VERSION 5.7 ;
  NOWIREEXTENSIONATPIN ON ;
  DIVIDERCHAR "/" ;
  BUSBITCHARS "[]" ;
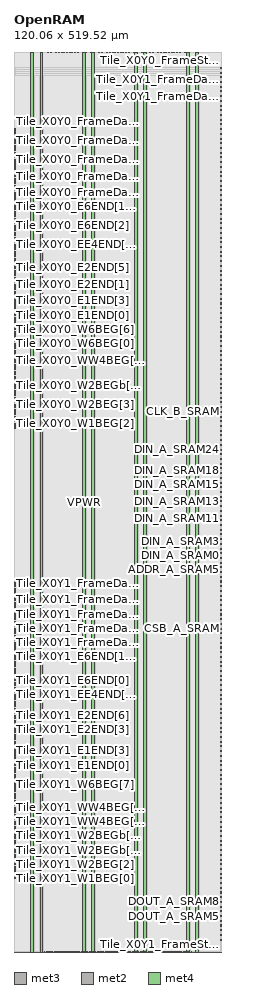
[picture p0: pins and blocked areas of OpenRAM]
MACRO OpenRAM
  CLASS BLOCK ;
  FOREIGN OpenRAM ;
  ORIGIN 0.000 0.000 ;
  SIZE 120.060 BY 519.520 ;
  PIN ADDR_A_SRAM0
    DIRECTION OUTPUT ;
    USE SIGNAL ;
    ANTENNADIFFAREA 0.445500 ;
    PORT
      LAYER met3 ;
        RECT 119.460 202.680 120.060 203.280 ;
    END
  END ADDR_A_SRAM0
  PIN ADDR_A_SRAM1
    DIRECTION OUTPUT ;
    USE SIGNAL ;
    ANTENNADIFFAREA 0.445500 ;
    PORT
      LAYER met3 ;
        RECT 119.460 205.400 120.060 206.000 ;
    END
  END ADDR_A_SRAM1
  PIN ADDR_A_SRAM2
    DIRECTION OUTPUT ;
    USE SIGNAL ;
    ANTENNADIFFAREA 0.445500 ;
    PORT
      LAYER met3 ;
        RECT 119.460 208.120 120.060 208.720 ;
    END
  END ADDR_A_SRAM2
  PIN ADDR_A_SRAM3
    DIRECTION OUTPUT ;
    USE SIGNAL ;
    ANTENNADIFFAREA 0.445500 ;
    PORT
      LAYER met3 ;
        RECT 119.460 210.840 120.060 211.440 ;
    END
  END ADDR_A_SRAM3
  PIN ADDR_A_SRAM4
    DIRECTION OUTPUT ;
    USE SIGNAL ;
    ANTENNADIFFAREA 0.445500 ;
    PORT
      LAYER met3 ;
        RECT 119.460 213.560 120.060 214.160 ;
    END
  END ADDR_A_SRAM4
  PIN ADDR_A_SRAM5
    DIRECTION OUTPUT ;
    USE SIGNAL ;
    ANTENNADIFFAREA 0.445500 ;
    PORT
      LAYER met3 ;
        RECT 119.460 216.280 120.060 216.880 ;
    END
  END ADDR_A_SRAM5
  PIN ADDR_A_SRAM6
    DIRECTION OUTPUT ;
    USE SIGNAL ;
    ANTENNADIFFAREA 0.445500 ;
    PORT
      LAYER met3 ;
        RECT 119.460 219.000 120.060 219.600 ;
    END
  END ADDR_A_SRAM6
  PIN ADDR_A_SRAM7
    DIRECTION OUTPUT ;
    USE SIGNAL ;
    ANTENNADIFFAREA 0.445500 ;
    PORT
      LAYER met3 ;
        RECT 119.460 221.720 120.060 222.320 ;
    END
  END ADDR_A_SRAM7
  PIN ADDR_B_SRAM0
    DIRECTION OUTPUT ;
    USE SIGNAL ;
    ANTENNADIFFAREA 0.445500 ;
    PORT
      LAYER met3 ;
        RECT 119.460 316.920 120.060 317.520 ;
    END
  END ADDR_B_SRAM0
  PIN ADDR_B_SRAM1
    DIRECTION OUTPUT ;
    USE SIGNAL ;
    ANTENNADIFFAREA 0.445500 ;
    PORT
      LAYER met3 ;
        RECT 119.460 319.640 120.060 320.240 ;
    END
  END ADDR_B_SRAM1
  PIN ADDR_B_SRAM2
    DIRECTION OUTPUT ;
    USE SIGNAL ;
    ANTENNADIFFAREA 0.445500 ;
    PORT
      LAYER met3 ;
        RECT 119.460 322.360 120.060 322.960 ;
    END
  END ADDR_B_SRAM2
  PIN ADDR_B_SRAM3
    DIRECTION OUTPUT ;
    USE SIGNAL ;
    ANTENNADIFFAREA 0.445500 ;
    PORT
      LAYER met3 ;
        RECT 119.460 325.080 120.060 325.680 ;
    END
  END ADDR_B_SRAM3
  PIN ADDR_B_SRAM4
    DIRECTION OUTPUT ;
    USE SIGNAL ;
    ANTENNADIFFAREA 0.445500 ;
    PORT
      LAYER met3 ;
        RECT 119.460 327.800 120.060 328.400 ;
    END
  END ADDR_B_SRAM4
  PIN ADDR_B_SRAM5
    DIRECTION OUTPUT ;
    USE SIGNAL ;
    ANTENNADIFFAREA 0.445500 ;
    PORT
      LAYER met3 ;
        RECT 119.460 330.520 120.060 331.120 ;
    END
  END ADDR_B_SRAM5
  PIN ADDR_B_SRAM6
    DIRECTION OUTPUT ;
    USE SIGNAL ;
    ANTENNADIFFAREA 0.445500 ;
    PORT
      LAYER met3 ;
        RECT 119.460 333.240 120.060 333.840 ;
    END
  END ADDR_B_SRAM6
  PIN ADDR_B_SRAM7
    DIRECTION OUTPUT ;
    USE SIGNAL ;
    ANTENNADIFFAREA 0.445500 ;
    PORT
      LAYER met3 ;
        RECT 119.460 335.960 120.060 336.560 ;
    END
  END ADDR_B_SRAM7
  PIN CLK_A_SRAM
    DIRECTION OUTPUT ;
    USE SIGNAL ;
    ANTENNADIFFAREA 0.340600 ;
    PORT
      LAYER met3 ;
        RECT 119.460 183.640 120.060 184.240 ;
    END
  END CLK_A_SRAM
  PIN CLK_B_SRAM
    DIRECTION OUTPUT ;
    USE SIGNAL ;
    ANTENNADIFFAREA 0.340600 ;
    PORT
      LAYER met3 ;
        RECT 119.460 311.480 120.060 312.080 ;
    END
  END CLK_B_SRAM
  PIN CONFIGURED_top
    DIRECTION INPUT ;
    USE SIGNAL ;
    ANTENNAGATEAREA 0.126000 ;
    PORT
      LAYER met3 ;
        RECT 119.460 180.920 120.060 181.520 ;
    END
  END CONFIGURED_top
  PIN CSB_A_SRAM
    DIRECTION OUTPUT ;
    USE SIGNAL ;
    ANTENNADIFFAREA 0.445500 ;
    PORT
      LAYER met3 ;
        RECT 119.460 186.360 120.060 186.960 ;
    END
  END CSB_A_SRAM
  PIN CSB_B_SRAM
    DIRECTION OUTPUT ;
    USE SIGNAL ;
    ANTENNADIFFAREA 0.445500 ;
    PORT
      LAYER met3 ;
        RECT 119.460 314.200 120.060 314.800 ;
    END
  END CSB_B_SRAM
  PIN DIN_A_SRAM0
    DIRECTION OUTPUT ;
    USE SIGNAL ;
    ANTENNADIFFAREA 0.445500 ;
    PORT
      LAYER met3 ;
        RECT 119.460 224.440 120.060 225.040 ;
    END
  END DIN_A_SRAM0
  PIN DIN_A_SRAM1
    DIRECTION OUTPUT ;
    USE SIGNAL ;
    ANTENNADIFFAREA 0.445500 ;
    PORT
      LAYER met3 ;
        RECT 119.460 227.160 120.060 227.760 ;
    END
  END DIN_A_SRAM1
  PIN DIN_A_SRAM10
    DIRECTION OUTPUT ;
    USE SIGNAL ;
    ANTENNADIFFAREA 0.445500 ;
    PORT
      LAYER met3 ;
        RECT 119.460 251.640 120.060 252.240 ;
    END
  END DIN_A_SRAM10
  PIN DIN_A_SRAM11
    DIRECTION OUTPUT ;
    USE SIGNAL ;
    ANTENNADIFFAREA 0.445500 ;
    PORT
      LAYER met3 ;
        RECT 119.460 254.360 120.060 254.960 ;
    END
  END DIN_A_SRAM11
  PIN DIN_A_SRAM12
    DIRECTION OUTPUT ;
    USE SIGNAL ;
    ANTENNADIFFAREA 0.445500 ;
    PORT
      LAYER met3 ;
        RECT 119.460 257.080 120.060 257.680 ;
    END
  END DIN_A_SRAM12
  PIN DIN_A_SRAM13
    DIRECTION OUTPUT ;
    USE SIGNAL ;
    ANTENNADIFFAREA 0.445500 ;
    PORT
      LAYER met3 ;
        RECT 119.460 259.800 120.060 260.400 ;
    END
  END DIN_A_SRAM13
  PIN DIN_A_SRAM14
    DIRECTION OUTPUT ;
    USE SIGNAL ;
    ANTENNADIFFAREA 0.445500 ;
    PORT
      LAYER met3 ;
        RECT 119.460 262.520 120.060 263.120 ;
    END
  END DIN_A_SRAM14
  PIN DIN_A_SRAM15
    DIRECTION OUTPUT ;
    USE SIGNAL ;
    ANTENNADIFFAREA 0.445500 ;
    PORT
      LAYER met3 ;
        RECT 119.460 265.240 120.060 265.840 ;
    END
  END DIN_A_SRAM15
  PIN DIN_A_SRAM16
    DIRECTION OUTPUT ;
    USE SIGNAL ;
    ANTENNADIFFAREA 0.445500 ;
    PORT
      LAYER met3 ;
        RECT 119.460 267.960 120.060 268.560 ;
    END
  END DIN_A_SRAM16
  PIN DIN_A_SRAM17
    DIRECTION OUTPUT ;
    USE SIGNAL ;
    ANTENNADIFFAREA 0.445500 ;
    PORT
      LAYER met3 ;
        RECT 119.460 270.680 120.060 271.280 ;
    END
  END DIN_A_SRAM17
  PIN DIN_A_SRAM18
    DIRECTION OUTPUT ;
    USE SIGNAL ;
    ANTENNADIFFAREA 0.445500 ;
    PORT
      LAYER met3 ;
        RECT 119.460 273.400 120.060 274.000 ;
    END
  END DIN_A_SRAM18
  PIN DIN_A_SRAM19
    DIRECTION OUTPUT ;
    USE SIGNAL ;
    ANTENNADIFFAREA 0.445500 ;
    PORT
      LAYER met3 ;
        RECT 119.460 276.120 120.060 276.720 ;
    END
  END DIN_A_SRAM19
  PIN DIN_A_SRAM2
    DIRECTION OUTPUT ;
    USE SIGNAL ;
    ANTENNADIFFAREA 0.445500 ;
    PORT
      LAYER met3 ;
        RECT 119.460 229.880 120.060 230.480 ;
    END
  END DIN_A_SRAM2
  PIN DIN_A_SRAM20
    DIRECTION OUTPUT ;
    USE SIGNAL ;
    ANTENNADIFFAREA 0.445500 ;
    PORT
      LAYER met3 ;
        RECT 119.460 278.840 120.060 279.440 ;
    END
  END DIN_A_SRAM20
  PIN DIN_A_SRAM21
    DIRECTION OUTPUT ;
    USE SIGNAL ;
    ANTENNADIFFAREA 0.445500 ;
    PORT
      LAYER met3 ;
        RECT 119.460 281.560 120.060 282.160 ;
    END
  END DIN_A_SRAM21
  PIN DIN_A_SRAM22
    DIRECTION OUTPUT ;
    USE SIGNAL ;
    ANTENNADIFFAREA 0.445500 ;
    PORT
      LAYER met3 ;
        RECT 119.460 284.280 120.060 284.880 ;
    END
  END DIN_A_SRAM22
  PIN DIN_A_SRAM23
    DIRECTION OUTPUT ;
    USE SIGNAL ;
    ANTENNADIFFAREA 0.445500 ;
    PORT
      LAYER met3 ;
        RECT 119.460 287.000 120.060 287.600 ;
    END
  END DIN_A_SRAM23
  PIN DIN_A_SRAM24
    DIRECTION OUTPUT ;
    USE SIGNAL ;
    ANTENNADIFFAREA 0.445500 ;
    PORT
      LAYER met3 ;
        RECT 119.460 289.720 120.060 290.320 ;
    END
  END DIN_A_SRAM24
  PIN DIN_A_SRAM25
    DIRECTION OUTPUT ;
    USE SIGNAL ;
    ANTENNADIFFAREA 0.445500 ;
    PORT
      LAYER met3 ;
        RECT 119.460 292.440 120.060 293.040 ;
    END
  END DIN_A_SRAM25
  PIN DIN_A_SRAM26
    DIRECTION OUTPUT ;
    USE SIGNAL ;
    ANTENNADIFFAREA 0.445500 ;
    PORT
      LAYER met3 ;
        RECT 119.460 295.160 120.060 295.760 ;
    END
  END DIN_A_SRAM26
  PIN DIN_A_SRAM27
    DIRECTION OUTPUT ;
    USE SIGNAL ;
    ANTENNADIFFAREA 0.445500 ;
    PORT
      LAYER met3 ;
        RECT 119.460 297.880 120.060 298.480 ;
    END
  END DIN_A_SRAM27
  PIN DIN_A_SRAM28
    DIRECTION OUTPUT ;
    USE SIGNAL ;
    ANTENNADIFFAREA 0.445500 ;
    PORT
      LAYER met3 ;
        RECT 119.460 300.600 120.060 301.200 ;
    END
  END DIN_A_SRAM28
  PIN DIN_A_SRAM29
    DIRECTION OUTPUT ;
    USE SIGNAL ;
    ANTENNADIFFAREA 0.445500 ;
    PORT
      LAYER met3 ;
        RECT 119.460 303.320 120.060 303.920 ;
    END
  END DIN_A_SRAM29
  PIN DIN_A_SRAM3
    DIRECTION OUTPUT ;
    USE SIGNAL ;
    ANTENNADIFFAREA 0.445500 ;
    PORT
      LAYER met3 ;
        RECT 119.460 232.600 120.060 233.200 ;
    END
  END DIN_A_SRAM3
  PIN DIN_A_SRAM30
    DIRECTION OUTPUT ;
    USE SIGNAL ;
    ANTENNADIFFAREA 0.445500 ;
    PORT
      LAYER met3 ;
        RECT 119.460 306.040 120.060 306.640 ;
    END
  END DIN_A_SRAM30
  PIN DIN_A_SRAM31
    DIRECTION OUTPUT ;
    USE SIGNAL ;
    ANTENNADIFFAREA 0.445500 ;
    PORT
      LAYER met3 ;
        RECT 119.460 308.760 120.060 309.360 ;
    END
  END DIN_A_SRAM31
  PIN DIN_A_SRAM4
    DIRECTION OUTPUT ;
    USE SIGNAL ;
    ANTENNADIFFAREA 0.445500 ;
    PORT
      LAYER met3 ;
        RECT 119.460 235.320 120.060 235.920 ;
    END
  END DIN_A_SRAM4
  PIN DIN_A_SRAM5
    DIRECTION OUTPUT ;
    USE SIGNAL ;
    ANTENNADIFFAREA 0.445500 ;
    PORT
      LAYER met3 ;
        RECT 119.460 238.040 120.060 238.640 ;
    END
  END DIN_A_SRAM5
  PIN DIN_A_SRAM6
    DIRECTION OUTPUT ;
    USE SIGNAL ;
    ANTENNADIFFAREA 0.445500 ;
    PORT
      LAYER met3 ;
        RECT 119.460 240.760 120.060 241.360 ;
    END
  END DIN_A_SRAM6
  PIN DIN_A_SRAM7
    DIRECTION OUTPUT ;
    USE SIGNAL ;
    ANTENNADIFFAREA 0.445500 ;
    PORT
      LAYER met3 ;
        RECT 119.460 243.480 120.060 244.080 ;
    END
  END DIN_A_SRAM7
  PIN DIN_A_SRAM8
    DIRECTION OUTPUT ;
    USE SIGNAL ;
    ANTENNADIFFAREA 0.445500 ;
    PORT
      LAYER met3 ;
        RECT 119.460 246.200 120.060 246.800 ;
    END
  END DIN_A_SRAM8
  PIN DIN_A_SRAM9
    DIRECTION OUTPUT ;
    USE SIGNAL ;
    ANTENNADIFFAREA 0.445500 ;
    PORT
      LAYER met3 ;
        RECT 119.460 248.920 120.060 249.520 ;
    END
  END DIN_A_SRAM9
  PIN DOUT_A_SRAM0
    DIRECTION INPUT ;
    USE SIGNAL ;
    ANTENNAGATEAREA 0.213000 ;
    PORT
      LAYER met3 ;
        RECT 119.460 6.840 120.060 7.440 ;
    END
  END DOUT_A_SRAM0
  PIN DOUT_A_SRAM1
    DIRECTION INPUT ;
    USE SIGNAL ;
    ANTENNAGATEAREA 0.196500 ;
    PORT
      LAYER met3 ;
        RECT 119.460 9.560 120.060 10.160 ;
    END
  END DOUT_A_SRAM1
  PIN DOUT_A_SRAM10
    DIRECTION INPUT ;
    USE SIGNAL ;
    ANTENNAGATEAREA 0.196500 ;
    PORT
      LAYER met3 ;
        RECT 119.460 34.040 120.060 34.640 ;
    END
  END DOUT_A_SRAM10
  PIN DOUT_A_SRAM11
    DIRECTION INPUT ;
    USE SIGNAL ;
    ANTENNAGATEAREA 0.196500 ;
    PORT
      LAYER met3 ;
        RECT 119.460 36.760 120.060 37.360 ;
    END
  END DOUT_A_SRAM11
  PIN DOUT_A_SRAM12
    DIRECTION INPUT ;
    USE SIGNAL ;
    ANTENNAGATEAREA 0.196500 ;
    PORT
      LAYER met3 ;
        RECT 119.460 39.480 120.060 40.080 ;
    END
  END DOUT_A_SRAM12
  PIN DOUT_A_SRAM13
    DIRECTION INPUT ;
    USE SIGNAL ;
    ANTENNAGATEAREA 0.196500 ;
    PORT
      LAYER met3 ;
        RECT 119.460 42.200 120.060 42.800 ;
    END
  END DOUT_A_SRAM13
  PIN DOUT_A_SRAM14
    DIRECTION INPUT ;
    USE SIGNAL ;
    ANTENNAGATEAREA 0.196500 ;
    PORT
      LAYER met3 ;
        RECT 119.460 44.920 120.060 45.520 ;
    END
  END DOUT_A_SRAM14
  PIN DOUT_A_SRAM15
    DIRECTION INPUT ;
    USE SIGNAL ;
    ANTENNAGATEAREA 0.196500 ;
    PORT
      LAYER met3 ;
        RECT 119.460 47.640 120.060 48.240 ;
    END
  END DOUT_A_SRAM15
  PIN DOUT_A_SRAM16
    DIRECTION INPUT ;
    USE SIGNAL ;
    ANTENNAGATEAREA 0.159000 ;
    PORT
      LAYER met3 ;
        RECT 119.460 50.360 120.060 50.960 ;
    END
  END DOUT_A_SRAM16
  PIN DOUT_A_SRAM17
    DIRECTION INPUT ;
    USE SIGNAL ;
    ANTENNAGATEAREA 0.159000 ;
    PORT
      LAYER met3 ;
        RECT 119.460 53.080 120.060 53.680 ;
    END
  END DOUT_A_SRAM17
  PIN DOUT_A_SRAM18
    DIRECTION INPUT ;
    USE SIGNAL ;
    ANTENNAGATEAREA 0.213000 ;
    PORT
      LAYER met3 ;
        RECT 119.460 55.800 120.060 56.400 ;
    END
  END DOUT_A_SRAM18
  PIN DOUT_A_SRAM19
    DIRECTION INPUT ;
    USE SIGNAL ;
    ANTENNAGATEAREA 0.159000 ;
    PORT
      LAYER met3 ;
        RECT 119.460 58.520 120.060 59.120 ;
    END
  END DOUT_A_SRAM19
  PIN DOUT_A_SRAM2
    DIRECTION INPUT ;
    USE SIGNAL ;
    ANTENNAGATEAREA 0.196500 ;
    PORT
      LAYER met3 ;
        RECT 119.460 12.280 120.060 12.880 ;
    END
  END DOUT_A_SRAM2
  PIN DOUT_A_SRAM20
    DIRECTION INPUT ;
    USE SIGNAL ;
    ANTENNAGATEAREA 0.159000 ;
    PORT
      LAYER met3 ;
        RECT 119.460 61.240 120.060 61.840 ;
    END
  END DOUT_A_SRAM20
  PIN DOUT_A_SRAM21
    DIRECTION INPUT ;
    USE SIGNAL ;
    ANTENNAGATEAREA 0.213000 ;
    PORT
      LAYER met3 ;
        RECT 119.460 63.960 120.060 64.560 ;
    END
  END DOUT_A_SRAM21
  PIN DOUT_A_SRAM22
    DIRECTION INPUT ;
    USE SIGNAL ;
    ANTENNAGATEAREA 0.159000 ;
    PORT
      LAYER met3 ;
        RECT 119.460 66.680 120.060 67.280 ;
    END
  END DOUT_A_SRAM22
  PIN DOUT_A_SRAM23
    DIRECTION INPUT ;
    USE SIGNAL ;
    ANTENNAGATEAREA 0.159000 ;
    PORT
      LAYER met3 ;
        RECT 119.460 69.400 120.060 70.000 ;
    END
  END DOUT_A_SRAM23
  PIN DOUT_A_SRAM24
    DIRECTION INPUT ;
    USE SIGNAL ;
    ANTENNAGATEAREA 0.213000 ;
    PORT
      LAYER met3 ;
        RECT 119.460 72.120 120.060 72.720 ;
    END
  END DOUT_A_SRAM24
  PIN DOUT_A_SRAM25
    DIRECTION INPUT ;
    USE SIGNAL ;
    ANTENNAGATEAREA 0.159000 ;
    PORT
      LAYER met3 ;
        RECT 119.460 74.840 120.060 75.440 ;
    END
  END DOUT_A_SRAM25
  PIN DOUT_A_SRAM26
    DIRECTION INPUT ;
    USE SIGNAL ;
    ANTENNAGATEAREA 0.213000 ;
    PORT
      LAYER met3 ;
        RECT 119.460 77.560 120.060 78.160 ;
    END
  END DOUT_A_SRAM26
  PIN DOUT_A_SRAM27
    DIRECTION INPUT ;
    USE SIGNAL ;
    ANTENNAGATEAREA 0.213000 ;
    PORT
      LAYER met3 ;
        RECT 119.460 80.280 120.060 80.880 ;
    END
  END DOUT_A_SRAM27
  PIN DOUT_A_SRAM28
    DIRECTION INPUT ;
    USE SIGNAL ;
    ANTENNAGATEAREA 0.213000 ;
    PORT
      LAYER met3 ;
        RECT 119.460 83.000 120.060 83.600 ;
    END
  END DOUT_A_SRAM28
  PIN DOUT_A_SRAM29
    DIRECTION INPUT ;
    USE SIGNAL ;
    ANTENNAGATEAREA 0.213000 ;
    PORT
      LAYER met3 ;
        RECT 119.460 85.720 120.060 86.320 ;
    END
  END DOUT_A_SRAM29
  PIN DOUT_A_SRAM3
    DIRECTION INPUT ;
    USE SIGNAL ;
    ANTENNAGATEAREA 0.213000 ;
    PORT
      LAYER met3 ;
        RECT 119.460 15.000 120.060 15.600 ;
    END
  END DOUT_A_SRAM3
  PIN DOUT_A_SRAM30
    DIRECTION INPUT ;
    USE SIGNAL ;
    ANTENNAGATEAREA 0.213000 ;
    PORT
      LAYER met3 ;
        RECT 119.460 88.440 120.060 89.040 ;
    END
  END DOUT_A_SRAM30
  PIN DOUT_A_SRAM31
    DIRECTION INPUT ;
    USE SIGNAL ;
    ANTENNAGATEAREA 0.213000 ;
    PORT
      LAYER met3 ;
        RECT 119.460 91.160 120.060 91.760 ;
    END
  END DOUT_A_SRAM31
  PIN DOUT_A_SRAM4
    DIRECTION INPUT ;
    USE SIGNAL ;
    ANTENNAGATEAREA 0.126000 ;
    PORT
      LAYER met3 ;
        RECT 119.460 17.720 120.060 18.320 ;
    END
  END DOUT_A_SRAM4
  PIN DOUT_A_SRAM5
    DIRECTION INPUT ;
    USE SIGNAL ;
    ANTENNAGATEAREA 0.196500 ;
    PORT
      LAYER met3 ;
        RECT 119.460 20.440 120.060 21.040 ;
    END
  END DOUT_A_SRAM5
  PIN DOUT_A_SRAM6
    DIRECTION INPUT ;
    USE SIGNAL ;
    ANTENNAGATEAREA 0.196500 ;
    PORT
      LAYER met3 ;
        RECT 119.460 23.160 120.060 23.760 ;
    END
  END DOUT_A_SRAM6
  PIN DOUT_A_SRAM7
    DIRECTION INPUT ;
    USE SIGNAL ;
    ANTENNAGATEAREA 0.126000 ;
    PORT
      LAYER met3 ;
        RECT 119.460 25.880 120.060 26.480 ;
    END
  END DOUT_A_SRAM7
  PIN DOUT_A_SRAM8
    DIRECTION INPUT ;
    USE SIGNAL ;
    ANTENNAGATEAREA 0.126000 ;
    PORT
      LAYER met3 ;
        RECT 119.460 28.600 120.060 29.200 ;
    END
  END DOUT_A_SRAM8
  PIN DOUT_A_SRAM9
    DIRECTION INPUT ;
    USE SIGNAL ;
    ANTENNAGATEAREA 0.196500 ;
    PORT
      LAYER met3 ;
        RECT 119.460 31.320 120.060 31.920 ;
    END
  END DOUT_A_SRAM9
  PIN DOUT_B_SRAM0
    DIRECTION INPUT ;
    USE SIGNAL ;
    ANTENNAGATEAREA 0.126000 ;
    PORT
      LAYER met3 ;
        RECT 119.460 93.880 120.060 94.480 ;
    END
  END DOUT_B_SRAM0
  PIN DOUT_B_SRAM1
    DIRECTION INPUT ;
    USE SIGNAL ;
    ANTENNAGATEAREA 0.196500 ;
    PORT
      LAYER met3 ;
        RECT 119.460 96.600 120.060 97.200 ;
    END
  END DOUT_B_SRAM1
  PIN DOUT_B_SRAM10
    DIRECTION INPUT ;
    USE SIGNAL ;
    ANTENNAGATEAREA 0.196500 ;
    PORT
      LAYER met3 ;
        RECT 119.460 121.080 120.060 121.680 ;
    END
  END DOUT_B_SRAM10
  PIN DOUT_B_SRAM11
    DIRECTION INPUT ;
    USE SIGNAL ;
    ANTENNAGATEAREA 0.196500 ;
    PORT
      LAYER met3 ;
        RECT 119.460 123.800 120.060 124.400 ;
    END
  END DOUT_B_SRAM11
  PIN DOUT_B_SRAM12
    DIRECTION INPUT ;
    USE SIGNAL ;
    ANTENNAGATEAREA 0.126000 ;
    PORT
      LAYER met3 ;
        RECT 119.460 126.520 120.060 127.120 ;
    END
  END DOUT_B_SRAM12
  PIN DOUT_B_SRAM13
    DIRECTION INPUT ;
    USE SIGNAL ;
    ANTENNAGATEAREA 0.196500 ;
    PORT
      LAYER met3 ;
        RECT 119.460 129.240 120.060 129.840 ;
    END
  END DOUT_B_SRAM13
  PIN DOUT_B_SRAM14
    DIRECTION INPUT ;
    USE SIGNAL ;
    ANTENNAGATEAREA 0.196500 ;
    PORT
      LAYER met3 ;
        RECT 119.460 131.960 120.060 132.560 ;
    END
  END DOUT_B_SRAM14
  PIN DOUT_B_SRAM15
    DIRECTION INPUT ;
    USE SIGNAL ;
    ANTENNAGATEAREA 0.196500 ;
    PORT
      LAYER met3 ;
        RECT 119.460 134.680 120.060 135.280 ;
    END
  END DOUT_B_SRAM15
  PIN DOUT_B_SRAM16
    DIRECTION INPUT ;
    USE SIGNAL ;
    ANTENNAGATEAREA 0.213000 ;
    PORT
      LAYER met3 ;
        RECT 119.460 137.400 120.060 138.000 ;
    END
  END DOUT_B_SRAM16
  PIN DOUT_B_SRAM17
    DIRECTION INPUT ;
    USE SIGNAL ;
    ANTENNAGATEAREA 0.213000 ;
    PORT
      LAYER met3 ;
        RECT 119.460 140.120 120.060 140.720 ;
    END
  END DOUT_B_SRAM17
  PIN DOUT_B_SRAM18
    DIRECTION INPUT ;
    USE SIGNAL ;
    ANTENNAGATEAREA 0.159000 ;
    PORT
      LAYER met3 ;
        RECT 119.460 142.840 120.060 143.440 ;
    END
  END DOUT_B_SRAM18
  PIN DOUT_B_SRAM19
    DIRECTION INPUT ;
    USE SIGNAL ;
    ANTENNAGATEAREA 0.213000 ;
    PORT
      LAYER met3 ;
        RECT 119.460 145.560 120.060 146.160 ;
    END
  END DOUT_B_SRAM19
  PIN DOUT_B_SRAM2
    DIRECTION INPUT ;
    USE SIGNAL ;
    ANTENNAGATEAREA 0.196500 ;
    PORT
      LAYER met3 ;
        RECT 119.460 99.320 120.060 99.920 ;
    END
  END DOUT_B_SRAM2
  PIN DOUT_B_SRAM20
    DIRECTION INPUT ;
    USE SIGNAL ;
    ANTENNAGATEAREA 0.213000 ;
    PORT
      LAYER met3 ;
        RECT 119.460 148.280 120.060 148.880 ;
    END
  END DOUT_B_SRAM20
  PIN DOUT_B_SRAM21
    DIRECTION INPUT ;
    USE SIGNAL ;
    ANTENNAGATEAREA 0.159000 ;
    PORT
      LAYER met3 ;
        RECT 119.460 151.000 120.060 151.600 ;
    END
  END DOUT_B_SRAM21
  PIN DOUT_B_SRAM22
    DIRECTION INPUT ;
    USE SIGNAL ;
    ANTENNAGATEAREA 0.213000 ;
    PORT
      LAYER met3 ;
        RECT 119.460 153.720 120.060 154.320 ;
    END
  END DOUT_B_SRAM22
  PIN DOUT_B_SRAM23
    DIRECTION INPUT ;
    USE SIGNAL ;
    ANTENNAGATEAREA 0.213000 ;
    PORT
      LAYER met3 ;
        RECT 119.460 156.440 120.060 157.040 ;
    END
  END DOUT_B_SRAM23
  PIN DOUT_B_SRAM24
    DIRECTION INPUT ;
    USE SIGNAL ;
    ANTENNAGATEAREA 0.126000 ;
    PORT
      LAYER met3 ;
        RECT 119.460 159.160 120.060 159.760 ;
    END
  END DOUT_B_SRAM24
  PIN DOUT_B_SRAM25
    DIRECTION INPUT ;
    USE SIGNAL ;
    ANTENNAGATEAREA 0.213000 ;
    PORT
      LAYER met3 ;
        RECT 119.460 161.880 120.060 162.480 ;
    END
  END DOUT_B_SRAM25
  PIN DOUT_B_SRAM26
    DIRECTION INPUT ;
    USE SIGNAL ;
    ANTENNAGATEAREA 0.196500 ;
    PORT
      LAYER met3 ;
        RECT 119.460 164.600 120.060 165.200 ;
    END
  END DOUT_B_SRAM26
  PIN DOUT_B_SRAM27
    DIRECTION INPUT ;
    USE SIGNAL ;
    ANTENNAGATEAREA 0.196500 ;
    PORT
      LAYER met3 ;
        RECT 119.460 167.320 120.060 167.920 ;
    END
  END DOUT_B_SRAM27
  PIN DOUT_B_SRAM28
    DIRECTION INPUT ;
    USE SIGNAL ;
    ANTENNAGATEAREA 0.196500 ;
    PORT
      LAYER met3 ;
        RECT 119.460 170.040 120.060 170.640 ;
    END
  END DOUT_B_SRAM28
  PIN DOUT_B_SRAM29
    DIRECTION INPUT ;
    USE SIGNAL ;
    ANTENNAGATEAREA 0.213000 ;
    PORT
      LAYER met3 ;
        RECT 119.460 172.760 120.060 173.360 ;
    END
  END DOUT_B_SRAM29
  PIN DOUT_B_SRAM3
    DIRECTION INPUT ;
    USE SIGNAL ;
    ANTENNAGATEAREA 0.196500 ;
    PORT
      LAYER met3 ;
        RECT 119.460 102.040 120.060 102.640 ;
    END
  END DOUT_B_SRAM3
  PIN DOUT_B_SRAM30
    DIRECTION INPUT ;
    USE SIGNAL ;
    ANTENNAGATEAREA 0.126000 ;
    PORT
      LAYER met3 ;
        RECT 119.460 175.480 120.060 176.080 ;
    END
  END DOUT_B_SRAM30
  PIN DOUT_B_SRAM31
    DIRECTION INPUT ;
    USE SIGNAL ;
    ANTENNAGATEAREA 0.196500 ;
    PORT
      LAYER met3 ;
        RECT 119.460 178.200 120.060 178.800 ;
    END
  END DOUT_B_SRAM31
  PIN DOUT_B_SRAM4
    DIRECTION INPUT ;
    USE SIGNAL ;
    ANTENNAGATEAREA 0.126000 ;
    PORT
      LAYER met3 ;
        RECT 119.460 104.760 120.060 105.360 ;
    END
  END DOUT_B_SRAM4
  PIN DOUT_B_SRAM5
    DIRECTION INPUT ;
    USE SIGNAL ;
    ANTENNAGATEAREA 0.196500 ;
    PORT
      LAYER met3 ;
        RECT 119.460 107.480 120.060 108.080 ;
    END
  END DOUT_B_SRAM5
  PIN DOUT_B_SRAM6
    DIRECTION INPUT ;
    USE SIGNAL ;
    ANTENNAGATEAREA 0.196500 ;
    PORT
      LAYER met3 ;
        RECT 119.460 110.200 120.060 110.800 ;
    END
  END DOUT_B_SRAM6
  PIN DOUT_B_SRAM7
    DIRECTION INPUT ;
    USE SIGNAL ;
    ANTENNAGATEAREA 0.196500 ;
    PORT
      LAYER met3 ;
        RECT 119.460 112.920 120.060 113.520 ;
    END
  END DOUT_B_SRAM7
  PIN DOUT_B_SRAM8
    DIRECTION INPUT ;
    USE SIGNAL ;
    ANTENNAGATEAREA 0.196500 ;
    PORT
      LAYER met3 ;
        RECT 119.460 115.640 120.060 116.240 ;
    END
  END DOUT_B_SRAM8
  PIN DOUT_B_SRAM9
    DIRECTION INPUT ;
    USE SIGNAL ;
    ANTENNAGATEAREA 0.196500 ;
    PORT
      LAYER met3 ;
        RECT 119.460 118.360 120.060 118.960 ;
    END
  END DOUT_B_SRAM9
  PIN Tile_X0Y0_E1END[0]
    DIRECTION INPUT ;
    USE SIGNAL ;
    ANTENNAGATEAREA 0.159000 ;
    PORT
      LAYER met3 ;
        RECT 0.000 367.240 0.600 367.840 ;
    END
  END Tile_X0Y0_E1END[0]
  PIN Tile_X0Y0_E1END[1]
    DIRECTION INPUT ;
    USE SIGNAL ;
    ANTENNAGATEAREA 0.159000 ;
    PORT
      LAYER met3 ;
        RECT 0.000 368.600 0.600 369.200 ;
    END
  END Tile_X0Y0_E1END[1]
  PIN Tile_X0Y0_E1END[2]
    DIRECTION INPUT ;
    USE SIGNAL ;
    ANTENNAGATEAREA 0.213000 ;
    PORT
      LAYER met3 ;
        RECT 0.000 369.960 0.600 370.560 ;
    END
  END Tile_X0Y0_E1END[2]
  PIN Tile_X0Y0_E1END[3]
    DIRECTION INPUT ;
    USE SIGNAL ;
    ANTENNAGATEAREA 0.213000 ;
    PORT
      LAYER met3 ;
        RECT 0.000 371.320 0.600 371.920 ;
    END
  END Tile_X0Y0_E1END[3]
  PIN Tile_X0Y0_E2END[0]
    DIRECTION INPUT ;
    USE SIGNAL ;
    ANTENNAGATEAREA 0.126000 ;
    PORT
      LAYER met3 ;
        RECT 0.000 383.560 0.600 384.160 ;
    END
  END Tile_X0Y0_E2END[0]
  PIN Tile_X0Y0_E2END[1]
    DIRECTION INPUT ;
    USE SIGNAL ;
    ANTENNAGATEAREA 0.213000 ;
    PORT
      LAYER met3 ;
        RECT 0.000 384.920 0.600 385.520 ;
    END
  END Tile_X0Y0_E2END[1]
  PIN Tile_X0Y0_E2END[2]
    DIRECTION INPUT ;
    USE SIGNAL ;
    ANTENNAGATEAREA 0.213000 ;
    PORT
      LAYER met3 ;
        RECT 0.000 386.280 0.600 386.880 ;
    END
  END Tile_X0Y0_E2END[2]
  PIN Tile_X0Y0_E2END[3]
    DIRECTION INPUT ;
    USE SIGNAL ;
    ANTENNAGATEAREA 0.126000 ;
    PORT
      LAYER met3 ;
        RECT 0.000 387.640 0.600 388.240 ;
    END
  END Tile_X0Y0_E2END[3]
  PIN Tile_X0Y0_E2END[4]
    DIRECTION INPUT ;
    USE SIGNAL ;
    ANTENNAGATEAREA 0.196500 ;
    PORT
      LAYER met3 ;
        RECT 0.000 389.000 0.600 389.600 ;
    END
  END Tile_X0Y0_E2END[4]
  PIN Tile_X0Y0_E2END[5]
    DIRECTION INPUT ;
    USE SIGNAL ;
    ANTENNAGATEAREA 0.196500 ;
    PORT
      LAYER met3 ;
        RECT 0.000 390.360 0.600 390.960 ;
    END
  END Tile_X0Y0_E2END[5]
  PIN Tile_X0Y0_E2END[6]
    DIRECTION INPUT ;
    USE SIGNAL ;
    ANTENNAGATEAREA 0.196500 ;
    PORT
      LAYER met3 ;
        RECT 0.000 391.720 0.600 392.320 ;
    END
  END Tile_X0Y0_E2END[6]
  PIN Tile_X0Y0_E2END[7]
    DIRECTION INPUT ;
    USE SIGNAL ;
    ANTENNAGATEAREA 0.196500 ;
    PORT
      LAYER met3 ;
        RECT 0.000 393.080 0.600 393.680 ;
    END
  END Tile_X0Y0_E2END[7]
  PIN Tile_X0Y0_E2MID[0]
    DIRECTION INPUT ;
    USE SIGNAL ;
    ANTENNAGATEAREA 0.196500 ;
    PORT
      LAYER met3 ;
        RECT 0.000 372.680 0.600 373.280 ;
    END
  END Tile_X0Y0_E2MID[0]
  PIN Tile_X0Y0_E2MID[1]
    DIRECTION INPUT ;
    USE SIGNAL ;
    ANTENNAGATEAREA 0.213000 ;
    PORT
      LAYER met3 ;
        RECT 0.000 374.040 0.600 374.640 ;
    END
  END Tile_X0Y0_E2MID[1]
  PIN Tile_X0Y0_E2MID[2]
    DIRECTION INPUT ;
    USE SIGNAL ;
    ANTENNAGATEAREA 0.126000 ;
    PORT
      LAYER met3 ;
        RECT 0.000 375.400 0.600 376.000 ;
    END
  END Tile_X0Y0_E2MID[2]
  PIN Tile_X0Y0_E2MID[3]
    DIRECTION INPUT ;
    USE SIGNAL ;
    ANTENNAGATEAREA 0.126000 ;
    PORT
      LAYER met3 ;
        RECT 0.000 376.760 0.600 377.360 ;
    END
  END Tile_X0Y0_E2MID[3]
  PIN Tile_X0Y0_E2MID[4]
    DIRECTION INPUT ;
    USE SIGNAL ;
    ANTENNAGATEAREA 0.196500 ;
    PORT
      LAYER met3 ;
        RECT 0.000 378.120 0.600 378.720 ;
    END
  END Tile_X0Y0_E2MID[4]
  PIN Tile_X0Y0_E2MID[5]
    DIRECTION INPUT ;
    USE SIGNAL ;
    ANTENNAGATEAREA 0.196500 ;
    PORT
      LAYER met3 ;
        RECT 0.000 379.480 0.600 380.080 ;
    END
  END Tile_X0Y0_E2MID[5]
  PIN Tile_X0Y0_E2MID[6]
    DIRECTION INPUT ;
    USE SIGNAL ;
    ANTENNAGATEAREA 0.196500 ;
    PORT
      LAYER met3 ;
        RECT 0.000 380.840 0.600 381.440 ;
    END
  END Tile_X0Y0_E2MID[6]
  PIN Tile_X0Y0_E2MID[7]
    DIRECTION INPUT ;
    USE SIGNAL ;
    ANTENNAGATEAREA 0.196500 ;
    PORT
      LAYER met3 ;
        RECT 0.000 382.200 0.600 382.800 ;
    END
  END Tile_X0Y0_E2MID[7]
  PIN Tile_X0Y0_E6END[0]
    DIRECTION INPUT ;
    USE SIGNAL ;
    ANTENNAGATEAREA 0.213000 ;
    PORT
      LAYER met3 ;
        RECT 0.000 416.200 0.600 416.800 ;
    END
  END Tile_X0Y0_E6END[0]
  PIN Tile_X0Y0_E6END[10]
    DIRECTION INPUT ;
    USE SIGNAL ;
    ANTENNAGATEAREA 0.126000 ;
    PORT
      LAYER met3 ;
        RECT 0.000 429.800 0.600 430.400 ;
    END
  END Tile_X0Y0_E6END[10]
  PIN Tile_X0Y0_E6END[11]
    DIRECTION INPUT ;
    USE SIGNAL ;
    ANTENNAGATEAREA 0.213000 ;
    PORT
      LAYER met3 ;
        RECT 0.000 431.160 0.600 431.760 ;
    END
  END Tile_X0Y0_E6END[11]
  PIN Tile_X0Y0_E6END[1]
    DIRECTION INPUT ;
    USE SIGNAL ;
    ANTENNAGATEAREA 0.213000 ;
    PORT
      LAYER met3 ;
        RECT 0.000 417.560 0.600 418.160 ;
    END
  END Tile_X0Y0_E6END[1]
  PIN Tile_X0Y0_E6END[2]
    DIRECTION INPUT ;
    USE SIGNAL ;
    ANTENNAGATEAREA 0.126000 ;
    PORT
      LAYER met3 ;
        RECT 0.000 418.920 0.600 419.520 ;
    END
  END Tile_X0Y0_E6END[2]
  PIN Tile_X0Y0_E6END[3]
    DIRECTION INPUT ;
    USE SIGNAL ;
    ANTENNAGATEAREA 0.126000 ;
    PORT
      LAYER met3 ;
        RECT 0.000 420.280 0.600 420.880 ;
    END
  END Tile_X0Y0_E6END[3]
  PIN Tile_X0Y0_E6END[4]
    DIRECTION INPUT ;
    USE SIGNAL ;
    ANTENNAGATEAREA 0.126000 ;
    PORT
      LAYER met3 ;
        RECT 0.000 421.640 0.600 422.240 ;
    END
  END Tile_X0Y0_E6END[4]
  PIN Tile_X0Y0_E6END[5]
    DIRECTION INPUT ;
    USE SIGNAL ;
    ANTENNAGATEAREA 0.126000 ;
    PORT
      LAYER met3 ;
        RECT 0.000 423.000 0.600 423.600 ;
    END
  END Tile_X0Y0_E6END[5]
  PIN Tile_X0Y0_E6END[6]
    DIRECTION INPUT ;
    USE SIGNAL ;
    ANTENNAGATEAREA 0.213000 ;
    PORT
      LAYER met3 ;
        RECT 0.000 424.360 0.600 424.960 ;
    END
  END Tile_X0Y0_E6END[6]
  PIN Tile_X0Y0_E6END[7]
    DIRECTION INPUT ;
    USE SIGNAL ;
    ANTENNAGATEAREA 0.213000 ;
    PORT
      LAYER met3 ;
        RECT 0.000 425.720 0.600 426.320 ;
    END
  END Tile_X0Y0_E6END[7]
  PIN Tile_X0Y0_E6END[8]
    DIRECTION INPUT ;
    USE SIGNAL ;
    ANTENNAGATEAREA 0.126000 ;
    PORT
      LAYER met3 ;
        RECT 0.000 427.080 0.600 427.680 ;
    END
  END Tile_X0Y0_E6END[8]
  PIN Tile_X0Y0_E6END[9]
    DIRECTION INPUT ;
    USE SIGNAL ;
    ANTENNAGATEAREA 0.196500 ;
    PORT
      LAYER met3 ;
        RECT 0.000 428.440 0.600 429.040 ;
    END
  END Tile_X0Y0_E6END[9]
  PIN Tile_X0Y0_EE4END[0]
    DIRECTION INPUT ;
    USE SIGNAL ;
    ANTENNAGATEAREA 0.213000 ;
    PORT
      LAYER met3 ;
        RECT 0.000 394.440 0.600 395.040 ;
    END
  END Tile_X0Y0_EE4END[0]
  PIN Tile_X0Y0_EE4END[10]
    DIRECTION INPUT ;
    USE SIGNAL ;
    ANTENNAGATEAREA 0.196500 ;
    PORT
      LAYER met3 ;
        RECT 0.000 408.040 0.600 408.640 ;
    END
  END Tile_X0Y0_EE4END[10]
  PIN Tile_X0Y0_EE4END[11]
    DIRECTION INPUT ;
    USE SIGNAL ;
    ANTENNAGATEAREA 0.196500 ;
    PORT
      LAYER met3 ;
        RECT 0.000 409.400 0.600 410.000 ;
    END
  END Tile_X0Y0_EE4END[11]
  PIN Tile_X0Y0_EE4END[12]
    DIRECTION INPUT ;
    USE SIGNAL ;
    ANTENNAGATEAREA 0.126000 ;
    PORT
      LAYER met3 ;
        RECT 0.000 410.760 0.600 411.360 ;
    END
  END Tile_X0Y0_EE4END[12]
  PIN Tile_X0Y0_EE4END[13]
    DIRECTION INPUT ;
    USE SIGNAL ;
    ANTENNAGATEAREA 0.196500 ;
    PORT
      LAYER met3 ;
        RECT 0.000 412.120 0.600 412.720 ;
    END
  END Tile_X0Y0_EE4END[13]
  PIN Tile_X0Y0_EE4END[14]
    DIRECTION INPUT ;
    USE SIGNAL ;
    ANTENNAGATEAREA 0.196500 ;
    PORT
      LAYER met3 ;
        RECT 0.000 413.480 0.600 414.080 ;
    END
  END Tile_X0Y0_EE4END[14]
  PIN Tile_X0Y0_EE4END[15]
    DIRECTION INPUT ;
    USE SIGNAL ;
    ANTENNAGATEAREA 0.126000 ;
    PORT
      LAYER met3 ;
        RECT 0.000 414.840 0.600 415.440 ;
    END
  END Tile_X0Y0_EE4END[15]
  PIN Tile_X0Y0_EE4END[1]
    DIRECTION INPUT ;
    USE SIGNAL ;
    ANTENNAGATEAREA 0.196500 ;
    PORT
      LAYER met3 ;
        RECT 0.000 395.800 0.600 396.400 ;
    END
  END Tile_X0Y0_EE4END[1]
  PIN Tile_X0Y0_EE4END[2]
    DIRECTION INPUT ;
    USE SIGNAL ;
    ANTENNAGATEAREA 0.196500 ;
    PORT
      LAYER met3 ;
        RECT 0.000 397.160 0.600 397.760 ;
    END
  END Tile_X0Y0_EE4END[2]
  PIN Tile_X0Y0_EE4END[3]
    DIRECTION INPUT ;
    USE SIGNAL ;
    ANTENNAGATEAREA 0.196500 ;
    PORT
      LAYER met3 ;
        RECT 0.000 398.520 0.600 399.120 ;
    END
  END Tile_X0Y0_EE4END[3]
  PIN Tile_X0Y0_EE4END[4]
    DIRECTION INPUT ;
    USE SIGNAL ;
    ANTENNAGATEAREA 0.126000 ;
    PORT
      LAYER met3 ;
        RECT 0.000 399.880 0.600 400.480 ;
    END
  END Tile_X0Y0_EE4END[4]
  PIN Tile_X0Y0_EE4END[5]
    DIRECTION INPUT ;
    USE SIGNAL ;
    ANTENNAGATEAREA 0.196500 ;
    PORT
      LAYER met3 ;
        RECT 0.000 401.240 0.600 401.840 ;
    END
  END Tile_X0Y0_EE4END[5]
  PIN Tile_X0Y0_EE4END[6]
    DIRECTION INPUT ;
    USE SIGNAL ;
    ANTENNAGATEAREA 0.196500 ;
    PORT
      LAYER met3 ;
        RECT 0.000 402.600 0.600 403.200 ;
    END
  END Tile_X0Y0_EE4END[6]
  PIN Tile_X0Y0_EE4END[7]
    DIRECTION INPUT ;
    USE SIGNAL ;
    ANTENNAGATEAREA 0.196500 ;
    PORT
      LAYER met3 ;
        RECT 0.000 403.960 0.600 404.560 ;
    END
  END Tile_X0Y0_EE4END[7]
  PIN Tile_X0Y0_EE4END[8]
    DIRECTION INPUT ;
    USE SIGNAL ;
    ANTENNAGATEAREA 0.126000 ;
    PORT
      LAYER met3 ;
        RECT 0.000 405.320 0.600 405.920 ;
    END
  END Tile_X0Y0_EE4END[8]
  PIN Tile_X0Y0_EE4END[9]
    DIRECTION INPUT ;
    USE SIGNAL ;
    ANTENNAGATEAREA 0.196500 ;
    PORT
      LAYER met3 ;
        RECT 0.000 406.680 0.600 407.280 ;
    END
  END Tile_X0Y0_EE4END[9]
  PIN Tile_X0Y0_FrameData[0]
    DIRECTION INPUT ;
    USE SIGNAL ;
    ANTENNAGATEAREA 0.213000 ;
    PORT
      LAYER met3 ;
        RECT 0.000 432.520 0.600 433.120 ;
    END
  END Tile_X0Y0_FrameData[0]
  PIN Tile_X0Y0_FrameData[10]
    DIRECTION INPUT ;
    USE SIGNAL ;
    ANTENNAGATEAREA 0.213000 ;
    PORT
      LAYER met3 ;
        RECT 0.000 446.120 0.600 446.720 ;
    END
  END Tile_X0Y0_FrameData[10]
  PIN Tile_X0Y0_FrameData[11]
    DIRECTION INPUT ;
    USE SIGNAL ;
    ANTENNAGATEAREA 0.213000 ;
    PORT
      LAYER met3 ;
        RECT 0.000 447.480 0.600 448.080 ;
    END
  END Tile_X0Y0_FrameData[11]
  PIN Tile_X0Y0_FrameData[12]
    DIRECTION INPUT ;
    USE SIGNAL ;
    ANTENNAGATEAREA 0.247500 ;
    PORT
      LAYER met3 ;
        RECT 0.000 448.840 0.600 449.440 ;
    END
  END Tile_X0Y0_FrameData[12]
  PIN Tile_X0Y0_FrameData[13]
    DIRECTION INPUT ;
    USE SIGNAL ;
    ANTENNAGATEAREA 0.247500 ;
    PORT
      LAYER met3 ;
        RECT 0.000 450.200 0.600 450.800 ;
    END
  END Tile_X0Y0_FrameData[13]
  PIN Tile_X0Y0_FrameData[14]
    DIRECTION INPUT ;
    USE SIGNAL ;
    ANTENNAGATEAREA 0.247500 ;
    PORT
      LAYER met3 ;
        RECT 0.000 451.560 0.600 452.160 ;
    END
  END Tile_X0Y0_FrameData[14]
  PIN Tile_X0Y0_FrameData[15]
    DIRECTION INPUT ;
    USE SIGNAL ;
    ANTENNAGATEAREA 0.247500 ;
    PORT
      LAYER met3 ;
        RECT 0.000 452.920 0.600 453.520 ;
    END
  END Tile_X0Y0_FrameData[15]
  PIN Tile_X0Y0_FrameData[16]
    DIRECTION INPUT ;
    USE SIGNAL ;
    ANTENNAGATEAREA 0.247500 ;
    PORT
      LAYER met3 ;
        RECT 0.000 454.280 0.600 454.880 ;
    END
  END Tile_X0Y0_FrameData[16]
  PIN Tile_X0Y0_FrameData[17]
    DIRECTION INPUT ;
    USE SIGNAL ;
    ANTENNAGATEAREA 0.247500 ;
    PORT
      LAYER met3 ;
        RECT 0.000 455.640 0.600 456.240 ;
    END
  END Tile_X0Y0_FrameData[17]
  PIN Tile_X0Y0_FrameData[18]
    DIRECTION INPUT ;
    USE SIGNAL ;
    ANTENNAGATEAREA 0.213000 ;
    PORT
      LAYER met3 ;
        RECT 0.000 457.000 0.600 457.600 ;
    END
  END Tile_X0Y0_FrameData[18]
  PIN Tile_X0Y0_FrameData[19]
    DIRECTION INPUT ;
    USE SIGNAL ;
    ANTENNAGATEAREA 0.213000 ;
    PORT
      LAYER met3 ;
        RECT 0.000 458.360 0.600 458.960 ;
    END
  END Tile_X0Y0_FrameData[19]
  PIN Tile_X0Y0_FrameData[1]
    DIRECTION INPUT ;
    USE SIGNAL ;
    ANTENNAGATEAREA 0.213000 ;
    PORT
      LAYER met3 ;
        RECT 0.000 433.880 0.600 434.480 ;
    END
  END Tile_X0Y0_FrameData[1]
  PIN Tile_X0Y0_FrameData[20]
    DIRECTION INPUT ;
    USE SIGNAL ;
    ANTENNAGATEAREA 0.247500 ;
    PORT
      LAYER met3 ;
        RECT 0.000 459.720 0.600 460.320 ;
    END
  END Tile_X0Y0_FrameData[20]
  PIN Tile_X0Y0_FrameData[21]
    DIRECTION INPUT ;
    USE SIGNAL ;
    ANTENNAGATEAREA 0.213000 ;
    PORT
      LAYER met3 ;
        RECT 0.000 461.080 0.600 461.680 ;
    END
  END Tile_X0Y0_FrameData[21]
  PIN Tile_X0Y0_FrameData[22]
    DIRECTION INPUT ;
    USE SIGNAL ;
    ANTENNAGATEAREA 0.213000 ;
    PORT
      LAYER met3 ;
        RECT 0.000 462.440 0.600 463.040 ;
    END
  END Tile_X0Y0_FrameData[22]
  PIN Tile_X0Y0_FrameData[23]
    DIRECTION INPUT ;
    USE SIGNAL ;
    ANTENNAGATEAREA 0.213000 ;
    PORT
      LAYER met3 ;
        RECT 0.000 463.800 0.600 464.400 ;
    END
  END Tile_X0Y0_FrameData[23]
  PIN Tile_X0Y0_FrameData[24]
    DIRECTION INPUT ;
    USE SIGNAL ;
    ANTENNAGATEAREA 0.213000 ;
    PORT
      LAYER met3 ;
        RECT 0.000 465.160 0.600 465.760 ;
    END
  END Tile_X0Y0_FrameData[24]
  PIN Tile_X0Y0_FrameData[25]
    DIRECTION INPUT ;
    USE SIGNAL ;
    ANTENNAGATEAREA 0.213000 ;
    PORT
      LAYER met3 ;
        RECT 0.000 466.520 0.600 467.120 ;
    END
  END Tile_X0Y0_FrameData[25]
  PIN Tile_X0Y0_FrameData[26]
    DIRECTION INPUT ;
    USE SIGNAL ;
    ANTENNAGATEAREA 0.213000 ;
    PORT
      LAYER met3 ;
        RECT 0.000 467.880 0.600 468.480 ;
    END
  END Tile_X0Y0_FrameData[26]
  PIN Tile_X0Y0_FrameData[27]
    DIRECTION INPUT ;
    USE SIGNAL ;
    ANTENNAGATEAREA 0.213000 ;
    PORT
      LAYER met3 ;
        RECT 0.000 469.240 0.600 469.840 ;
    END
  END Tile_X0Y0_FrameData[27]
  PIN Tile_X0Y0_FrameData[28]
    DIRECTION INPUT ;
    USE SIGNAL ;
    ANTENNAGATEAREA 0.247500 ;
    PORT
      LAYER met3 ;
        RECT 0.000 470.600 0.600 471.200 ;
    END
  END Tile_X0Y0_FrameData[28]
  PIN Tile_X0Y0_FrameData[29]
    DIRECTION INPUT ;
    USE SIGNAL ;
    ANTENNAGATEAREA 0.247500 ;
    PORT
      LAYER met3 ;
        RECT 0.000 471.960 0.600 472.560 ;
    END
  END Tile_X0Y0_FrameData[29]
  PIN Tile_X0Y0_FrameData[2]
    DIRECTION INPUT ;
    USE SIGNAL ;
    ANTENNAGATEAREA 0.213000 ;
    PORT
      LAYER met3 ;
        RECT 0.000 435.240 0.600 435.840 ;
    END
  END Tile_X0Y0_FrameData[2]
  PIN Tile_X0Y0_FrameData[30]
    DIRECTION INPUT ;
    USE SIGNAL ;
    ANTENNAGATEAREA 0.213000 ;
    PORT
      LAYER met3 ;
        RECT 0.000 473.320 0.600 473.920 ;
    END
  END Tile_X0Y0_FrameData[30]
  PIN Tile_X0Y0_FrameData[31]
    DIRECTION INPUT ;
    USE SIGNAL ;
    ANTENNAGATEAREA 0.213000 ;
    PORT
      LAYER met3 ;
        RECT 0.000 474.680 0.600 475.280 ;
    END
  END Tile_X0Y0_FrameData[31]
  PIN Tile_X0Y0_FrameData[3]
    DIRECTION INPUT ;
    USE SIGNAL ;
    ANTENNAGATEAREA 0.213000 ;
    PORT
      LAYER met3 ;
        RECT 0.000 436.600 0.600 437.200 ;
    END
  END Tile_X0Y0_FrameData[3]
  PIN Tile_X0Y0_FrameData[4]
    DIRECTION INPUT ;
    USE SIGNAL ;
    ANTENNAGATEAREA 0.213000 ;
    PORT
      LAYER met3 ;
        RECT 0.000 437.960 0.600 438.560 ;
    END
  END Tile_X0Y0_FrameData[4]
  PIN Tile_X0Y0_FrameData[5]
    DIRECTION INPUT ;
    USE SIGNAL ;
    ANTENNAGATEAREA 0.213000 ;
    PORT
      LAYER met3 ;
        RECT 0.000 439.320 0.600 439.920 ;
    END
  END Tile_X0Y0_FrameData[5]
  PIN Tile_X0Y0_FrameData[6]
    DIRECTION INPUT ;
    USE SIGNAL ;
    ANTENNAGATEAREA 0.159000 ;
    PORT
      LAYER met3 ;
        RECT 0.000 440.680 0.600 441.280 ;
    END
  END Tile_X0Y0_FrameData[6]
  PIN Tile_X0Y0_FrameData[7]
    DIRECTION INPUT ;
    USE SIGNAL ;
    ANTENNAGATEAREA 0.159000 ;
    PORT
      LAYER met3 ;
        RECT 0.000 442.040 0.600 442.640 ;
    END
  END Tile_X0Y0_FrameData[7]
  PIN Tile_X0Y0_FrameData[8]
    DIRECTION INPUT ;
    USE SIGNAL ;
    ANTENNAGATEAREA 0.213000 ;
    PORT
      LAYER met3 ;
        RECT 0.000 443.400 0.600 444.000 ;
    END
  END Tile_X0Y0_FrameData[8]
  PIN Tile_X0Y0_FrameData[9]
    DIRECTION INPUT ;
    USE SIGNAL ;
    ANTENNAGATEAREA 0.213000 ;
    PORT
      LAYER met3 ;
        RECT 0.000 444.760 0.600 445.360 ;
    END
  END Tile_X0Y0_FrameData[9]
  PIN Tile_X0Y0_FrameData_O[0]
    DIRECTION OUTPUT ;
    USE SIGNAL ;
    ANTENNADIFFAREA 0.445500 ;
    PORT
      LAYER met3 ;
        RECT 119.460 338.680 120.060 339.280 ;
    END
  END Tile_X0Y0_FrameData_O[0]
  PIN Tile_X0Y0_FrameData_O[10]
    DIRECTION OUTPUT ;
    USE SIGNAL ;
    ANTENNADIFFAREA 0.445500 ;
    PORT
      LAYER met3 ;
        RECT 119.460 365.880 120.060 366.480 ;
    END
  END Tile_X0Y0_FrameData_O[10]
  PIN Tile_X0Y0_FrameData_O[11]
    DIRECTION OUTPUT ;
    USE SIGNAL ;
    ANTENNADIFFAREA 0.445500 ;
    PORT
      LAYER met3 ;
        RECT 119.460 368.600 120.060 369.200 ;
    END
  END Tile_X0Y0_FrameData_O[11]
  PIN Tile_X0Y0_FrameData_O[12]
    DIRECTION OUTPUT ;
    USE SIGNAL ;
    ANTENNADIFFAREA 0.445500 ;
    PORT
      LAYER met3 ;
        RECT 119.460 371.320 120.060 371.920 ;
    END
  END Tile_X0Y0_FrameData_O[12]
  PIN Tile_X0Y0_FrameData_O[13]
    DIRECTION OUTPUT ;
    USE SIGNAL ;
    ANTENNADIFFAREA 0.445500 ;
    PORT
      LAYER met3 ;
        RECT 119.460 374.040 120.060 374.640 ;
    END
  END Tile_X0Y0_FrameData_O[13]
  PIN Tile_X0Y0_FrameData_O[14]
    DIRECTION OUTPUT ;
    USE SIGNAL ;
    ANTENNADIFFAREA 0.445500 ;
    PORT
      LAYER met3 ;
        RECT 119.460 376.760 120.060 377.360 ;
    END
  END Tile_X0Y0_FrameData_O[14]
  PIN Tile_X0Y0_FrameData_O[15]
    DIRECTION OUTPUT ;
    USE SIGNAL ;
    ANTENNADIFFAREA 0.445500 ;
    PORT
      LAYER met3 ;
        RECT 119.460 379.480 120.060 380.080 ;
    END
  END Tile_X0Y0_FrameData_O[15]
  PIN Tile_X0Y0_FrameData_O[16]
    DIRECTION OUTPUT ;
    USE SIGNAL ;
    ANTENNADIFFAREA 0.445500 ;
    PORT
      LAYER met3 ;
        RECT 119.460 382.200 120.060 382.800 ;
    END
  END Tile_X0Y0_FrameData_O[16]
  PIN Tile_X0Y0_FrameData_O[17]
    DIRECTION OUTPUT ;
    USE SIGNAL ;
    ANTENNADIFFAREA 0.445500 ;
    PORT
      LAYER met3 ;
        RECT 119.460 384.920 120.060 385.520 ;
    END
  END Tile_X0Y0_FrameData_O[17]
  PIN Tile_X0Y0_FrameData_O[18]
    DIRECTION OUTPUT ;
    USE SIGNAL ;
    ANTENNADIFFAREA 0.445500 ;
    PORT
      LAYER met3 ;
        RECT 119.460 387.640 120.060 388.240 ;
    END
  END Tile_X0Y0_FrameData_O[18]
  PIN Tile_X0Y0_FrameData_O[19]
    DIRECTION OUTPUT ;
    USE SIGNAL ;
    ANTENNADIFFAREA 0.445500 ;
    PORT
      LAYER met3 ;
        RECT 119.460 390.360 120.060 390.960 ;
    END
  END Tile_X0Y0_FrameData_O[19]
  PIN Tile_X0Y0_FrameData_O[1]
    DIRECTION OUTPUT ;
    USE SIGNAL ;
    ANTENNADIFFAREA 0.445500 ;
    PORT
      LAYER met3 ;
        RECT 119.460 341.400 120.060 342.000 ;
    END
  END Tile_X0Y0_FrameData_O[1]
  PIN Tile_X0Y0_FrameData_O[20]
    DIRECTION OUTPUT ;
    USE SIGNAL ;
    ANTENNADIFFAREA 0.445500 ;
    PORT
      LAYER met3 ;
        RECT 119.460 393.080 120.060 393.680 ;
    END
  END Tile_X0Y0_FrameData_O[20]
  PIN Tile_X0Y0_FrameData_O[21]
    DIRECTION OUTPUT ;
    USE SIGNAL ;
    ANTENNADIFFAREA 0.445500 ;
    PORT
      LAYER met3 ;
        RECT 119.460 395.800 120.060 396.400 ;
    END
  END Tile_X0Y0_FrameData_O[21]
  PIN Tile_X0Y0_FrameData_O[22]
    DIRECTION OUTPUT ;
    USE SIGNAL ;
    ANTENNADIFFAREA 0.445500 ;
    PORT
      LAYER met3 ;
        RECT 119.460 398.520 120.060 399.120 ;
    END
  END Tile_X0Y0_FrameData_O[22]
  PIN Tile_X0Y0_FrameData_O[23]
    DIRECTION OUTPUT ;
    USE SIGNAL ;
    ANTENNADIFFAREA 0.445500 ;
    PORT
      LAYER met3 ;
        RECT 119.460 401.240 120.060 401.840 ;
    END
  END Tile_X0Y0_FrameData_O[23]
  PIN Tile_X0Y0_FrameData_O[24]
    DIRECTION OUTPUT ;
    USE SIGNAL ;
    ANTENNADIFFAREA 0.445500 ;
    PORT
      LAYER met3 ;
        RECT 119.460 403.960 120.060 404.560 ;
    END
  END Tile_X0Y0_FrameData_O[24]
  PIN Tile_X0Y0_FrameData_O[25]
    DIRECTION OUTPUT ;
    USE SIGNAL ;
    ANTENNADIFFAREA 0.445500 ;
    PORT
      LAYER met3 ;
        RECT 119.460 406.680 120.060 407.280 ;
    END
  END Tile_X0Y0_FrameData_O[25]
  PIN Tile_X0Y0_FrameData_O[26]
    DIRECTION OUTPUT ;
    USE SIGNAL ;
    ANTENNADIFFAREA 0.445500 ;
    PORT
      LAYER met3 ;
        RECT 119.460 409.400 120.060 410.000 ;
    END
  END Tile_X0Y0_FrameData_O[26]
  PIN Tile_X0Y0_FrameData_O[27]
    DIRECTION OUTPUT ;
    USE SIGNAL ;
    ANTENNADIFFAREA 0.445500 ;
    PORT
      LAYER met3 ;
        RECT 119.460 412.120 120.060 412.720 ;
    END
  END Tile_X0Y0_FrameData_O[27]
  PIN Tile_X0Y0_FrameData_O[28]
    DIRECTION OUTPUT ;
    USE SIGNAL ;
    ANTENNADIFFAREA 0.445500 ;
    PORT
      LAYER met3 ;
        RECT 119.460 414.840 120.060 415.440 ;
    END
  END Tile_X0Y0_FrameData_O[28]
  PIN Tile_X0Y0_FrameData_O[29]
    DIRECTION OUTPUT ;
    USE SIGNAL ;
    ANTENNADIFFAREA 0.445500 ;
    PORT
      LAYER met3 ;
        RECT 119.460 417.560 120.060 418.160 ;
    END
  END Tile_X0Y0_FrameData_O[29]
  PIN Tile_X0Y0_FrameData_O[2]
    DIRECTION OUTPUT ;
    USE SIGNAL ;
    ANTENNADIFFAREA 0.445500 ;
    PORT
      LAYER met3 ;
        RECT 119.460 344.120 120.060 344.720 ;
    END
  END Tile_X0Y0_FrameData_O[2]
  PIN Tile_X0Y0_FrameData_O[30]
    DIRECTION OUTPUT ;
    USE SIGNAL ;
    ANTENNADIFFAREA 0.445500 ;
    PORT
      LAYER met3 ;
        RECT 119.460 420.280 120.060 420.880 ;
    END
  END Tile_X0Y0_FrameData_O[30]
  PIN Tile_X0Y0_FrameData_O[31]
    DIRECTION OUTPUT ;
    USE SIGNAL ;
    ANTENNADIFFAREA 0.445500 ;
    PORT
      LAYER met3 ;
        RECT 119.460 423.000 120.060 423.600 ;
    END
  END Tile_X0Y0_FrameData_O[31]
  PIN Tile_X0Y0_FrameData_O[3]
    DIRECTION OUTPUT ;
    USE SIGNAL ;
    ANTENNADIFFAREA 0.445500 ;
    PORT
      LAYER met3 ;
        RECT 119.460 346.840 120.060 347.440 ;
    END
  END Tile_X0Y0_FrameData_O[3]
  PIN Tile_X0Y0_FrameData_O[4]
    DIRECTION OUTPUT ;
    USE SIGNAL ;
    ANTENNADIFFAREA 0.445500 ;
    PORT
      LAYER met3 ;
        RECT 119.460 349.560 120.060 350.160 ;
    END
  END Tile_X0Y0_FrameData_O[4]
  PIN Tile_X0Y0_FrameData_O[5]
    DIRECTION OUTPUT ;
    USE SIGNAL ;
    ANTENNADIFFAREA 0.445500 ;
    PORT
      LAYER met3 ;
        RECT 119.460 352.280 120.060 352.880 ;
    END
  END Tile_X0Y0_FrameData_O[5]
  PIN Tile_X0Y0_FrameData_O[6]
    DIRECTION OUTPUT ;
    USE SIGNAL ;
    ANTENNADIFFAREA 0.445500 ;
    PORT
      LAYER met3 ;
        RECT 119.460 355.000 120.060 355.600 ;
    END
  END Tile_X0Y0_FrameData_O[6]
  PIN Tile_X0Y0_FrameData_O[7]
    DIRECTION OUTPUT ;
    USE SIGNAL ;
    ANTENNADIFFAREA 0.445500 ;
    PORT
      LAYER met3 ;
        RECT 119.460 357.720 120.060 358.320 ;
    END
  END Tile_X0Y0_FrameData_O[7]
  PIN Tile_X0Y0_FrameData_O[8]
    DIRECTION OUTPUT ;
    USE SIGNAL ;
    ANTENNADIFFAREA 0.445500 ;
    PORT
      LAYER met3 ;
        RECT 119.460 360.440 120.060 361.040 ;
    END
  END Tile_X0Y0_FrameData_O[8]
  PIN Tile_X0Y0_FrameData_O[9]
    DIRECTION OUTPUT ;
    USE SIGNAL ;
    ANTENNADIFFAREA 0.445500 ;
    PORT
      LAYER met3 ;
        RECT 119.460 363.160 120.060 363.760 ;
    END
  END Tile_X0Y0_FrameData_O[9]
  PIN Tile_X0Y0_FrameStrobe_O[0]
    DIRECTION OUTPUT ;
    USE SIGNAL ;
    ANTENNADIFFAREA 0.445500 ;
    PORT
      LAYER met2 ;
        RECT 84.730 519.240 85.010 519.520 ;
    END
  END Tile_X0Y0_FrameStrobe_O[0]
  PIN Tile_X0Y0_FrameStrobe_O[10]
    DIRECTION OUTPUT ;
    USE SIGNAL ;
    ANTENNADIFFAREA 0.445500 ;
    PORT
      LAYER met2 ;
        RECT 93.930 519.240 94.210 519.520 ;
    END
  END Tile_X0Y0_FrameStrobe_O[10]
  PIN Tile_X0Y0_FrameStrobe_O[11]
    DIRECTION OUTPUT ;
    USE SIGNAL ;
    ANTENNADIFFAREA 0.445500 ;
    PORT
      LAYER met2 ;
        RECT 94.850 519.240 95.130 519.520 ;
    END
  END Tile_X0Y0_FrameStrobe_O[11]
  PIN Tile_X0Y0_FrameStrobe_O[12]
    DIRECTION OUTPUT ;
    USE SIGNAL ;
    ANTENNADIFFAREA 0.445500 ;
    PORT
      LAYER met2 ;
        RECT 95.770 519.240 96.050 519.520 ;
    END
  END Tile_X0Y0_FrameStrobe_O[12]
  PIN Tile_X0Y0_FrameStrobe_O[13]
    DIRECTION OUTPUT ;
    USE SIGNAL ;
    ANTENNADIFFAREA 0.445500 ;
    PORT
      LAYER met2 ;
        RECT 96.690 519.240 96.970 519.520 ;
    END
  END Tile_X0Y0_FrameStrobe_O[13]
  PIN Tile_X0Y0_FrameStrobe_O[14]
    DIRECTION OUTPUT ;
    USE SIGNAL ;
    ANTENNADIFFAREA 0.445500 ;
    PORT
      LAYER met2 ;
        RECT 97.610 519.240 97.890 519.520 ;
    END
  END Tile_X0Y0_FrameStrobe_O[14]
  PIN Tile_X0Y0_FrameStrobe_O[15]
    DIRECTION OUTPUT ;
    USE SIGNAL ;
    ANTENNADIFFAREA 0.445500 ;
    PORT
      LAYER met2 ;
        RECT 98.530 519.240 98.810 519.520 ;
    END
  END Tile_X0Y0_FrameStrobe_O[15]
  PIN Tile_X0Y0_FrameStrobe_O[16]
    DIRECTION OUTPUT ;
    USE SIGNAL ;
    ANTENNADIFFAREA 0.445500 ;
    PORT
      LAYER met2 ;
        RECT 99.450 519.240 99.730 519.520 ;
    END
  END Tile_X0Y0_FrameStrobe_O[16]
  PIN Tile_X0Y0_FrameStrobe_O[17]
    DIRECTION OUTPUT ;
    USE SIGNAL ;
    ANTENNADIFFAREA 0.445500 ;
    PORT
      LAYER met2 ;
        RECT 100.370 519.240 100.650 519.520 ;
    END
  END Tile_X0Y0_FrameStrobe_O[17]
  PIN Tile_X0Y0_FrameStrobe_O[18]
    DIRECTION OUTPUT ;
    USE SIGNAL ;
    ANTENNADIFFAREA 0.445500 ;
    PORT
      LAYER met2 ;
        RECT 101.290 519.240 101.570 519.520 ;
    END
  END Tile_X0Y0_FrameStrobe_O[18]
  PIN Tile_X0Y0_FrameStrobe_O[19]
    DIRECTION OUTPUT ;
    USE SIGNAL ;
    ANTENNADIFFAREA 0.445500 ;
    PORT
      LAYER met2 ;
        RECT 102.210 519.240 102.490 519.520 ;
    END
  END Tile_X0Y0_FrameStrobe_O[19]
  PIN Tile_X0Y0_FrameStrobe_O[1]
    DIRECTION OUTPUT ;
    USE SIGNAL ;
    ANTENNADIFFAREA 0.445500 ;
    PORT
      LAYER met2 ;
        RECT 85.650 519.240 85.930 519.520 ;
    END
  END Tile_X0Y0_FrameStrobe_O[1]
  PIN Tile_X0Y0_FrameStrobe_O[2]
    DIRECTION OUTPUT ;
    USE SIGNAL ;
    ANTENNADIFFAREA 0.445500 ;
    PORT
      LAYER met2 ;
        RECT 86.570 519.240 86.850 519.520 ;
    END
  END Tile_X0Y0_FrameStrobe_O[2]
  PIN Tile_X0Y0_FrameStrobe_O[3]
    DIRECTION OUTPUT ;
    USE SIGNAL ;
    ANTENNADIFFAREA 0.445500 ;
    PORT
      LAYER met2 ;
        RECT 87.490 519.240 87.770 519.520 ;
    END
  END Tile_X0Y0_FrameStrobe_O[3]
  PIN Tile_X0Y0_FrameStrobe_O[4]
    DIRECTION OUTPUT ;
    USE SIGNAL ;
    ANTENNADIFFAREA 0.445500 ;
    PORT
      LAYER met2 ;
        RECT 88.410 519.240 88.690 519.520 ;
    END
  END Tile_X0Y0_FrameStrobe_O[4]
  PIN Tile_X0Y0_FrameStrobe_O[5]
    DIRECTION OUTPUT ;
    USE SIGNAL ;
    ANTENNADIFFAREA 0.445500 ;
    PORT
      LAYER met2 ;
        RECT 89.330 519.240 89.610 519.520 ;
    END
  END Tile_X0Y0_FrameStrobe_O[5]
  PIN Tile_X0Y0_FrameStrobe_O[6]
    DIRECTION OUTPUT ;
    USE SIGNAL ;
    ANTENNADIFFAREA 0.445500 ;
    PORT
      LAYER met2 ;
        RECT 90.250 519.240 90.530 519.520 ;
    END
  END Tile_X0Y0_FrameStrobe_O[6]
  PIN Tile_X0Y0_FrameStrobe_O[7]
    DIRECTION OUTPUT ;
    USE SIGNAL ;
    ANTENNADIFFAREA 0.445500 ;
    PORT
      LAYER met2 ;
        RECT 91.170 519.240 91.450 519.520 ;
    END
  END Tile_X0Y0_FrameStrobe_O[7]
  PIN Tile_X0Y0_FrameStrobe_O[8]
    DIRECTION OUTPUT ;
    USE SIGNAL ;
    ANTENNADIFFAREA 0.445500 ;
    PORT
      LAYER met2 ;
        RECT 92.090 519.240 92.370 519.520 ;
    END
  END Tile_X0Y0_FrameStrobe_O[8]
  PIN Tile_X0Y0_FrameStrobe_O[9]
    DIRECTION OUTPUT ;
    USE SIGNAL ;
    ANTENNADIFFAREA 0.445500 ;
    PORT
      LAYER met2 ;
        RECT 93.010 519.240 93.290 519.520 ;
    END
  END Tile_X0Y0_FrameStrobe_O[9]
  PIN Tile_X0Y0_N1BEG[0]
    DIRECTION OUTPUT ;
    USE SIGNAL ;
    ANTENNADIFFAREA 0.445500 ;
    PORT
      LAYER met2 ;
        RECT 17.570 519.240 17.850 519.520 ;
    END
  END Tile_X0Y0_N1BEG[0]
  PIN Tile_X0Y0_N1BEG[1]
    DIRECTION OUTPUT ;
    USE SIGNAL ;
    ANTENNADIFFAREA 0.445500 ;
    PORT
      LAYER met2 ;
        RECT 18.490 519.240 18.770 519.520 ;
    END
  END Tile_X0Y0_N1BEG[1]
  PIN Tile_X0Y0_N1BEG[2]
    DIRECTION OUTPUT ;
    USE SIGNAL ;
    ANTENNADIFFAREA 0.445500 ;
    PORT
      LAYER met2 ;
        RECT 19.410 519.240 19.690 519.520 ;
    END
  END Tile_X0Y0_N1BEG[2]
  PIN Tile_X0Y0_N1BEG[3]
    DIRECTION OUTPUT ;
    USE SIGNAL ;
    ANTENNADIFFAREA 0.445500 ;
    PORT
      LAYER met2 ;
        RECT 20.330 519.240 20.610 519.520 ;
    END
  END Tile_X0Y0_N1BEG[3]
  PIN Tile_X0Y0_N2BEG[0]
    DIRECTION OUTPUT ;
    USE SIGNAL ;
    ANTENNADIFFAREA 0.445500 ;
    PORT
      LAYER met2 ;
        RECT 21.250 519.240 21.530 519.520 ;
    END
  END Tile_X0Y0_N2BEG[0]
  PIN Tile_X0Y0_N2BEG[1]
    DIRECTION OUTPUT ;
    USE SIGNAL ;
    ANTENNADIFFAREA 0.445500 ;
    PORT
      LAYER met2 ;
        RECT 22.170 519.240 22.450 519.520 ;
    END
  END Tile_X0Y0_N2BEG[1]
  PIN Tile_X0Y0_N2BEG[2]
    DIRECTION OUTPUT ;
    USE SIGNAL ;
    ANTENNADIFFAREA 0.445500 ;
    PORT
      LAYER met2 ;
        RECT 23.090 519.240 23.370 519.520 ;
    END
  END Tile_X0Y0_N2BEG[2]
  PIN Tile_X0Y0_N2BEG[3]
    DIRECTION OUTPUT ;
    USE SIGNAL ;
    ANTENNADIFFAREA 0.445500 ;
    PORT
      LAYER met2 ;
        RECT 24.010 519.240 24.290 519.520 ;
    END
  END Tile_X0Y0_N2BEG[3]
  PIN Tile_X0Y0_N2BEG[4]
    DIRECTION OUTPUT ;
    USE SIGNAL ;
    ANTENNADIFFAREA 0.445500 ;
    PORT
      LAYER met2 ;
        RECT 24.930 519.240 25.210 519.520 ;
    END
  END Tile_X0Y0_N2BEG[4]
  PIN Tile_X0Y0_N2BEG[5]
    DIRECTION OUTPUT ;
    USE SIGNAL ;
    ANTENNADIFFAREA 0.445500 ;
    PORT
      LAYER met2 ;
        RECT 25.850 519.240 26.130 519.520 ;
    END
  END Tile_X0Y0_N2BEG[5]
  PIN Tile_X0Y0_N2BEG[6]
    DIRECTION OUTPUT ;
    USE SIGNAL ;
    ANTENNADIFFAREA 0.445500 ;
    PORT
      LAYER met2 ;
        RECT 26.770 519.240 27.050 519.520 ;
    END
  END Tile_X0Y0_N2BEG[6]
  PIN Tile_X0Y0_N2BEG[7]
    DIRECTION OUTPUT ;
    USE SIGNAL ;
    ANTENNADIFFAREA 0.445500 ;
    PORT
      LAYER met2 ;
        RECT 27.690 519.240 27.970 519.520 ;
    END
  END Tile_X0Y0_N2BEG[7]
  PIN Tile_X0Y0_N2BEGb[0]
    DIRECTION OUTPUT ;
    USE SIGNAL ;
    ANTENNADIFFAREA 0.445500 ;
    PORT
      LAYER met2 ;
        RECT 28.610 519.240 28.890 519.520 ;
    END
  END Tile_X0Y0_N2BEGb[0]
  PIN Tile_X0Y0_N2BEGb[1]
    DIRECTION OUTPUT ;
    USE SIGNAL ;
    ANTENNADIFFAREA 0.445500 ;
    PORT
      LAYER met2 ;
        RECT 29.530 519.240 29.810 519.520 ;
    END
  END Tile_X0Y0_N2BEGb[1]
  PIN Tile_X0Y0_N2BEGb[2]
    DIRECTION OUTPUT ;
    USE SIGNAL ;
    ANTENNADIFFAREA 0.445500 ;
    PORT
      LAYER met2 ;
        RECT 30.450 519.240 30.730 519.520 ;
    END
  END Tile_X0Y0_N2BEGb[2]
  PIN Tile_X0Y0_N2BEGb[3]
    DIRECTION OUTPUT ;
    USE SIGNAL ;
    ANTENNADIFFAREA 0.445500 ;
    PORT
      LAYER met2 ;
        RECT 31.370 519.240 31.650 519.520 ;
    END
  END Tile_X0Y0_N2BEGb[3]
  PIN Tile_X0Y0_N2BEGb[4]
    DIRECTION OUTPUT ;
    USE SIGNAL ;
    ANTENNADIFFAREA 0.445500 ;
    PORT
      LAYER met2 ;
        RECT 32.290 519.240 32.570 519.520 ;
    END
  END Tile_X0Y0_N2BEGb[4]
  PIN Tile_X0Y0_N2BEGb[5]
    DIRECTION OUTPUT ;
    USE SIGNAL ;
    ANTENNADIFFAREA 0.445500 ;
    PORT
      LAYER met2 ;
        RECT 33.210 519.240 33.490 519.520 ;
    END
  END Tile_X0Y0_N2BEGb[5]
  PIN Tile_X0Y0_N2BEGb[6]
    DIRECTION OUTPUT ;
    USE SIGNAL ;
    ANTENNADIFFAREA 0.445500 ;
    PORT
      LAYER met2 ;
        RECT 34.130 519.240 34.410 519.520 ;
    END
  END Tile_X0Y0_N2BEGb[6]
  PIN Tile_X0Y0_N2BEGb[7]
    DIRECTION OUTPUT ;
    USE SIGNAL ;
    ANTENNADIFFAREA 0.445500 ;
    PORT
      LAYER met2 ;
        RECT 35.050 519.240 35.330 519.520 ;
    END
  END Tile_X0Y0_N2BEGb[7]
  PIN Tile_X0Y0_N4BEG[0]
    DIRECTION OUTPUT ;
    USE SIGNAL ;
    ANTENNADIFFAREA 0.445500 ;
    PORT
      LAYER met2 ;
        RECT 35.970 519.240 36.250 519.520 ;
    END
  END Tile_X0Y0_N4BEG[0]
  PIN Tile_X0Y0_N4BEG[10]
    DIRECTION OUTPUT ;
    USE SIGNAL ;
    ANTENNADIFFAREA 0.445500 ;
    PORT
      LAYER met2 ;
        RECT 45.170 519.240 45.450 519.520 ;
    END
  END Tile_X0Y0_N4BEG[10]
  PIN Tile_X0Y0_N4BEG[11]
    DIRECTION OUTPUT ;
    USE SIGNAL ;
    ANTENNADIFFAREA 0.445500 ;
    PORT
      LAYER met2 ;
        RECT 46.090 519.240 46.370 519.520 ;
    END
  END Tile_X0Y0_N4BEG[11]
  PIN Tile_X0Y0_N4BEG[12]
    DIRECTION OUTPUT ;
    USE SIGNAL ;
    ANTENNADIFFAREA 0.445500 ;
    PORT
      LAYER met2 ;
        RECT 47.010 519.240 47.290 519.520 ;
    END
  END Tile_X0Y0_N4BEG[12]
  PIN Tile_X0Y0_N4BEG[13]
    DIRECTION OUTPUT ;
    USE SIGNAL ;
    ANTENNADIFFAREA 0.445500 ;
    PORT
      LAYER met2 ;
        RECT 47.930 519.240 48.210 519.520 ;
    END
  END Tile_X0Y0_N4BEG[13]
  PIN Tile_X0Y0_N4BEG[14]
    DIRECTION OUTPUT ;
    USE SIGNAL ;
    ANTENNADIFFAREA 0.445500 ;
    PORT
      LAYER met2 ;
        RECT 48.850 519.240 49.130 519.520 ;
    END
  END Tile_X0Y0_N4BEG[14]
  PIN Tile_X0Y0_N4BEG[15]
    DIRECTION OUTPUT ;
    USE SIGNAL ;
    ANTENNADIFFAREA 0.445500 ;
    PORT
      LAYER met2 ;
        RECT 49.770 519.240 50.050 519.520 ;
    END
  END Tile_X0Y0_N4BEG[15]
  PIN Tile_X0Y0_N4BEG[1]
    DIRECTION OUTPUT ;
    USE SIGNAL ;
    ANTENNADIFFAREA 0.445500 ;
    PORT
      LAYER met2 ;
        RECT 36.890 519.240 37.170 519.520 ;
    END
  END Tile_X0Y0_N4BEG[1]
  PIN Tile_X0Y0_N4BEG[2]
    DIRECTION OUTPUT ;
    USE SIGNAL ;
    ANTENNADIFFAREA 0.445500 ;
    PORT
      LAYER met2 ;
        RECT 37.810 519.240 38.090 519.520 ;
    END
  END Tile_X0Y0_N4BEG[2]
  PIN Tile_X0Y0_N4BEG[3]
    DIRECTION OUTPUT ;
    USE SIGNAL ;
    ANTENNADIFFAREA 0.445500 ;
    PORT
      LAYER met2 ;
        RECT 38.730 519.240 39.010 519.520 ;
    END
  END Tile_X0Y0_N4BEG[3]
  PIN Tile_X0Y0_N4BEG[4]
    DIRECTION OUTPUT ;
    USE SIGNAL ;
    ANTENNADIFFAREA 0.445500 ;
    PORT
      LAYER met2 ;
        RECT 39.650 519.240 39.930 519.520 ;
    END
  END Tile_X0Y0_N4BEG[4]
  PIN Tile_X0Y0_N4BEG[5]
    DIRECTION OUTPUT ;
    USE SIGNAL ;
    ANTENNADIFFAREA 0.445500 ;
    PORT
      LAYER met2 ;
        RECT 40.570 519.240 40.850 519.520 ;
    END
  END Tile_X0Y0_N4BEG[5]
  PIN Tile_X0Y0_N4BEG[6]
    DIRECTION OUTPUT ;
    USE SIGNAL ;
    ANTENNADIFFAREA 0.445500 ;
    PORT
      LAYER met2 ;
        RECT 41.490 519.240 41.770 519.520 ;
    END
  END Tile_X0Y0_N4BEG[6]
  PIN Tile_X0Y0_N4BEG[7]
    DIRECTION OUTPUT ;
    USE SIGNAL ;
    ANTENNADIFFAREA 0.445500 ;
    PORT
      LAYER met2 ;
        RECT 42.410 519.240 42.690 519.520 ;
    END
  END Tile_X0Y0_N4BEG[7]
  PIN Tile_X0Y0_N4BEG[8]
    DIRECTION OUTPUT ;
    USE SIGNAL ;
    ANTENNADIFFAREA 0.445500 ;
    PORT
      LAYER met2 ;
        RECT 43.330 519.240 43.610 519.520 ;
    END
  END Tile_X0Y0_N4BEG[8]
  PIN Tile_X0Y0_N4BEG[9]
    DIRECTION OUTPUT ;
    USE SIGNAL ;
    ANTENNADIFFAREA 0.445500 ;
    PORT
      LAYER met2 ;
        RECT 44.250 519.240 44.530 519.520 ;
    END
  END Tile_X0Y0_N4BEG[9]
  PIN Tile_X0Y0_S1END[0]
    DIRECTION INPUT ;
    USE SIGNAL ;
    ANTENNAGATEAREA 0.159000 ;
    PORT
      LAYER met2 ;
        RECT 50.690 519.240 50.970 519.520 ;
    END
  END Tile_X0Y0_S1END[0]
  PIN Tile_X0Y0_S1END[1]
    DIRECTION INPUT ;
    USE SIGNAL ;
    ANTENNAGATEAREA 0.159000 ;
    PORT
      LAYER met2 ;
        RECT 51.610 519.240 51.890 519.520 ;
    END
  END Tile_X0Y0_S1END[1]
  PIN Tile_X0Y0_S1END[2]
    DIRECTION INPUT ;
    USE SIGNAL ;
    ANTENNAGATEAREA 0.159000 ;
    PORT
      LAYER met2 ;
        RECT 52.530 519.240 52.810 519.520 ;
    END
  END Tile_X0Y0_S1END[2]
  PIN Tile_X0Y0_S1END[3]
    DIRECTION INPUT ;
    USE SIGNAL ;
    ANTENNAGATEAREA 0.159000 ;
    PORT
      LAYER met2 ;
        RECT 53.450 519.240 53.730 519.520 ;
    END
  END Tile_X0Y0_S1END[3]
  PIN Tile_X0Y0_S2END[0]
    DIRECTION INPUT ;
    USE SIGNAL ;
    ANTENNAGATEAREA 0.213000 ;
    PORT
      LAYER met2 ;
        RECT 61.730 519.240 62.010 519.520 ;
    END
  END Tile_X0Y0_S2END[0]
  PIN Tile_X0Y0_S2END[1]
    DIRECTION INPUT ;
    USE SIGNAL ;
    ANTENNAGATEAREA 0.213000 ;
    PORT
      LAYER met2 ;
        RECT 62.650 519.240 62.930 519.520 ;
    END
  END Tile_X0Y0_S2END[1]
  PIN Tile_X0Y0_S2END[2]
    DIRECTION INPUT ;
    USE SIGNAL ;
    ANTENNAGATEAREA 0.213000 ;
    PORT
      LAYER met2 ;
        RECT 63.570 519.240 63.850 519.520 ;
    END
  END Tile_X0Y0_S2END[2]
  PIN Tile_X0Y0_S2END[3]
    DIRECTION INPUT ;
    USE SIGNAL ;
    ANTENNAGATEAREA 0.213000 ;
    PORT
      LAYER met2 ;
        RECT 64.490 519.240 64.770 519.520 ;
    END
  END Tile_X0Y0_S2END[3]
  PIN Tile_X0Y0_S2END[4]
    DIRECTION INPUT ;
    USE SIGNAL ;
    ANTENNAGATEAREA 0.213000 ;
    PORT
      LAYER met2 ;
        RECT 65.410 519.240 65.690 519.520 ;
    END
  END Tile_X0Y0_S2END[4]
  PIN Tile_X0Y0_S2END[5]
    DIRECTION INPUT ;
    USE SIGNAL ;
    ANTENNAGATEAREA 0.213000 ;
    PORT
      LAYER met2 ;
        RECT 66.330 519.240 66.610 519.520 ;
    END
  END Tile_X0Y0_S2END[5]
  PIN Tile_X0Y0_S2END[6]
    DIRECTION INPUT ;
    USE SIGNAL ;
    ANTENNAGATEAREA 0.213000 ;
    PORT
      LAYER met2 ;
        RECT 67.250 519.240 67.530 519.520 ;
    END
  END Tile_X0Y0_S2END[6]
  PIN Tile_X0Y0_S2END[7]
    DIRECTION INPUT ;
    USE SIGNAL ;
    ANTENNAGATEAREA 0.213000 ;
    PORT
      LAYER met2 ;
        RECT 68.170 519.240 68.450 519.520 ;
    END
  END Tile_X0Y0_S2END[7]
  PIN Tile_X0Y0_S2MID[0]
    DIRECTION INPUT ;
    USE SIGNAL ;
    ANTENNAGATEAREA 0.213000 ;
    PORT
      LAYER met2 ;
        RECT 54.370 519.240 54.650 519.520 ;
    END
  END Tile_X0Y0_S2MID[0]
  PIN Tile_X0Y0_S2MID[1]
    DIRECTION INPUT ;
    USE SIGNAL ;
    ANTENNAGATEAREA 0.213000 ;
    PORT
      LAYER met2 ;
        RECT 55.290 519.240 55.570 519.520 ;
    END
  END Tile_X0Y0_S2MID[1]
  PIN Tile_X0Y0_S2MID[2]
    DIRECTION INPUT ;
    USE SIGNAL ;
    ANTENNAGATEAREA 0.159000 ;
    PORT
      LAYER met2 ;
        RECT 56.210 519.240 56.490 519.520 ;
    END
  END Tile_X0Y0_S2MID[2]
  PIN Tile_X0Y0_S2MID[3]
    DIRECTION INPUT ;
    USE SIGNAL ;
    ANTENNAGATEAREA 0.159000 ;
    PORT
      LAYER met2 ;
        RECT 57.130 519.240 57.410 519.520 ;
    END
  END Tile_X0Y0_S2MID[3]
  PIN Tile_X0Y0_S2MID[4]
    DIRECTION INPUT ;
    USE SIGNAL ;
    ANTENNAGATEAREA 0.213000 ;
    PORT
      LAYER met2 ;
        RECT 58.050 519.240 58.330 519.520 ;
    END
  END Tile_X0Y0_S2MID[4]
  PIN Tile_X0Y0_S2MID[5]
    DIRECTION INPUT ;
    USE SIGNAL ;
    ANTENNAGATEAREA 0.159000 ;
    PORT
      LAYER met2 ;
        RECT 58.970 519.240 59.250 519.520 ;
    END
  END Tile_X0Y0_S2MID[5]
  PIN Tile_X0Y0_S2MID[6]
    DIRECTION INPUT ;
    USE SIGNAL ;
    ANTENNAGATEAREA 0.159000 ;
    PORT
      LAYER met2 ;
        RECT 59.890 519.240 60.170 519.520 ;
    END
  END Tile_X0Y0_S2MID[6]
  PIN Tile_X0Y0_S2MID[7]
    DIRECTION INPUT ;
    USE SIGNAL ;
    ANTENNAGATEAREA 0.159000 ;
    PORT
      LAYER met2 ;
        RECT 60.810 519.240 61.090 519.520 ;
    END
  END Tile_X0Y0_S2MID[7]
  PIN Tile_X0Y0_S4END[0]
    DIRECTION INPUT ;
    USE SIGNAL ;
    ANTENNAGATEAREA 0.213000 ;
    PORT
      LAYER met2 ;
        RECT 69.090 519.240 69.370 519.520 ;
    END
  END Tile_X0Y0_S4END[0]
  PIN Tile_X0Y0_S4END[10]
    DIRECTION INPUT ;
    USE SIGNAL ;
    ANTENNAGATEAREA 0.495000 ;
    PORT
      LAYER met2 ;
        RECT 78.290 519.240 78.570 519.520 ;
    END
  END Tile_X0Y0_S4END[10]
  PIN Tile_X0Y0_S4END[11]
    DIRECTION INPUT ;
    USE SIGNAL ;
    ANTENNAGATEAREA 0.495000 ;
    PORT
      LAYER met2 ;
        RECT 79.210 519.240 79.490 519.520 ;
    END
  END Tile_X0Y0_S4END[11]
  PIN Tile_X0Y0_S4END[12]
    DIRECTION INPUT ;
    USE SIGNAL ;
    ANTENNAGATEAREA 0.495000 ;
    PORT
      LAYER met2 ;
        RECT 80.130 519.240 80.410 519.520 ;
    END
  END Tile_X0Y0_S4END[12]
  PIN Tile_X0Y0_S4END[13]
    DIRECTION INPUT ;
    USE SIGNAL ;
    ANTENNAGATEAREA 0.495000 ;
    PORT
      LAYER met2 ;
        RECT 81.050 519.240 81.330 519.520 ;
    END
  END Tile_X0Y0_S4END[13]
  PIN Tile_X0Y0_S4END[14]
    DIRECTION INPUT ;
    USE SIGNAL ;
    ANTENNAGATEAREA 0.196500 ;
    PORT
      LAYER met2 ;
        RECT 81.970 519.240 82.250 519.520 ;
    END
  END Tile_X0Y0_S4END[14]
  PIN Tile_X0Y0_S4END[15]
    DIRECTION INPUT ;
    USE SIGNAL ;
    ANTENNAGATEAREA 0.495000 ;
    PORT
      LAYER met2 ;
        RECT 82.890 519.240 83.170 519.520 ;
    END
  END Tile_X0Y0_S4END[15]
  PIN Tile_X0Y0_S4END[1]
    DIRECTION INPUT ;
    USE SIGNAL ;
    ANTENNAGATEAREA 0.213000 ;
    PORT
      LAYER met2 ;
        RECT 70.010 519.240 70.290 519.520 ;
    END
  END Tile_X0Y0_S4END[1]
  PIN Tile_X0Y0_S4END[2]
    DIRECTION INPUT ;
    USE SIGNAL ;
    ANTENNAGATEAREA 0.159000 ;
    PORT
      LAYER met2 ;
        RECT 70.930 519.240 71.210 519.520 ;
    END
  END Tile_X0Y0_S4END[2]
  PIN Tile_X0Y0_S4END[3]
    DIRECTION INPUT ;
    USE SIGNAL ;
    ANTENNAGATEAREA 0.213000 ;
    PORT
      LAYER met2 ;
        RECT 71.850 519.240 72.130 519.520 ;
    END
  END Tile_X0Y0_S4END[3]
  PIN Tile_X0Y0_S4END[4]
    DIRECTION INPUT ;
    USE SIGNAL ;
    ANTENNAGATEAREA 0.213000 ;
    PORT
      LAYER met2 ;
        RECT 72.770 519.240 73.050 519.520 ;
    END
  END Tile_X0Y0_S4END[4]
  PIN Tile_X0Y0_S4END[5]
    DIRECTION INPUT ;
    USE SIGNAL ;
    ANTENNAGATEAREA 0.213000 ;
    PORT
      LAYER met2 ;
        RECT 73.690 519.240 73.970 519.520 ;
    END
  END Tile_X0Y0_S4END[5]
  PIN Tile_X0Y0_S4END[6]
    DIRECTION INPUT ;
    USE SIGNAL ;
    ANTENNAGATEAREA 0.213000 ;
    PORT
      LAYER met2 ;
        RECT 74.610 519.240 74.890 519.520 ;
    END
  END Tile_X0Y0_S4END[6]
  PIN Tile_X0Y0_S4END[7]
    DIRECTION INPUT ;
    USE SIGNAL ;
    ANTENNAGATEAREA 0.213000 ;
    PORT
      LAYER met2 ;
        RECT 75.530 519.240 75.810 519.520 ;
    END
  END Tile_X0Y0_S4END[7]
  PIN Tile_X0Y0_S4END[8]
    DIRECTION INPUT ;
    USE SIGNAL ;
    ANTENNAGATEAREA 0.196500 ;
    PORT
      LAYER met2 ;
        RECT 76.450 519.240 76.730 519.520 ;
    END
  END Tile_X0Y0_S4END[8]
  PIN Tile_X0Y0_S4END[9]
    DIRECTION INPUT ;
    USE SIGNAL ;
    ANTENNAGATEAREA 0.495000 ;
    PORT
      LAYER met2 ;
        RECT 77.370 519.240 77.650 519.520 ;
    END
  END Tile_X0Y0_S4END[9]
  PIN Tile_X0Y0_UserCLKo
    DIRECTION OUTPUT ;
    USE SIGNAL ;
    ANTENNADIFFAREA 0.340600 ;
    PORT
      LAYER met2 ;
        RECT 83.810 519.240 84.090 519.520 ;
    END
  END Tile_X0Y0_UserCLKo
  PIN Tile_X0Y0_W1BEG[0]
    DIRECTION OUTPUT ;
    USE SIGNAL ;
    ANTENNADIFFAREA 0.445500 ;
    PORT
      LAYER met3 ;
        RECT 0.000 301.960 0.600 302.560 ;
    END
  END Tile_X0Y0_W1BEG[0]
  PIN Tile_X0Y0_W1BEG[1]
    DIRECTION OUTPUT ;
    USE SIGNAL ;
    ANTENNADIFFAREA 0.445500 ;
    PORT
      LAYER met3 ;
        RECT 0.000 303.320 0.600 303.920 ;
    END
  END Tile_X0Y0_W1BEG[1]
  PIN Tile_X0Y0_W1BEG[2]
    DIRECTION OUTPUT ;
    USE SIGNAL ;
    ANTENNADIFFAREA 0.445500 ;
    PORT
      LAYER met3 ;
        RECT 0.000 304.680 0.600 305.280 ;
    END
  END Tile_X0Y0_W1BEG[2]
  PIN Tile_X0Y0_W1BEG[3]
    DIRECTION OUTPUT ;
    USE SIGNAL ;
    ANTENNADIFFAREA 0.445500 ;
    PORT
      LAYER met3 ;
        RECT 0.000 306.040 0.600 306.640 ;
    END
  END Tile_X0Y0_W1BEG[3]
  PIN Tile_X0Y0_W2BEG[0]
    DIRECTION OUTPUT ;
    USE SIGNAL ;
    ANTENNADIFFAREA 0.445500 ;
    PORT
      LAYER met3 ;
        RECT 0.000 307.400 0.600 308.000 ;
    END
  END Tile_X0Y0_W2BEG[0]
  PIN Tile_X0Y0_W2BEG[1]
    DIRECTION OUTPUT ;
    USE SIGNAL ;
    ANTENNADIFFAREA 0.445500 ;
    PORT
      LAYER met3 ;
        RECT 0.000 308.760 0.600 309.360 ;
    END
  END Tile_X0Y0_W2BEG[1]
  PIN Tile_X0Y0_W2BEG[2]
    DIRECTION OUTPUT ;
    USE SIGNAL ;
    ANTENNADIFFAREA 0.445500 ;
    PORT
      LAYER met3 ;
        RECT 0.000 310.120 0.600 310.720 ;
    END
  END Tile_X0Y0_W2BEG[2]
  PIN Tile_X0Y0_W2BEG[3]
    DIRECTION OUTPUT ;
    USE SIGNAL ;
    ANTENNADIFFAREA 0.445500 ;
    PORT
      LAYER met3 ;
        RECT 0.000 311.480 0.600 312.080 ;
    END
  END Tile_X0Y0_W2BEG[3]
  PIN Tile_X0Y0_W2BEG[4]
    DIRECTION OUTPUT ;
    USE SIGNAL ;
    ANTENNADIFFAREA 0.445500 ;
    PORT
      LAYER met3 ;
        RECT 0.000 312.840 0.600 313.440 ;
    END
  END Tile_X0Y0_W2BEG[4]
  PIN Tile_X0Y0_W2BEG[5]
    DIRECTION OUTPUT ;
    USE SIGNAL ;
    ANTENNADIFFAREA 0.445500 ;
    PORT
      LAYER met3 ;
        RECT 0.000 314.200 0.600 314.800 ;
    END
  END Tile_X0Y0_W2BEG[5]
  PIN Tile_X0Y0_W2BEG[6]
    DIRECTION OUTPUT ;
    USE SIGNAL ;
    ANTENNADIFFAREA 0.445500 ;
    PORT
      LAYER met3 ;
        RECT 0.000 315.560 0.600 316.160 ;
    END
  END Tile_X0Y0_W2BEG[6]
  PIN Tile_X0Y0_W2BEG[7]
    DIRECTION OUTPUT ;
    USE SIGNAL ;
    ANTENNADIFFAREA 0.445500 ;
    PORT
      LAYER met3 ;
        RECT 0.000 316.920 0.600 317.520 ;
    END
  END Tile_X0Y0_W2BEG[7]
  PIN Tile_X0Y0_W2BEGb[0]
    DIRECTION OUTPUT ;
    USE SIGNAL ;
    ANTENNADIFFAREA 0.445500 ;
    PORT
      LAYER met3 ;
        RECT 0.000 318.280 0.600 318.880 ;
    END
  END Tile_X0Y0_W2BEGb[0]
  PIN Tile_X0Y0_W2BEGb[1]
    DIRECTION OUTPUT ;
    USE SIGNAL ;
    ANTENNADIFFAREA 0.445500 ;
    PORT
      LAYER met3 ;
        RECT 0.000 319.640 0.600 320.240 ;
    END
  END Tile_X0Y0_W2BEGb[1]
  PIN Tile_X0Y0_W2BEGb[2]
    DIRECTION OUTPUT ;
    USE SIGNAL ;
    ANTENNADIFFAREA 0.445500 ;
    PORT
      LAYER met3 ;
        RECT 0.000 321.000 0.600 321.600 ;
    END
  END Tile_X0Y0_W2BEGb[2]
  PIN Tile_X0Y0_W2BEGb[3]
    DIRECTION OUTPUT ;
    USE SIGNAL ;
    ANTENNADIFFAREA 0.445500 ;
    PORT
      LAYER met3 ;
        RECT 0.000 322.360 0.600 322.960 ;
    END
  END Tile_X0Y0_W2BEGb[3]
  PIN Tile_X0Y0_W2BEGb[4]
    DIRECTION OUTPUT ;
    USE SIGNAL ;
    ANTENNADIFFAREA 0.445500 ;
    PORT
      LAYER met3 ;
        RECT 0.000 323.720 0.600 324.320 ;
    END
  END Tile_X0Y0_W2BEGb[4]
  PIN Tile_X0Y0_W2BEGb[5]
    DIRECTION OUTPUT ;
    USE SIGNAL ;
    ANTENNADIFFAREA 0.445500 ;
    PORT
      LAYER met3 ;
        RECT 0.000 325.080 0.600 325.680 ;
    END
  END Tile_X0Y0_W2BEGb[5]
  PIN Tile_X0Y0_W2BEGb[6]
    DIRECTION OUTPUT ;
    USE SIGNAL ;
    ANTENNADIFFAREA 0.445500 ;
    PORT
      LAYER met3 ;
        RECT 0.000 326.440 0.600 327.040 ;
    END
  END Tile_X0Y0_W2BEGb[6]
  PIN Tile_X0Y0_W2BEGb[7]
    DIRECTION OUTPUT ;
    USE SIGNAL ;
    ANTENNADIFFAREA 0.445500 ;
    PORT
      LAYER met3 ;
        RECT 0.000 327.800 0.600 328.400 ;
    END
  END Tile_X0Y0_W2BEGb[7]
  PIN Tile_X0Y0_W6BEG[0]
    DIRECTION OUTPUT ;
    USE SIGNAL ;
    ANTENNADIFFAREA 0.445500 ;
    PORT
      LAYER met3 ;
        RECT 0.000 350.920 0.600 351.520 ;
    END
  END Tile_X0Y0_W6BEG[0]
  PIN Tile_X0Y0_W6BEG[10]
    DIRECTION OUTPUT ;
    USE SIGNAL ;
    ANTENNADIFFAREA 0.445500 ;
    PORT
      LAYER met3 ;
        RECT 0.000 364.520 0.600 365.120 ;
    END
  END Tile_X0Y0_W6BEG[10]
  PIN Tile_X0Y0_W6BEG[11]
    DIRECTION OUTPUT ;
    USE SIGNAL ;
    ANTENNADIFFAREA 0.445500 ;
    PORT
      LAYER met3 ;
        RECT 0.000 365.880 0.600 366.480 ;
    END
  END Tile_X0Y0_W6BEG[11]
  PIN Tile_X0Y0_W6BEG[1]
    DIRECTION OUTPUT ;
    USE SIGNAL ;
    ANTENNADIFFAREA 0.445500 ;
    PORT
      LAYER met3 ;
        RECT 0.000 352.280 0.600 352.880 ;
    END
  END Tile_X0Y0_W6BEG[1]
  PIN Tile_X0Y0_W6BEG[2]
    DIRECTION OUTPUT ;
    USE SIGNAL ;
    ANTENNADIFFAREA 0.445500 ;
    PORT
      LAYER met3 ;
        RECT 0.000 353.640 0.600 354.240 ;
    END
  END Tile_X0Y0_W6BEG[2]
  PIN Tile_X0Y0_W6BEG[3]
    DIRECTION OUTPUT ;
    USE SIGNAL ;
    ANTENNADIFFAREA 0.445500 ;
    PORT
      LAYER met3 ;
        RECT 0.000 355.000 0.600 355.600 ;
    END
  END Tile_X0Y0_W6BEG[3]
  PIN Tile_X0Y0_W6BEG[4]
    DIRECTION OUTPUT ;
    USE SIGNAL ;
    ANTENNADIFFAREA 0.445500 ;
    PORT
      LAYER met3 ;
        RECT 0.000 356.360 0.600 356.960 ;
    END
  END Tile_X0Y0_W6BEG[4]
  PIN Tile_X0Y0_W6BEG[5]
    DIRECTION OUTPUT ;
    USE SIGNAL ;
    ANTENNADIFFAREA 0.445500 ;
    PORT
      LAYER met3 ;
        RECT 0.000 357.720 0.600 358.320 ;
    END
  END Tile_X0Y0_W6BEG[5]
  PIN Tile_X0Y0_W6BEG[6]
    DIRECTION OUTPUT ;
    USE SIGNAL ;
    ANTENNADIFFAREA 0.445500 ;
    PORT
      LAYER met3 ;
        RECT 0.000 359.080 0.600 359.680 ;
    END
  END Tile_X0Y0_W6BEG[6]
  PIN Tile_X0Y0_W6BEG[7]
    DIRECTION OUTPUT ;
    USE SIGNAL ;
    ANTENNADIFFAREA 0.445500 ;
    PORT
      LAYER met3 ;
        RECT 0.000 360.440 0.600 361.040 ;
    END
  END Tile_X0Y0_W6BEG[7]
  PIN Tile_X0Y0_W6BEG[8]
    DIRECTION OUTPUT ;
    USE SIGNAL ;
    ANTENNADIFFAREA 0.445500 ;
    PORT
      LAYER met3 ;
        RECT 0.000 361.800 0.600 362.400 ;
    END
  END Tile_X0Y0_W6BEG[8]
  PIN Tile_X0Y0_W6BEG[9]
    DIRECTION OUTPUT ;
    USE SIGNAL ;
    ANTENNADIFFAREA 0.445500 ;
    PORT
      LAYER met3 ;
        RECT 0.000 363.160 0.600 363.760 ;
    END
  END Tile_X0Y0_W6BEG[9]
  PIN Tile_X0Y0_WW4BEG[0]
    DIRECTION OUTPUT ;
    USE SIGNAL ;
    ANTENNADIFFAREA 0.445500 ;
    PORT
      LAYER met3 ;
        RECT 0.000 329.160 0.600 329.760 ;
    END
  END Tile_X0Y0_WW4BEG[0]
  PIN Tile_X0Y0_WW4BEG[10]
    DIRECTION OUTPUT ;
    USE SIGNAL ;
    ANTENNADIFFAREA 0.445500 ;
    PORT
      LAYER met3 ;
        RECT 0.000 342.760 0.600 343.360 ;
    END
  END Tile_X0Y0_WW4BEG[10]
  PIN Tile_X0Y0_WW4BEG[11]
    DIRECTION OUTPUT ;
    USE SIGNAL ;
    ANTENNADIFFAREA 0.445500 ;
    PORT
      LAYER met3 ;
        RECT 0.000 344.120 0.600 344.720 ;
    END
  END Tile_X0Y0_WW4BEG[11]
  PIN Tile_X0Y0_WW4BEG[12]
    DIRECTION OUTPUT ;
    USE SIGNAL ;
    ANTENNADIFFAREA 0.445500 ;
    PORT
      LAYER met3 ;
        RECT 0.000 345.480 0.600 346.080 ;
    END
  END Tile_X0Y0_WW4BEG[12]
  PIN Tile_X0Y0_WW4BEG[13]
    DIRECTION OUTPUT ;
    USE SIGNAL ;
    ANTENNADIFFAREA 0.445500 ;
    PORT
      LAYER met3 ;
        RECT 0.000 346.840 0.600 347.440 ;
    END
  END Tile_X0Y0_WW4BEG[13]
  PIN Tile_X0Y0_WW4BEG[14]
    DIRECTION OUTPUT ;
    USE SIGNAL ;
    ANTENNADIFFAREA 0.445500 ;
    PORT
      LAYER met3 ;
        RECT 0.000 348.200 0.600 348.800 ;
    END
  END Tile_X0Y0_WW4BEG[14]
  PIN Tile_X0Y0_WW4BEG[15]
    DIRECTION OUTPUT ;
    USE SIGNAL ;
    ANTENNADIFFAREA 0.445500 ;
    PORT
      LAYER met3 ;
        RECT 0.000 349.560 0.600 350.160 ;
    END
  END Tile_X0Y0_WW4BEG[15]
  PIN Tile_X0Y0_WW4BEG[1]
    DIRECTION OUTPUT ;
    USE SIGNAL ;
    ANTENNADIFFAREA 0.445500 ;
    PORT
      LAYER met3 ;
        RECT 0.000 330.520 0.600 331.120 ;
    END
  END Tile_X0Y0_WW4BEG[1]
  PIN Tile_X0Y0_WW4BEG[2]
    DIRECTION OUTPUT ;
    USE SIGNAL ;
    ANTENNADIFFAREA 0.445500 ;
    PORT
      LAYER met3 ;
        RECT 0.000 331.880 0.600 332.480 ;
    END
  END Tile_X0Y0_WW4BEG[2]
  PIN Tile_X0Y0_WW4BEG[3]
    DIRECTION OUTPUT ;
    USE SIGNAL ;
    ANTENNADIFFAREA 0.445500 ;
    PORT
      LAYER met3 ;
        RECT 0.000 333.240 0.600 333.840 ;
    END
  END Tile_X0Y0_WW4BEG[3]
  PIN Tile_X0Y0_WW4BEG[4]
    DIRECTION OUTPUT ;
    USE SIGNAL ;
    ANTENNADIFFAREA 0.445500 ;
    PORT
      LAYER met3 ;
        RECT 0.000 334.600 0.600 335.200 ;
    END
  END Tile_X0Y0_WW4BEG[4]
  PIN Tile_X0Y0_WW4BEG[5]
    DIRECTION OUTPUT ;
    USE SIGNAL ;
    ANTENNADIFFAREA 0.445500 ;
    PORT
      LAYER met3 ;
        RECT 0.000 335.960 0.600 336.560 ;
    END
  END Tile_X0Y0_WW4BEG[5]
  PIN Tile_X0Y0_WW4BEG[6]
    DIRECTION OUTPUT ;
    USE SIGNAL ;
    ANTENNADIFFAREA 0.445500 ;
    PORT
      LAYER met3 ;
        RECT 0.000 337.320 0.600 337.920 ;
    END
  END Tile_X0Y0_WW4BEG[6]
  PIN Tile_X0Y0_WW4BEG[7]
    DIRECTION OUTPUT ;
    USE SIGNAL ;
    ANTENNADIFFAREA 0.445500 ;
    PORT
      LAYER met3 ;
        RECT 0.000 338.680 0.600 339.280 ;
    END
  END Tile_X0Y0_WW4BEG[7]
  PIN Tile_X0Y0_WW4BEG[8]
    DIRECTION OUTPUT ;
    USE SIGNAL ;
    ANTENNADIFFAREA 0.445500 ;
    PORT
      LAYER met3 ;
        RECT 0.000 340.040 0.600 340.640 ;
    END
  END Tile_X0Y0_WW4BEG[8]
  PIN Tile_X0Y0_WW4BEG[9]
    DIRECTION OUTPUT ;
    USE SIGNAL ;
    ANTENNADIFFAREA 0.445500 ;
    PORT
      LAYER met3 ;
        RECT 0.000 341.400 0.600 342.000 ;
    END
  END Tile_X0Y0_WW4BEG[9]
  PIN Tile_X0Y1_E1END[0]
    DIRECTION INPUT ;
    USE SIGNAL ;
    ANTENNAGATEAREA 0.213000 ;
    PORT
      LAYER met3 ;
        RECT 0.000 107.480 0.600 108.080 ;
    END
  END Tile_X0Y1_E1END[0]
  PIN Tile_X0Y1_E1END[1]
    DIRECTION INPUT ;
    USE SIGNAL ;
    ANTENNAGATEAREA 0.159000 ;
    PORT
      LAYER met3 ;
        RECT 0.000 108.840 0.600 109.440 ;
    END
  END Tile_X0Y1_E1END[1]
  PIN Tile_X0Y1_E1END[2]
    DIRECTION INPUT ;
    USE SIGNAL ;
    ANTENNAGATEAREA 0.213000 ;
    PORT
      LAYER met3 ;
        RECT 0.000 110.200 0.600 110.800 ;
    END
  END Tile_X0Y1_E1END[2]
  PIN Tile_X0Y1_E1END[3]
    DIRECTION INPUT ;
    USE SIGNAL ;
    ANTENNAGATEAREA 0.213000 ;
    PORT
      LAYER met3 ;
        RECT 0.000 111.560 0.600 112.160 ;
    END
  END Tile_X0Y1_E1END[3]
  PIN Tile_X0Y1_E2END[0]
    DIRECTION INPUT ;
    USE SIGNAL ;
    ANTENNAGATEAREA 0.213000 ;
    PORT
      LAYER met3 ;
        RECT 0.000 123.800 0.600 124.400 ;
    END
  END Tile_X0Y1_E2END[0]
  PIN Tile_X0Y1_E2END[1]
    DIRECTION INPUT ;
    USE SIGNAL ;
    ANTENNAGATEAREA 0.159000 ;
    PORT
      LAYER met3 ;
        RECT 0.000 125.160 0.600 125.760 ;
    END
  END Tile_X0Y1_E2END[1]
  PIN Tile_X0Y1_E2END[2]
    DIRECTION INPUT ;
    USE SIGNAL ;
    ANTENNAGATEAREA 0.159000 ;
    PORT
      LAYER met3 ;
        RECT 0.000 126.520 0.600 127.120 ;
    END
  END Tile_X0Y1_E2END[2]
  PIN Tile_X0Y1_E2END[3]
    DIRECTION INPUT ;
    USE SIGNAL ;
    ANTENNAGATEAREA 0.159000 ;
    PORT
      LAYER met3 ;
        RECT 0.000 127.880 0.600 128.480 ;
    END
  END Tile_X0Y1_E2END[3]
  PIN Tile_X0Y1_E2END[4]
    DIRECTION INPUT ;
    USE SIGNAL ;
    ANTENNAGATEAREA 0.213000 ;
    PORT
      LAYER met3 ;
        RECT 0.000 129.240 0.600 129.840 ;
    END
  END Tile_X0Y1_E2END[4]
  PIN Tile_X0Y1_E2END[5]
    DIRECTION INPUT ;
    USE SIGNAL ;
    ANTENNAGATEAREA 0.213000 ;
    PORT
      LAYER met3 ;
        RECT 0.000 130.600 0.600 131.200 ;
    END
  END Tile_X0Y1_E2END[5]
  PIN Tile_X0Y1_E2END[6]
    DIRECTION INPUT ;
    USE SIGNAL ;
    ANTENNAGATEAREA 0.213000 ;
    PORT
      LAYER met3 ;
        RECT 0.000 131.960 0.600 132.560 ;
    END
  END Tile_X0Y1_E2END[6]
  PIN Tile_X0Y1_E2END[7]
    DIRECTION INPUT ;
    USE SIGNAL ;
    ANTENNAGATEAREA 0.196500 ;
    PORT
      LAYER met3 ;
        RECT 0.000 133.320 0.600 133.920 ;
    END
  END Tile_X0Y1_E2END[7]
  PIN Tile_X0Y1_E2MID[0]
    DIRECTION INPUT ;
    USE SIGNAL ;
    ANTENNAGATEAREA 0.159000 ;
    PORT
      LAYER met3 ;
        RECT 0.000 112.920 0.600 113.520 ;
    END
  END Tile_X0Y1_E2MID[0]
  PIN Tile_X0Y1_E2MID[1]
    DIRECTION INPUT ;
    USE SIGNAL ;
    ANTENNAGATEAREA 0.159000 ;
    PORT
      LAYER met3 ;
        RECT 0.000 114.280 0.600 114.880 ;
    END
  END Tile_X0Y1_E2MID[1]
  PIN Tile_X0Y1_E2MID[2]
    DIRECTION INPUT ;
    USE SIGNAL ;
    ANTENNAGATEAREA 0.213000 ;
    PORT
      LAYER met3 ;
        RECT 0.000 115.640 0.600 116.240 ;
    END
  END Tile_X0Y1_E2MID[2]
  PIN Tile_X0Y1_E2MID[3]
    DIRECTION INPUT ;
    USE SIGNAL ;
    ANTENNAGATEAREA 0.159000 ;
    PORT
      LAYER met3 ;
        RECT 0.000 117.000 0.600 117.600 ;
    END
  END Tile_X0Y1_E2MID[3]
  PIN Tile_X0Y1_E2MID[4]
    DIRECTION INPUT ;
    USE SIGNAL ;
    ANTENNAGATEAREA 0.196500 ;
    PORT
      LAYER met3 ;
        RECT 0.000 118.360 0.600 118.960 ;
    END
  END Tile_X0Y1_E2MID[4]
  PIN Tile_X0Y1_E2MID[5]
    DIRECTION INPUT ;
    USE SIGNAL ;
    ANTENNAGATEAREA 0.126000 ;
    PORT
      LAYER met3 ;
        RECT 0.000 119.720 0.600 120.320 ;
    END
  END Tile_X0Y1_E2MID[5]
  PIN Tile_X0Y1_E2MID[6]
    DIRECTION INPUT ;
    USE SIGNAL ;
    ANTENNAGATEAREA 0.213000 ;
    PORT
      LAYER met3 ;
        RECT 0.000 121.080 0.600 121.680 ;
    END
  END Tile_X0Y1_E2MID[6]
  PIN Tile_X0Y1_E2MID[7]
    DIRECTION INPUT ;
    USE SIGNAL ;
    ANTENNAGATEAREA 0.196500 ;
    PORT
      LAYER met3 ;
        RECT 0.000 122.440 0.600 123.040 ;
    END
  END Tile_X0Y1_E2MID[7]
  PIN Tile_X0Y1_E6END[0]
    DIRECTION INPUT ;
    USE SIGNAL ;
    ANTENNAGATEAREA 0.196500 ;
    PORT
      LAYER met3 ;
        RECT 0.000 156.440 0.600 157.040 ;
    END
  END Tile_X0Y1_E6END[0]
  PIN Tile_X0Y1_E6END[10]
    DIRECTION INPUT ;
    USE SIGNAL ;
    ANTENNAGATEAREA 0.213000 ;
    PORT
      LAYER met3 ;
        RECT 0.000 170.040 0.600 170.640 ;
    END
  END Tile_X0Y1_E6END[10]
  PIN Tile_X0Y1_E6END[11]
    DIRECTION INPUT ;
    USE SIGNAL ;
    ANTENNAGATEAREA 0.126000 ;
    PORT
      LAYER met3 ;
        RECT 0.000 171.400 0.600 172.000 ;
    END
  END Tile_X0Y1_E6END[11]
  PIN Tile_X0Y1_E6END[1]
    DIRECTION INPUT ;
    USE SIGNAL ;
    ANTENNAGATEAREA 0.213000 ;
    PORT
      LAYER met3 ;
        RECT 0.000 157.800 0.600 158.400 ;
    END
  END Tile_X0Y1_E6END[1]
  PIN Tile_X0Y1_E6END[2]
    DIRECTION INPUT ;
    USE SIGNAL ;
    ANTENNAGATEAREA 0.213000 ;
    PORT
      LAYER met3 ;
        RECT 0.000 159.160 0.600 159.760 ;
    END
  END Tile_X0Y1_E6END[2]
  PIN Tile_X0Y1_E6END[3]
    DIRECTION INPUT ;
    USE SIGNAL ;
    ANTENNAGATEAREA 0.126000 ;
    PORT
      LAYER met3 ;
        RECT 0.000 160.520 0.600 161.120 ;
    END
  END Tile_X0Y1_E6END[3]
  PIN Tile_X0Y1_E6END[4]
    DIRECTION INPUT ;
    USE SIGNAL ;
    ANTENNAGATEAREA 0.196500 ;
    PORT
      LAYER met3 ;
        RECT 0.000 161.880 0.600 162.480 ;
    END
  END Tile_X0Y1_E6END[4]
  PIN Tile_X0Y1_E6END[5]
    DIRECTION INPUT ;
    USE SIGNAL ;
    ANTENNAGATEAREA 0.213000 ;
    PORT
      LAYER met3 ;
        RECT 0.000 163.240 0.600 163.840 ;
    END
  END Tile_X0Y1_E6END[5]
  PIN Tile_X0Y1_E6END[6]
    DIRECTION INPUT ;
    USE SIGNAL ;
    ANTENNAGATEAREA 0.213000 ;
    PORT
      LAYER met3 ;
        RECT 0.000 164.600 0.600 165.200 ;
    END
  END Tile_X0Y1_E6END[6]
  PIN Tile_X0Y1_E6END[7]
    DIRECTION INPUT ;
    USE SIGNAL ;
    ANTENNAGATEAREA 0.126000 ;
    PORT
      LAYER met3 ;
        RECT 0.000 165.960 0.600 166.560 ;
    END
  END Tile_X0Y1_E6END[7]
  PIN Tile_X0Y1_E6END[8]
    DIRECTION INPUT ;
    USE SIGNAL ;
    ANTENNAGATEAREA 0.196500 ;
    PORT
      LAYER met3 ;
        RECT 0.000 167.320 0.600 167.920 ;
    END
  END Tile_X0Y1_E6END[8]
  PIN Tile_X0Y1_E6END[9]
    DIRECTION INPUT ;
    USE SIGNAL ;
    ANTENNAGATEAREA 0.213000 ;
    PORT
      LAYER met3 ;
        RECT 0.000 168.680 0.600 169.280 ;
    END
  END Tile_X0Y1_E6END[9]
  PIN Tile_X0Y1_EE4END[0]
    DIRECTION INPUT ;
    USE SIGNAL ;
    ANTENNAGATEAREA 0.196500 ;
    PORT
      LAYER met3 ;
        RECT 0.000 134.680 0.600 135.280 ;
    END
  END Tile_X0Y1_EE4END[0]
  PIN Tile_X0Y1_EE4END[10]
    DIRECTION INPUT ;
    USE SIGNAL ;
    ANTENNAGATEAREA 0.196500 ;
    PORT
      LAYER met3 ;
        RECT 0.000 148.280 0.600 148.880 ;
    END
  END Tile_X0Y1_EE4END[10]
  PIN Tile_X0Y1_EE4END[11]
    DIRECTION INPUT ;
    USE SIGNAL ;
    ANTENNAGATEAREA 0.196500 ;
    PORT
      LAYER met3 ;
        RECT 0.000 149.640 0.600 150.240 ;
    END
  END Tile_X0Y1_EE4END[11]
  PIN Tile_X0Y1_EE4END[12]
    DIRECTION INPUT ;
    USE SIGNAL ;
    ANTENNAGATEAREA 0.196500 ;
    PORT
      LAYER met3 ;
        RECT 0.000 151.000 0.600 151.600 ;
    END
  END Tile_X0Y1_EE4END[12]
  PIN Tile_X0Y1_EE4END[13]
    DIRECTION INPUT ;
    USE SIGNAL ;
    ANTENNAGATEAREA 0.126000 ;
    PORT
      LAYER met3 ;
        RECT 0.000 152.360 0.600 152.960 ;
    END
  END Tile_X0Y1_EE4END[13]
  PIN Tile_X0Y1_EE4END[14]
    DIRECTION INPUT ;
    USE SIGNAL ;
    ANTENNAGATEAREA 0.196500 ;
    PORT
      LAYER met3 ;
        RECT 0.000 153.720 0.600 154.320 ;
    END
  END Tile_X0Y1_EE4END[14]
  PIN Tile_X0Y1_EE4END[15]
    DIRECTION INPUT ;
    USE SIGNAL ;
    ANTENNAGATEAREA 0.196500 ;
    PORT
      LAYER met3 ;
        RECT 0.000 155.080 0.600 155.680 ;
    END
  END Tile_X0Y1_EE4END[15]
  PIN Tile_X0Y1_EE4END[1]
    DIRECTION INPUT ;
    USE SIGNAL ;
    ANTENNAGATEAREA 0.213000 ;
    PORT
      LAYER met3 ;
        RECT 0.000 136.040 0.600 136.640 ;
    END
  END Tile_X0Y1_EE4END[1]
  PIN Tile_X0Y1_EE4END[2]
    DIRECTION INPUT ;
    USE SIGNAL ;
    ANTENNAGATEAREA 0.196500 ;
    PORT
      LAYER met3 ;
        RECT 0.000 137.400 0.600 138.000 ;
    END
  END Tile_X0Y1_EE4END[2]
  PIN Tile_X0Y1_EE4END[3]
    DIRECTION INPUT ;
    USE SIGNAL ;
    ANTENNAGATEAREA 0.196500 ;
    PORT
      LAYER met3 ;
        RECT 0.000 138.760 0.600 139.360 ;
    END
  END Tile_X0Y1_EE4END[3]
  PIN Tile_X0Y1_EE4END[4]
    DIRECTION INPUT ;
    USE SIGNAL ;
    ANTENNAGATEAREA 0.196500 ;
    PORT
      LAYER met3 ;
        RECT 0.000 140.120 0.600 140.720 ;
    END
  END Tile_X0Y1_EE4END[4]
  PIN Tile_X0Y1_EE4END[5]
    DIRECTION INPUT ;
    USE SIGNAL ;
    ANTENNAGATEAREA 0.196500 ;
    PORT
      LAYER met3 ;
        RECT 0.000 141.480 0.600 142.080 ;
    END
  END Tile_X0Y1_EE4END[5]
  PIN Tile_X0Y1_EE4END[6]
    DIRECTION INPUT ;
    USE SIGNAL ;
    ANTENNAGATEAREA 0.196500 ;
    PORT
      LAYER met3 ;
        RECT 0.000 142.840 0.600 143.440 ;
    END
  END Tile_X0Y1_EE4END[6]
  PIN Tile_X0Y1_EE4END[7]
    DIRECTION INPUT ;
    USE SIGNAL ;
    ANTENNAGATEAREA 0.196500 ;
    PORT
      LAYER met3 ;
        RECT 0.000 144.200 0.600 144.800 ;
    END
  END Tile_X0Y1_EE4END[7]
  PIN Tile_X0Y1_EE4END[8]
    DIRECTION INPUT ;
    USE SIGNAL ;
    ANTENNAGATEAREA 0.196500 ;
    PORT
      LAYER met3 ;
        RECT 0.000 145.560 0.600 146.160 ;
    END
  END Tile_X0Y1_EE4END[8]
  PIN Tile_X0Y1_EE4END[9]
    DIRECTION INPUT ;
    USE SIGNAL ;
    ANTENNAGATEAREA 0.126000 ;
    PORT
      LAYER met3 ;
        RECT 0.000 146.920 0.600 147.520 ;
    END
  END Tile_X0Y1_EE4END[9]
  PIN Tile_X0Y1_FrameData[0]
    DIRECTION INPUT ;
    USE SIGNAL ;
    ANTENNAGATEAREA 0.213000 ;
    PORT
      LAYER met3 ;
        RECT 0.000 172.760 0.600 173.360 ;
    END
  END Tile_X0Y1_FrameData[0]
  PIN Tile_X0Y1_FrameData[10]
    DIRECTION INPUT ;
    USE SIGNAL ;
    ANTENNAGATEAREA 0.247500 ;
    PORT
      LAYER met3 ;
        RECT 0.000 186.360 0.600 186.960 ;
    END
  END Tile_X0Y1_FrameData[10]
  PIN Tile_X0Y1_FrameData[11]
    DIRECTION INPUT ;
    USE SIGNAL ;
    ANTENNAGATEAREA 0.247500 ;
    PORT
      LAYER met3 ;
        RECT 0.000 187.720 0.600 188.320 ;
    END
  END Tile_X0Y1_FrameData[11]
  PIN Tile_X0Y1_FrameData[12]
    DIRECTION INPUT ;
    USE SIGNAL ;
    ANTENNAGATEAREA 0.213000 ;
    PORT
      LAYER met3 ;
        RECT 0.000 189.080 0.600 189.680 ;
    END
  END Tile_X0Y1_FrameData[12]
  PIN Tile_X0Y1_FrameData[13]
    DIRECTION INPUT ;
    USE SIGNAL ;
    ANTENNAGATEAREA 0.213000 ;
    PORT
      LAYER met3 ;
        RECT 0.000 190.440 0.600 191.040 ;
    END
  END Tile_X0Y1_FrameData[13]
  PIN Tile_X0Y1_FrameData[14]
    DIRECTION INPUT ;
    USE SIGNAL ;
    ANTENNAGATEAREA 0.247500 ;
    PORT
      LAYER met3 ;
        RECT 0.000 191.800 0.600 192.400 ;
    END
  END Tile_X0Y1_FrameData[14]
  PIN Tile_X0Y1_FrameData[15]
    DIRECTION INPUT ;
    USE SIGNAL ;
    ANTENNAGATEAREA 0.213000 ;
    PORT
      LAYER met3 ;
        RECT 0.000 193.160 0.600 193.760 ;
    END
  END Tile_X0Y1_FrameData[15]
  PIN Tile_X0Y1_FrameData[16]
    DIRECTION INPUT ;
    USE SIGNAL ;
    ANTENNAGATEAREA 0.213000 ;
    PORT
      LAYER met3 ;
        RECT 0.000 194.520 0.600 195.120 ;
    END
  END Tile_X0Y1_FrameData[16]
  PIN Tile_X0Y1_FrameData[17]
    DIRECTION INPUT ;
    USE SIGNAL ;
    ANTENNAGATEAREA 0.213000 ;
    PORT
      LAYER met3 ;
        RECT 0.000 195.880 0.600 196.480 ;
    END
  END Tile_X0Y1_FrameData[17]
  PIN Tile_X0Y1_FrameData[18]
    DIRECTION INPUT ;
    USE SIGNAL ;
    ANTENNAGATEAREA 0.213000 ;
    PORT
      LAYER met3 ;
        RECT 0.000 197.240 0.600 197.840 ;
    END
  END Tile_X0Y1_FrameData[18]
  PIN Tile_X0Y1_FrameData[19]
    DIRECTION INPUT ;
    USE SIGNAL ;
    ANTENNAGATEAREA 0.213000 ;
    PORT
      LAYER met3 ;
        RECT 0.000 198.600 0.600 199.200 ;
    END
  END Tile_X0Y1_FrameData[19]
  PIN Tile_X0Y1_FrameData[1]
    DIRECTION INPUT ;
    USE SIGNAL ;
    ANTENNAGATEAREA 0.213000 ;
    PORT
      LAYER met3 ;
        RECT 0.000 174.120 0.600 174.720 ;
    END
  END Tile_X0Y1_FrameData[1]
  PIN Tile_X0Y1_FrameData[20]
    DIRECTION INPUT ;
    USE SIGNAL ;
    ANTENNAGATEAREA 0.213000 ;
    PORT
      LAYER met3 ;
        RECT 0.000 199.960 0.600 200.560 ;
    END
  END Tile_X0Y1_FrameData[20]
  PIN Tile_X0Y1_FrameData[21]
    DIRECTION INPUT ;
    USE SIGNAL ;
    ANTENNAGATEAREA 0.213000 ;
    PORT
      LAYER met3 ;
        RECT 0.000 201.320 0.600 201.920 ;
    END
  END Tile_X0Y1_FrameData[21]
  PIN Tile_X0Y1_FrameData[22]
    DIRECTION INPUT ;
    USE SIGNAL ;
    ANTENNAGATEAREA 0.213000 ;
    PORT
      LAYER met3 ;
        RECT 0.000 202.680 0.600 203.280 ;
    END
  END Tile_X0Y1_FrameData[22]
  PIN Tile_X0Y1_FrameData[23]
    DIRECTION INPUT ;
    USE SIGNAL ;
    ANTENNAGATEAREA 0.213000 ;
    PORT
      LAYER met3 ;
        RECT 0.000 204.040 0.600 204.640 ;
    END
  END Tile_X0Y1_FrameData[23]
  PIN Tile_X0Y1_FrameData[24]
    DIRECTION INPUT ;
    USE SIGNAL ;
    ANTENNAGATEAREA 0.213000 ;
    PORT
      LAYER met3 ;
        RECT 0.000 205.400 0.600 206.000 ;
    END
  END Tile_X0Y1_FrameData[24]
  PIN Tile_X0Y1_FrameData[25]
    DIRECTION INPUT ;
    USE SIGNAL ;
    ANTENNAGATEAREA 0.213000 ;
    PORT
      LAYER met3 ;
        RECT 0.000 206.760 0.600 207.360 ;
    END
  END Tile_X0Y1_FrameData[25]
  PIN Tile_X0Y1_FrameData[26]
    DIRECTION INPUT ;
    USE SIGNAL ;
    ANTENNAGATEAREA 0.247500 ;
    PORT
      LAYER met3 ;
        RECT 0.000 208.120 0.600 208.720 ;
    END
  END Tile_X0Y1_FrameData[26]
  PIN Tile_X0Y1_FrameData[27]
    DIRECTION INPUT ;
    USE SIGNAL ;
    ANTENNAGATEAREA 0.247500 ;
    PORT
      LAYER met3 ;
        RECT 0.000 209.480 0.600 210.080 ;
    END
  END Tile_X0Y1_FrameData[27]
  PIN Tile_X0Y1_FrameData[28]
    DIRECTION INPUT ;
    USE SIGNAL ;
    ANTENNAGATEAREA 0.247500 ;
    PORT
      LAYER met3 ;
        RECT 0.000 210.840 0.600 211.440 ;
    END
  END Tile_X0Y1_FrameData[28]
  PIN Tile_X0Y1_FrameData[29]
    DIRECTION INPUT ;
    USE SIGNAL ;
    ANTENNAGATEAREA 0.247500 ;
    PORT
      LAYER met3 ;
        RECT 0.000 212.200 0.600 212.800 ;
    END
  END Tile_X0Y1_FrameData[29]
  PIN Tile_X0Y1_FrameData[2]
    DIRECTION INPUT ;
    USE SIGNAL ;
    ANTENNAGATEAREA 0.213000 ;
    PORT
      LAYER met3 ;
        RECT 0.000 175.480 0.600 176.080 ;
    END
  END Tile_X0Y1_FrameData[2]
  PIN Tile_X0Y1_FrameData[30]
    DIRECTION INPUT ;
    USE SIGNAL ;
    ANTENNAGATEAREA 0.213000 ;
    PORT
      LAYER met3 ;
        RECT 0.000 213.560 0.600 214.160 ;
    END
  END Tile_X0Y1_FrameData[30]
  PIN Tile_X0Y1_FrameData[31]
    DIRECTION INPUT ;
    USE SIGNAL ;
    ANTENNAGATEAREA 0.213000 ;
    PORT
      LAYER met3 ;
        RECT 0.000 214.920 0.600 215.520 ;
    END
  END Tile_X0Y1_FrameData[31]
  PIN Tile_X0Y1_FrameData[3]
    DIRECTION INPUT ;
    USE SIGNAL ;
    ANTENNAGATEAREA 0.213000 ;
    PORT
      LAYER met3 ;
        RECT 0.000 176.840 0.600 177.440 ;
    END
  END Tile_X0Y1_FrameData[3]
  PIN Tile_X0Y1_FrameData[4]
    DIRECTION INPUT ;
    USE SIGNAL ;
    ANTENNAGATEAREA 0.213000 ;
    PORT
      LAYER met3 ;
        RECT 0.000 178.200 0.600 178.800 ;
    END
  END Tile_X0Y1_FrameData[4]
  PIN Tile_X0Y1_FrameData[5]
    DIRECTION INPUT ;
    USE SIGNAL ;
    ANTENNAGATEAREA 0.213000 ;
    PORT
      LAYER met3 ;
        RECT 0.000 179.560 0.600 180.160 ;
    END
  END Tile_X0Y1_FrameData[5]
  PIN Tile_X0Y1_FrameData[6]
    DIRECTION INPUT ;
    USE SIGNAL ;
    ANTENNAGATEAREA 0.213000 ;
    PORT
      LAYER met3 ;
        RECT 0.000 180.920 0.600 181.520 ;
    END
  END Tile_X0Y1_FrameData[6]
  PIN Tile_X0Y1_FrameData[7]
    DIRECTION INPUT ;
    USE SIGNAL ;
    ANTENNAGATEAREA 0.213000 ;
    PORT
      LAYER met3 ;
        RECT 0.000 182.280 0.600 182.880 ;
    END
  END Tile_X0Y1_FrameData[7]
  PIN Tile_X0Y1_FrameData[8]
    DIRECTION INPUT ;
    USE SIGNAL ;
    ANTENNAGATEAREA 0.247500 ;
    PORT
      LAYER met3 ;
        RECT 0.000 183.640 0.600 184.240 ;
    END
  END Tile_X0Y1_FrameData[8]
  PIN Tile_X0Y1_FrameData[9]
    DIRECTION INPUT ;
    USE SIGNAL ;
    ANTENNAGATEAREA 0.247500 ;
    PORT
      LAYER met3 ;
        RECT 0.000 185.000 0.600 185.600 ;
    END
  END Tile_X0Y1_FrameData[9]
  PIN Tile_X0Y1_FrameData_O[0]
    DIRECTION OUTPUT ;
    USE SIGNAL ;
    ANTENNADIFFAREA 0.445500 ;
    PORT
      LAYER met3 ;
        RECT 119.460 425.720 120.060 426.320 ;
    END
  END Tile_X0Y1_FrameData_O[0]
  PIN Tile_X0Y1_FrameData_O[10]
    DIRECTION OUTPUT ;
    USE SIGNAL ;
    ANTENNADIFFAREA 0.445500 ;
    PORT
      LAYER met3 ;
        RECT 119.460 452.920 120.060 453.520 ;
    END
  END Tile_X0Y1_FrameData_O[10]
  PIN Tile_X0Y1_FrameData_O[11]
    DIRECTION OUTPUT ;
    USE SIGNAL ;
    ANTENNADIFFAREA 0.445500 ;
    PORT
      LAYER met3 ;
        RECT 119.460 455.640 120.060 456.240 ;
    END
  END Tile_X0Y1_FrameData_O[11]
  PIN Tile_X0Y1_FrameData_O[12]
    DIRECTION OUTPUT ;
    USE SIGNAL ;
    ANTENNADIFFAREA 0.445500 ;
    PORT
      LAYER met3 ;
        RECT 119.460 458.360 120.060 458.960 ;
    END
  END Tile_X0Y1_FrameData_O[12]
  PIN Tile_X0Y1_FrameData_O[13]
    DIRECTION OUTPUT ;
    USE SIGNAL ;
    ANTENNADIFFAREA 0.445500 ;
    PORT
      LAYER met3 ;
        RECT 119.460 461.080 120.060 461.680 ;
    END
  END Tile_X0Y1_FrameData_O[13]
  PIN Tile_X0Y1_FrameData_O[14]
    DIRECTION OUTPUT ;
    USE SIGNAL ;
    ANTENNADIFFAREA 0.445500 ;
    PORT
      LAYER met3 ;
        RECT 119.460 463.800 120.060 464.400 ;
    END
  END Tile_X0Y1_FrameData_O[14]
  PIN Tile_X0Y1_FrameData_O[15]
    DIRECTION OUTPUT ;
    USE SIGNAL ;
    ANTENNADIFFAREA 0.445500 ;
    PORT
      LAYER met3 ;
        RECT 119.460 466.520 120.060 467.120 ;
    END
  END Tile_X0Y1_FrameData_O[15]
  PIN Tile_X0Y1_FrameData_O[16]
    DIRECTION OUTPUT ;
    USE SIGNAL ;
    ANTENNADIFFAREA 0.445500 ;
    PORT
      LAYER met3 ;
        RECT 119.460 469.240 120.060 469.840 ;
    END
  END Tile_X0Y1_FrameData_O[16]
  PIN Tile_X0Y1_FrameData_O[17]
    DIRECTION OUTPUT ;
    USE SIGNAL ;
    ANTENNADIFFAREA 0.445500 ;
    PORT
      LAYER met3 ;
        RECT 119.460 471.960 120.060 472.560 ;
    END
  END Tile_X0Y1_FrameData_O[17]
  PIN Tile_X0Y1_FrameData_O[18]
    DIRECTION OUTPUT ;
    USE SIGNAL ;
    ANTENNADIFFAREA 0.445500 ;
    PORT
      LAYER met3 ;
        RECT 119.460 474.680 120.060 475.280 ;
    END
  END Tile_X0Y1_FrameData_O[18]
  PIN Tile_X0Y1_FrameData_O[19]
    DIRECTION OUTPUT ;
    USE SIGNAL ;
    ANTENNADIFFAREA 0.445500 ;
    PORT
      LAYER met3 ;
        RECT 119.460 477.400 120.060 478.000 ;
    END
  END Tile_X0Y1_FrameData_O[19]
  PIN Tile_X0Y1_FrameData_O[1]
    DIRECTION OUTPUT ;
    USE SIGNAL ;
    ANTENNADIFFAREA 0.445500 ;
    PORT
      LAYER met3 ;
        RECT 119.460 428.440 120.060 429.040 ;
    END
  END Tile_X0Y1_FrameData_O[1]
  PIN Tile_X0Y1_FrameData_O[20]
    DIRECTION OUTPUT ;
    USE SIGNAL ;
    ANTENNADIFFAREA 0.445500 ;
    PORT
      LAYER met3 ;
        RECT 119.460 480.120 120.060 480.720 ;
    END
  END Tile_X0Y1_FrameData_O[20]
  PIN Tile_X0Y1_FrameData_O[21]
    DIRECTION OUTPUT ;
    USE SIGNAL ;
    ANTENNADIFFAREA 0.445500 ;
    PORT
      LAYER met3 ;
        RECT 119.460 482.840 120.060 483.440 ;
    END
  END Tile_X0Y1_FrameData_O[21]
  PIN Tile_X0Y1_FrameData_O[22]
    DIRECTION OUTPUT ;
    USE SIGNAL ;
    ANTENNADIFFAREA 0.445500 ;
    PORT
      LAYER met3 ;
        RECT 119.460 485.560 120.060 486.160 ;
    END
  END Tile_X0Y1_FrameData_O[22]
  PIN Tile_X0Y1_FrameData_O[23]
    DIRECTION OUTPUT ;
    USE SIGNAL ;
    ANTENNADIFFAREA 0.445500 ;
    PORT
      LAYER met3 ;
        RECT 119.460 488.280 120.060 488.880 ;
    END
  END Tile_X0Y1_FrameData_O[23]
  PIN Tile_X0Y1_FrameData_O[24]
    DIRECTION OUTPUT ;
    USE SIGNAL ;
    ANTENNADIFFAREA 0.445500 ;
    PORT
      LAYER met3 ;
        RECT 119.460 491.000 120.060 491.600 ;
    END
  END Tile_X0Y1_FrameData_O[24]
  PIN Tile_X0Y1_FrameData_O[25]
    DIRECTION OUTPUT ;
    USE SIGNAL ;
    ANTENNADIFFAREA 0.445500 ;
    PORT
      LAYER met3 ;
        RECT 119.460 493.720 120.060 494.320 ;
    END
  END Tile_X0Y1_FrameData_O[25]
  PIN Tile_X0Y1_FrameData_O[26]
    DIRECTION OUTPUT ;
    USE SIGNAL ;
    ANTENNADIFFAREA 0.445500 ;
    PORT
      LAYER met3 ;
        RECT 119.460 496.440 120.060 497.040 ;
    END
  END Tile_X0Y1_FrameData_O[26]
  PIN Tile_X0Y1_FrameData_O[27]
    DIRECTION OUTPUT ;
    USE SIGNAL ;
    ANTENNADIFFAREA 0.445500 ;
    PORT
      LAYER met3 ;
        RECT 119.460 499.160 120.060 499.760 ;
    END
  END Tile_X0Y1_FrameData_O[27]
  PIN Tile_X0Y1_FrameData_O[28]
    DIRECTION OUTPUT ;
    USE SIGNAL ;
    ANTENNADIFFAREA 0.445500 ;
    PORT
      LAYER met3 ;
        RECT 119.460 501.880 120.060 502.480 ;
    END
  END Tile_X0Y1_FrameData_O[28]
  PIN Tile_X0Y1_FrameData_O[29]
    DIRECTION OUTPUT ;
    USE SIGNAL ;
    ANTENNADIFFAREA 0.445500 ;
    PORT
      LAYER met3 ;
        RECT 119.460 504.600 120.060 505.200 ;
    END
  END Tile_X0Y1_FrameData_O[29]
  PIN Tile_X0Y1_FrameData_O[2]
    DIRECTION OUTPUT ;
    USE SIGNAL ;
    ANTENNADIFFAREA 0.445500 ;
    PORT
      LAYER met3 ;
        RECT 119.460 431.160 120.060 431.760 ;
    END
  END Tile_X0Y1_FrameData_O[2]
  PIN Tile_X0Y1_FrameData_O[30]
    DIRECTION OUTPUT ;
    USE SIGNAL ;
    ANTENNADIFFAREA 0.445500 ;
    PORT
      LAYER met3 ;
        RECT 119.460 507.320 120.060 507.920 ;
    END
  END Tile_X0Y1_FrameData_O[30]
  PIN Tile_X0Y1_FrameData_O[31]
    DIRECTION OUTPUT ;
    USE SIGNAL ;
    ANTENNADIFFAREA 0.445500 ;
    PORT
      LAYER met3 ;
        RECT 119.460 510.040 120.060 510.640 ;
    END
  END Tile_X0Y1_FrameData_O[31]
  PIN Tile_X0Y1_FrameData_O[3]
    DIRECTION OUTPUT ;
    USE SIGNAL ;
    ANTENNADIFFAREA 0.445500 ;
    PORT
      LAYER met3 ;
        RECT 119.460 433.880 120.060 434.480 ;
    END
  END Tile_X0Y1_FrameData_O[3]
  PIN Tile_X0Y1_FrameData_O[4]
    DIRECTION OUTPUT ;
    USE SIGNAL ;
    ANTENNADIFFAREA 0.445500 ;
    PORT
      LAYER met3 ;
        RECT 119.460 436.600 120.060 437.200 ;
    END
  END Tile_X0Y1_FrameData_O[4]
  PIN Tile_X0Y1_FrameData_O[5]
    DIRECTION OUTPUT ;
    USE SIGNAL ;
    ANTENNADIFFAREA 0.445500 ;
    PORT
      LAYER met3 ;
        RECT 119.460 439.320 120.060 439.920 ;
    END
  END Tile_X0Y1_FrameData_O[5]
  PIN Tile_X0Y1_FrameData_O[6]
    DIRECTION OUTPUT ;
    USE SIGNAL ;
    ANTENNADIFFAREA 0.445500 ;
    PORT
      LAYER met3 ;
        RECT 119.460 442.040 120.060 442.640 ;
    END
  END Tile_X0Y1_FrameData_O[6]
  PIN Tile_X0Y1_FrameData_O[7]
    DIRECTION OUTPUT ;
    USE SIGNAL ;
    ANTENNADIFFAREA 0.445500 ;
    PORT
      LAYER met3 ;
        RECT 119.460 444.760 120.060 445.360 ;
    END
  END Tile_X0Y1_FrameData_O[7]
  PIN Tile_X0Y1_FrameData_O[8]
    DIRECTION OUTPUT ;
    USE SIGNAL ;
    ANTENNADIFFAREA 0.445500 ;
    PORT
      LAYER met3 ;
        RECT 119.460 447.480 120.060 448.080 ;
    END
  END Tile_X0Y1_FrameData_O[8]
  PIN Tile_X0Y1_FrameData_O[9]
    DIRECTION OUTPUT ;
    USE SIGNAL ;
    ANTENNADIFFAREA 0.445500 ;
    PORT
      LAYER met3 ;
        RECT 119.460 450.200 120.060 450.800 ;
    END
  END Tile_X0Y1_FrameData_O[9]
  PIN Tile_X0Y1_FrameStrobe[0]
    DIRECTION INPUT ;
    USE SIGNAL ;
    ANTENNAGATEAREA 0.711000 ;
    PORT
      LAYER met2 ;
        RECT 84.730 0.000 85.010 0.280 ;
    END
  END Tile_X0Y1_FrameStrobe[0]
  PIN Tile_X0Y1_FrameStrobe[10]
    DIRECTION INPUT ;
    USE SIGNAL ;
    ANTENNAGATEAREA 0.495000 ;
    PORT
      LAYER met2 ;
        RECT 93.930 0.000 94.210 0.280 ;
    END
  END Tile_X0Y1_FrameStrobe[10]
  PIN Tile_X0Y1_FrameStrobe[11]
    DIRECTION INPUT ;
    USE SIGNAL ;
    ANTENNAGATEAREA 0.196500 ;
    PORT
      LAYER met2 ;
        RECT 94.850 0.000 95.130 0.280 ;
    END
  END Tile_X0Y1_FrameStrobe[11]
  PIN Tile_X0Y1_FrameStrobe[12]
    DIRECTION INPUT ;
    USE SIGNAL ;
    ANTENNAGATEAREA 0.495000 ;
    PORT
      LAYER met2 ;
        RECT 95.770 0.000 96.050 0.280 ;
    END
  END Tile_X0Y1_FrameStrobe[12]
  PIN Tile_X0Y1_FrameStrobe[13]
    DIRECTION INPUT ;
    USE SIGNAL ;
    ANTENNAGATEAREA 0.196500 ;
    PORT
      LAYER met2 ;
        RECT 96.690 0.000 96.970 0.280 ;
    END
  END Tile_X0Y1_FrameStrobe[13]
  PIN Tile_X0Y1_FrameStrobe[14]
    DIRECTION INPUT ;
    USE SIGNAL ;
    ANTENNAGATEAREA 0.495000 ;
    PORT
      LAYER met2 ;
        RECT 97.610 0.000 97.890 0.280 ;
    END
  END Tile_X0Y1_FrameStrobe[14]
  PIN Tile_X0Y1_FrameStrobe[15]
    DIRECTION INPUT ;
    USE SIGNAL ;
    ANTENNAGATEAREA 0.196500 ;
    PORT
      LAYER met2 ;
        RECT 98.530 0.000 98.810 0.280 ;
    END
  END Tile_X0Y1_FrameStrobe[15]
  PIN Tile_X0Y1_FrameStrobe[16]
    DIRECTION INPUT ;
    USE SIGNAL ;
    ANTENNAGATEAREA 0.196500 ;
    PORT
      LAYER met2 ;
        RECT 99.450 0.000 99.730 0.280 ;
    END
  END Tile_X0Y1_FrameStrobe[16]
  PIN Tile_X0Y1_FrameStrobe[17]
    DIRECTION INPUT ;
    USE SIGNAL ;
    ANTENNAGATEAREA 0.196500 ;
    PORT
      LAYER met2 ;
        RECT 100.370 0.000 100.650 0.280 ;
    END
  END Tile_X0Y1_FrameStrobe[17]
  PIN Tile_X0Y1_FrameStrobe[18]
    DIRECTION INPUT ;
    USE SIGNAL ;
    ANTENNAGATEAREA 0.495000 ;
    PORT
      LAYER met2 ;
        RECT 101.290 0.000 101.570 0.280 ;
    END
  END Tile_X0Y1_FrameStrobe[18]
  PIN Tile_X0Y1_FrameStrobe[19]
    DIRECTION INPUT ;
    USE SIGNAL ;
    ANTENNAGATEAREA 0.495000 ;
    PORT
      LAYER met2 ;
        RECT 102.210 0.000 102.490 0.280 ;
    END
  END Tile_X0Y1_FrameStrobe[19]
  PIN Tile_X0Y1_FrameStrobe[1]
    DIRECTION INPUT ;
    USE SIGNAL ;
    ANTENNAGATEAREA 0.426000 ;
    PORT
      LAYER met2 ;
        RECT 85.650 0.000 85.930 0.280 ;
    END
  END Tile_X0Y1_FrameStrobe[1]
  PIN Tile_X0Y1_FrameStrobe[2]
    DIRECTION INPUT ;
    USE SIGNAL ;
    ANTENNAGATEAREA 0.213000 ;
    PORT
      LAYER met2 ;
        RECT 86.570 0.000 86.850 0.280 ;
    END
  END Tile_X0Y1_FrameStrobe[2]
  PIN Tile_X0Y1_FrameStrobe[3]
    DIRECTION INPUT ;
    USE SIGNAL ;
    ANTENNAGATEAREA 0.372000 ;
    PORT
      LAYER met2 ;
        RECT 87.490 0.000 87.770 0.280 ;
    END
  END Tile_X0Y1_FrameStrobe[3]
  PIN Tile_X0Y1_FrameStrobe[4]
    DIRECTION INPUT ;
    USE SIGNAL ;
    ANTENNAGATEAREA 0.531000 ;
    PORT
      LAYER met2 ;
        RECT 88.410 0.000 88.690 0.280 ;
    END
  END Tile_X0Y1_FrameStrobe[4]
  PIN Tile_X0Y1_FrameStrobe[5]
    DIRECTION INPUT ;
    USE SIGNAL ;
    ANTENNAGATEAREA 0.339000 ;
    PORT
      LAYER met2 ;
        RECT 89.330 0.000 89.610 0.280 ;
    END
  END Tile_X0Y1_FrameStrobe[5]
  PIN Tile_X0Y1_FrameStrobe[6]
    DIRECTION INPUT ;
    USE SIGNAL ;
    ANTENNAGATEAREA 0.159000 ;
    PORT
      LAYER met2 ;
        RECT 90.250 0.000 90.530 0.280 ;
    END
  END Tile_X0Y1_FrameStrobe[6]
  PIN Tile_X0Y1_FrameStrobe[7]
    DIRECTION INPUT ;
    USE SIGNAL ;
    ANTENNAGATEAREA 0.426000 ;
    PORT
      LAYER met2 ;
        RECT 91.170 0.000 91.450 0.280 ;
    END
  END Tile_X0Y1_FrameStrobe[7]
  PIN Tile_X0Y1_FrameStrobe[8]
    DIRECTION INPUT ;
    USE SIGNAL ;
    ANTENNAGATEAREA 0.690000 ;
    PORT
      LAYER met2 ;
        RECT 92.090 0.000 92.370 0.280 ;
    END
  END Tile_X0Y1_FrameStrobe[8]
  PIN Tile_X0Y1_FrameStrobe[9]
    DIRECTION INPUT ;
    USE SIGNAL ;
    ANTENNAGATEAREA 0.495000 ;
    PORT
      LAYER met2 ;
        RECT 93.010 0.000 93.290 0.280 ;
    END
  END Tile_X0Y1_FrameStrobe[9]
  PIN Tile_X0Y1_N1END[0]
    DIRECTION INPUT ;
    USE SIGNAL ;
    ANTENNAGATEAREA 0.159000 ;
    PORT
      LAYER met2 ;
        RECT 17.570 0.000 17.850 0.280 ;
    END
  END Tile_X0Y1_N1END[0]
  PIN Tile_X0Y1_N1END[1]
    DIRECTION INPUT ;
    USE SIGNAL ;
    ANTENNAGATEAREA 0.159000 ;
    PORT
      LAYER met2 ;
        RECT 18.490 0.000 18.770 0.280 ;
    END
  END Tile_X0Y1_N1END[1]
  PIN Tile_X0Y1_N1END[2]
    DIRECTION INPUT ;
    USE SIGNAL ;
    ANTENNAGATEAREA 0.159000 ;
    PORT
      LAYER met2 ;
        RECT 19.410 0.000 19.690 0.280 ;
    END
  END Tile_X0Y1_N1END[2]
  PIN Tile_X0Y1_N1END[3]
    DIRECTION INPUT ;
    USE SIGNAL ;
    ANTENNAGATEAREA 0.213000 ;
    PORT
      LAYER met2 ;
        RECT 20.330 0.000 20.610 0.280 ;
    END
  END Tile_X0Y1_N1END[3]
  PIN Tile_X0Y1_N2END[0]
    DIRECTION INPUT ;
    USE SIGNAL ;
    ANTENNAGATEAREA 0.213000 ;
    PORT
      LAYER met2 ;
        RECT 28.610 0.000 28.890 0.280 ;
    END
  END Tile_X0Y1_N2END[0]
  PIN Tile_X0Y1_N2END[1]
    DIRECTION INPUT ;
    USE SIGNAL ;
    ANTENNAGATEAREA 0.213000 ;
    PORT
      LAYER met2 ;
        RECT 29.530 0.000 29.810 0.280 ;
    END
  END Tile_X0Y1_N2END[1]
  PIN Tile_X0Y1_N2END[2]
    DIRECTION INPUT ;
    USE SIGNAL ;
    ANTENNAGATEAREA 0.159000 ;
    PORT
      LAYER met2 ;
        RECT 30.450 0.000 30.730 0.280 ;
    END
  END Tile_X0Y1_N2END[2]
  PIN Tile_X0Y1_N2END[3]
    DIRECTION INPUT ;
    USE SIGNAL ;
    ANTENNAGATEAREA 0.159000 ;
    PORT
      LAYER met2 ;
        RECT 31.370 0.000 31.650 0.280 ;
    END
  END Tile_X0Y1_N2END[3]
  PIN Tile_X0Y1_N2END[4]
    DIRECTION INPUT ;
    USE SIGNAL ;
    ANTENNAGATEAREA 0.213000 ;
    PORT
      LAYER met2 ;
        RECT 32.290 0.000 32.570 0.280 ;
    END
  END Tile_X0Y1_N2END[4]
  PIN Tile_X0Y1_N2END[5]
    DIRECTION INPUT ;
    USE SIGNAL ;
    ANTENNAGATEAREA 0.213000 ;
    PORT
      LAYER met2 ;
        RECT 33.210 0.000 33.490 0.280 ;
    END
  END Tile_X0Y1_N2END[5]
  PIN Tile_X0Y1_N2END[6]
    DIRECTION INPUT ;
    USE SIGNAL ;
    ANTENNAGATEAREA 0.213000 ;
    PORT
      LAYER met2 ;
        RECT 34.130 0.000 34.410 0.280 ;
    END
  END Tile_X0Y1_N2END[6]
  PIN Tile_X0Y1_N2END[7]
    DIRECTION INPUT ;
    USE SIGNAL ;
    ANTENNAGATEAREA 0.213000 ;
    PORT
      LAYER met2 ;
        RECT 35.050 0.000 35.330 0.280 ;
    END
  END Tile_X0Y1_N2END[7]
  PIN Tile_X0Y1_N2MID[0]
    DIRECTION INPUT ;
    USE SIGNAL ;
    ANTENNAGATEAREA 0.213000 ;
    PORT
      LAYER met2 ;
        RECT 21.250 0.000 21.530 0.280 ;
    END
  END Tile_X0Y1_N2MID[0]
  PIN Tile_X0Y1_N2MID[1]
    DIRECTION INPUT ;
    USE SIGNAL ;
    ANTENNAGATEAREA 0.159000 ;
    PORT
      LAYER met2 ;
        RECT 22.170 0.000 22.450 0.280 ;
    END
  END Tile_X0Y1_N2MID[1]
  PIN Tile_X0Y1_N2MID[2]
    DIRECTION INPUT ;
    USE SIGNAL ;
    ANTENNAGATEAREA 0.159000 ;
    PORT
      LAYER met2 ;
        RECT 23.090 0.000 23.370 0.280 ;
    END
  END Tile_X0Y1_N2MID[2]
  PIN Tile_X0Y1_N2MID[3]
    DIRECTION INPUT ;
    USE SIGNAL ;
    ANTENNAGATEAREA 0.159000 ;
    PORT
      LAYER met2 ;
        RECT 24.010 0.000 24.290 0.280 ;
    END
  END Tile_X0Y1_N2MID[3]
  PIN Tile_X0Y1_N2MID[4]
    DIRECTION INPUT ;
    USE SIGNAL ;
    ANTENNAGATEAREA 0.213000 ;
    PORT
      LAYER met2 ;
        RECT 24.930 0.000 25.210 0.280 ;
    END
  END Tile_X0Y1_N2MID[4]
  PIN Tile_X0Y1_N2MID[5]
    DIRECTION INPUT ;
    USE SIGNAL ;
    ANTENNAGATEAREA 0.159000 ;
    PORT
      LAYER met2 ;
        RECT 25.850 0.000 26.130 0.280 ;
    END
  END Tile_X0Y1_N2MID[5]
  PIN Tile_X0Y1_N2MID[6]
    DIRECTION INPUT ;
    USE SIGNAL ;
    ANTENNAGATEAREA 0.159000 ;
    PORT
      LAYER met2 ;
        RECT 26.770 0.000 27.050 0.280 ;
    END
  END Tile_X0Y1_N2MID[6]
  PIN Tile_X0Y1_N2MID[7]
    DIRECTION INPUT ;
    USE SIGNAL ;
    ANTENNAGATEAREA 0.213000 ;
    PORT
      LAYER met2 ;
        RECT 27.690 0.000 27.970 0.280 ;
    END
  END Tile_X0Y1_N2MID[7]
  PIN Tile_X0Y1_N4END[0]
    DIRECTION INPUT ;
    USE SIGNAL ;
    ANTENNAGATEAREA 0.213000 ;
    PORT
      LAYER met2 ;
        RECT 35.970 0.000 36.250 0.280 ;
    END
  END Tile_X0Y1_N4END[0]
  PIN Tile_X0Y1_N4END[10]
    DIRECTION INPUT ;
    USE SIGNAL ;
    ANTENNAGATEAREA 0.196500 ;
    PORT
      LAYER met2 ;
        RECT 45.170 0.000 45.450 0.280 ;
    END
  END Tile_X0Y1_N4END[10]
  PIN Tile_X0Y1_N4END[11]
    DIRECTION INPUT ;
    USE SIGNAL ;
    ANTENNAGATEAREA 0.196500 ;
    PORT
      LAYER met2 ;
        RECT 46.090 0.000 46.370 0.280 ;
    END
  END Tile_X0Y1_N4END[11]
  PIN Tile_X0Y1_N4END[12]
    DIRECTION INPUT ;
    USE SIGNAL ;
    ANTENNAGATEAREA 0.196500 ;
    PORT
      LAYER met2 ;
        RECT 47.010 0.000 47.290 0.280 ;
    END
  END Tile_X0Y1_N4END[12]
  PIN Tile_X0Y1_N4END[13]
    DIRECTION INPUT ;
    USE SIGNAL ;
    ANTENNAGATEAREA 0.495000 ;
    PORT
      LAYER met2 ;
        RECT 47.930 0.000 48.210 0.280 ;
    END
  END Tile_X0Y1_N4END[13]
  PIN Tile_X0Y1_N4END[14]
    DIRECTION INPUT ;
    USE SIGNAL ;
    ANTENNAGATEAREA 0.495000 ;
    PORT
      LAYER met2 ;
        RECT 48.850 0.000 49.130 0.280 ;
    END
  END Tile_X0Y1_N4END[14]
  PIN Tile_X0Y1_N4END[15]
    DIRECTION INPUT ;
    USE SIGNAL ;
    ANTENNAGATEAREA 0.495000 ;
    PORT
      LAYER met2 ;
        RECT 49.770 0.000 50.050 0.280 ;
    END
  END Tile_X0Y1_N4END[15]
  PIN Tile_X0Y1_N4END[1]
    DIRECTION INPUT ;
    USE SIGNAL ;
    ANTENNAGATEAREA 0.213000 ;
    PORT
      LAYER met2 ;
        RECT 36.890 0.000 37.170 0.280 ;
    END
  END Tile_X0Y1_N4END[1]
  PIN Tile_X0Y1_N4END[2]
    DIRECTION INPUT ;
    USE SIGNAL ;
    ANTENNAGATEAREA 0.213000 ;
    PORT
      LAYER met2 ;
        RECT 37.810 0.000 38.090 0.280 ;
    END
  END Tile_X0Y1_N4END[2]
  PIN Tile_X0Y1_N4END[3]
    DIRECTION INPUT ;
    USE SIGNAL ;
    ANTENNAGATEAREA 0.213000 ;
    PORT
      LAYER met2 ;
        RECT 38.730 0.000 39.010 0.280 ;
    END
  END Tile_X0Y1_N4END[3]
  PIN Tile_X0Y1_N4END[4]
    DIRECTION INPUT ;
    USE SIGNAL ;
    ANTENNAGATEAREA 0.213000 ;
    PORT
      LAYER met2 ;
        RECT 39.650 0.000 39.930 0.280 ;
    END
  END Tile_X0Y1_N4END[4]
  PIN Tile_X0Y1_N4END[5]
    DIRECTION INPUT ;
    USE SIGNAL ;
    ANTENNAGATEAREA 0.213000 ;
    PORT
      LAYER met2 ;
        RECT 40.570 0.000 40.850 0.280 ;
    END
  END Tile_X0Y1_N4END[5]
  PIN Tile_X0Y1_N4END[6]
    DIRECTION INPUT ;
    USE SIGNAL ;
    ANTENNAGATEAREA 0.213000 ;
    PORT
      LAYER met2 ;
        RECT 41.490 0.000 41.770 0.280 ;
    END
  END Tile_X0Y1_N4END[6]
  PIN Tile_X0Y1_N4END[7]
    DIRECTION INPUT ;
    USE SIGNAL ;
    ANTENNAGATEAREA 0.213000 ;
    PORT
      LAYER met2 ;
        RECT 42.410 0.000 42.690 0.280 ;
    END
  END Tile_X0Y1_N4END[7]
  PIN Tile_X0Y1_N4END[8]
    DIRECTION INPUT ;
    USE SIGNAL ;
    ANTENNAGATEAREA 0.196500 ;
    PORT
      LAYER met2 ;
        RECT 43.330 0.000 43.610 0.280 ;
    END
  END Tile_X0Y1_N4END[8]
  PIN Tile_X0Y1_N4END[9]
    DIRECTION INPUT ;
    USE SIGNAL ;
    ANTENNAGATEAREA 0.495000 ;
    PORT
      LAYER met2 ;
        RECT 44.250 0.000 44.530 0.280 ;
    END
  END Tile_X0Y1_N4END[9]
  PIN Tile_X0Y1_S1BEG[0]
    DIRECTION OUTPUT ;
    USE SIGNAL ;
    ANTENNADIFFAREA 0.445500 ;
    PORT
      LAYER met2 ;
        RECT 50.690 0.000 50.970 0.280 ;
    END
  END Tile_X0Y1_S1BEG[0]
  PIN Tile_X0Y1_S1BEG[1]
    DIRECTION OUTPUT ;
    USE SIGNAL ;
    ANTENNADIFFAREA 0.445500 ;
    PORT
      LAYER met2 ;
        RECT 51.610 0.000 51.890 0.280 ;
    END
  END Tile_X0Y1_S1BEG[1]
  PIN Tile_X0Y1_S1BEG[2]
    DIRECTION OUTPUT ;
    USE SIGNAL ;
    ANTENNADIFFAREA 0.445500 ;
    PORT
      LAYER met2 ;
        RECT 52.530 0.000 52.810 0.280 ;
    END
  END Tile_X0Y1_S1BEG[2]
  PIN Tile_X0Y1_S1BEG[3]
    DIRECTION OUTPUT ;
    USE SIGNAL ;
    ANTENNADIFFAREA 0.445500 ;
    PORT
      LAYER met2 ;
        RECT 53.450 0.000 53.730 0.280 ;
    END
  END Tile_X0Y1_S1BEG[3]
  PIN Tile_X0Y1_S2BEG[0]
    DIRECTION OUTPUT ;
    USE SIGNAL ;
    ANTENNADIFFAREA 0.445500 ;
    PORT
      LAYER met2 ;
        RECT 54.370 0.000 54.650 0.280 ;
    END
  END Tile_X0Y1_S2BEG[0]
  PIN Tile_X0Y1_S2BEG[1]
    DIRECTION OUTPUT ;
    USE SIGNAL ;
    ANTENNADIFFAREA 0.445500 ;
    PORT
      LAYER met2 ;
        RECT 55.290 0.000 55.570 0.280 ;
    END
  END Tile_X0Y1_S2BEG[1]
  PIN Tile_X0Y1_S2BEG[2]
    DIRECTION OUTPUT ;
    USE SIGNAL ;
    ANTENNADIFFAREA 0.445500 ;
    PORT
      LAYER met2 ;
        RECT 56.210 0.000 56.490 0.280 ;
    END
  END Tile_X0Y1_S2BEG[2]
  PIN Tile_X0Y1_S2BEG[3]
    DIRECTION OUTPUT ;
    USE SIGNAL ;
    ANTENNADIFFAREA 0.445500 ;
    PORT
      LAYER met2 ;
        RECT 57.130 0.000 57.410 0.280 ;
    END
  END Tile_X0Y1_S2BEG[3]
  PIN Tile_X0Y1_S2BEG[4]
    DIRECTION OUTPUT ;
    USE SIGNAL ;
    ANTENNADIFFAREA 0.445500 ;
    PORT
      LAYER met2 ;
        RECT 58.050 0.000 58.330 0.280 ;
    END
  END Tile_X0Y1_S2BEG[4]
  PIN Tile_X0Y1_S2BEG[5]
    DIRECTION OUTPUT ;
    USE SIGNAL ;
    ANTENNADIFFAREA 0.445500 ;
    PORT
      LAYER met2 ;
        RECT 58.970 0.000 59.250 0.280 ;
    END
  END Tile_X0Y1_S2BEG[5]
  PIN Tile_X0Y1_S2BEG[6]
    DIRECTION OUTPUT ;
    USE SIGNAL ;
    ANTENNADIFFAREA 0.445500 ;
    PORT
      LAYER met2 ;
        RECT 59.890 0.000 60.170 0.280 ;
    END
  END Tile_X0Y1_S2BEG[6]
  PIN Tile_X0Y1_S2BEG[7]
    DIRECTION OUTPUT ;
    USE SIGNAL ;
    ANTENNADIFFAREA 0.445500 ;
    PORT
      LAYER met2 ;
        RECT 60.810 0.000 61.090 0.280 ;
    END
  END Tile_X0Y1_S2BEG[7]
  PIN Tile_X0Y1_S2BEGb[0]
    DIRECTION OUTPUT ;
    USE SIGNAL ;
    ANTENNADIFFAREA 0.445500 ;
    PORT
      LAYER met2 ;
        RECT 61.730 0.000 62.010 0.280 ;
    END
  END Tile_X0Y1_S2BEGb[0]
  PIN Tile_X0Y1_S2BEGb[1]
    DIRECTION OUTPUT ;
    USE SIGNAL ;
    ANTENNADIFFAREA 0.445500 ;
    PORT
      LAYER met2 ;
        RECT 62.650 0.000 62.930 0.280 ;
    END
  END Tile_X0Y1_S2BEGb[1]
  PIN Tile_X0Y1_S2BEGb[2]
    DIRECTION OUTPUT ;
    USE SIGNAL ;
    ANTENNADIFFAREA 0.445500 ;
    PORT
      LAYER met2 ;
        RECT 63.570 0.000 63.850 0.280 ;
    END
  END Tile_X0Y1_S2BEGb[2]
  PIN Tile_X0Y1_S2BEGb[3]
    DIRECTION OUTPUT ;
    USE SIGNAL ;
    ANTENNADIFFAREA 0.445500 ;
    PORT
      LAYER met2 ;
        RECT 64.490 0.000 64.770 0.280 ;
    END
  END Tile_X0Y1_S2BEGb[3]
  PIN Tile_X0Y1_S2BEGb[4]
    DIRECTION OUTPUT ;
    USE SIGNAL ;
    ANTENNADIFFAREA 0.445500 ;
    PORT
      LAYER met2 ;
        RECT 65.410 0.000 65.690 0.280 ;
    END
  END Tile_X0Y1_S2BEGb[4]
  PIN Tile_X0Y1_S2BEGb[5]
    DIRECTION OUTPUT ;
    USE SIGNAL ;
    ANTENNADIFFAREA 0.445500 ;
    PORT
      LAYER met2 ;
        RECT 66.330 0.000 66.610 0.280 ;
    END
  END Tile_X0Y1_S2BEGb[5]
  PIN Tile_X0Y1_S2BEGb[6]
    DIRECTION OUTPUT ;
    USE SIGNAL ;
    ANTENNADIFFAREA 0.445500 ;
    PORT
      LAYER met2 ;
        RECT 67.250 0.000 67.530 0.280 ;
    END
  END Tile_X0Y1_S2BEGb[6]
  PIN Tile_X0Y1_S2BEGb[7]
    DIRECTION OUTPUT ;
    USE SIGNAL ;
    ANTENNADIFFAREA 0.445500 ;
    PORT
      LAYER met2 ;
        RECT 68.170 0.000 68.450 0.280 ;
    END
  END Tile_X0Y1_S2BEGb[7]
  PIN Tile_X0Y1_S4BEG[0]
    DIRECTION OUTPUT ;
    USE SIGNAL ;
    ANTENNADIFFAREA 0.445500 ;
    PORT
      LAYER met2 ;
        RECT 69.090 0.000 69.370 0.280 ;
    END
  END Tile_X0Y1_S4BEG[0]
  PIN Tile_X0Y1_S4BEG[10]
    DIRECTION OUTPUT ;
    USE SIGNAL ;
    ANTENNADIFFAREA 0.445500 ;
    PORT
      LAYER met2 ;
        RECT 78.290 0.000 78.570 0.280 ;
    END
  END Tile_X0Y1_S4BEG[10]
  PIN Tile_X0Y1_S4BEG[11]
    DIRECTION OUTPUT ;
    USE SIGNAL ;
    ANTENNADIFFAREA 0.445500 ;
    PORT
      LAYER met2 ;
        RECT 79.210 0.000 79.490 0.280 ;
    END
  END Tile_X0Y1_S4BEG[11]
  PIN Tile_X0Y1_S4BEG[12]
    DIRECTION OUTPUT ;
    USE SIGNAL ;
    ANTENNADIFFAREA 0.445500 ;
    PORT
      LAYER met2 ;
        RECT 80.130 0.000 80.410 0.280 ;
    END
  END Tile_X0Y1_S4BEG[12]
  PIN Tile_X0Y1_S4BEG[13]
    DIRECTION OUTPUT ;
    USE SIGNAL ;
    ANTENNADIFFAREA 0.445500 ;
    PORT
      LAYER met2 ;
        RECT 81.050 0.000 81.330 0.280 ;
    END
  END Tile_X0Y1_S4BEG[13]
  PIN Tile_X0Y1_S4BEG[14]
    DIRECTION OUTPUT ;
    USE SIGNAL ;
    ANTENNADIFFAREA 0.445500 ;
    PORT
      LAYER met2 ;
        RECT 81.970 0.000 82.250 0.280 ;
    END
  END Tile_X0Y1_S4BEG[14]
  PIN Tile_X0Y1_S4BEG[15]
    DIRECTION OUTPUT ;
    USE SIGNAL ;
    ANTENNADIFFAREA 0.445500 ;
    PORT
      LAYER met2 ;
        RECT 82.890 0.000 83.170 0.280 ;
    END
  END Tile_X0Y1_S4BEG[15]
  PIN Tile_X0Y1_S4BEG[1]
    DIRECTION OUTPUT ;
    USE SIGNAL ;
    ANTENNADIFFAREA 0.445500 ;
    PORT
      LAYER met2 ;
        RECT 70.010 0.000 70.290 0.280 ;
    END
  END Tile_X0Y1_S4BEG[1]
  PIN Tile_X0Y1_S4BEG[2]
    DIRECTION OUTPUT ;
    USE SIGNAL ;
    ANTENNADIFFAREA 0.445500 ;
    PORT
      LAYER met2 ;
        RECT 70.930 0.000 71.210 0.280 ;
    END
  END Tile_X0Y1_S4BEG[2]
  PIN Tile_X0Y1_S4BEG[3]
    DIRECTION OUTPUT ;
    USE SIGNAL ;
    ANTENNADIFFAREA 0.445500 ;
    PORT
      LAYER met2 ;
        RECT 71.850 0.000 72.130 0.280 ;
    END
  END Tile_X0Y1_S4BEG[3]
  PIN Tile_X0Y1_S4BEG[4]
    DIRECTION OUTPUT ;
    USE SIGNAL ;
    ANTENNADIFFAREA 0.445500 ;
    PORT
      LAYER met2 ;
        RECT 72.770 0.000 73.050 0.280 ;
    END
  END Tile_X0Y1_S4BEG[4]
  PIN Tile_X0Y1_S4BEG[5]
    DIRECTION OUTPUT ;
    USE SIGNAL ;
    ANTENNADIFFAREA 0.445500 ;
    PORT
      LAYER met2 ;
        RECT 73.690 0.000 73.970 0.280 ;
    END
  END Tile_X0Y1_S4BEG[5]
  PIN Tile_X0Y1_S4BEG[6]
    DIRECTION OUTPUT ;
    USE SIGNAL ;
    ANTENNADIFFAREA 0.445500 ;
    PORT
      LAYER met2 ;
        RECT 74.610 0.000 74.890 0.280 ;
    END
  END Tile_X0Y1_S4BEG[6]
  PIN Tile_X0Y1_S4BEG[7]
    DIRECTION OUTPUT ;
    USE SIGNAL ;
    ANTENNADIFFAREA 0.445500 ;
    PORT
      LAYER met2 ;
        RECT 75.530 0.000 75.810 0.280 ;
    END
  END Tile_X0Y1_S4BEG[7]
  PIN Tile_X0Y1_S4BEG[8]
    DIRECTION OUTPUT ;
    USE SIGNAL ;
    ANTENNADIFFAREA 0.445500 ;
    PORT
      LAYER met2 ;
        RECT 76.450 0.000 76.730 0.280 ;
    END
  END Tile_X0Y1_S4BEG[8]
  PIN Tile_X0Y1_S4BEG[9]
    DIRECTION OUTPUT ;
    USE SIGNAL ;
    ANTENNADIFFAREA 0.445500 ;
    PORT
      LAYER met2 ;
        RECT 77.370 0.000 77.650 0.280 ;
    END
  END Tile_X0Y1_S4BEG[9]
  PIN Tile_X0Y1_UserCLK
    DIRECTION INPUT ;
    USE SIGNAL ;
    ANTENNAGATEAREA 0.852000 ;
    PORT
      LAYER met2 ;
        RECT 83.810 0.000 84.090 0.280 ;
    END
  END Tile_X0Y1_UserCLK
  PIN Tile_X0Y1_W1BEG[0]
    DIRECTION OUTPUT ;
    USE SIGNAL ;
    ANTENNADIFFAREA 0.445500 ;
    PORT
      LAYER met3 ;
        RECT 0.000 42.200 0.600 42.800 ;
    END
  END Tile_X0Y1_W1BEG[0]
  PIN Tile_X0Y1_W1BEG[1]
    DIRECTION OUTPUT ;
    USE SIGNAL ;
    ANTENNADIFFAREA 0.445500 ;
    PORT
      LAYER met3 ;
        RECT 0.000 43.560 0.600 44.160 ;
    END
  END Tile_X0Y1_W1BEG[1]
  PIN Tile_X0Y1_W1BEG[2]
    DIRECTION OUTPUT ;
    USE SIGNAL ;
    ANTENNADIFFAREA 0.445500 ;
    PORT
      LAYER met3 ;
        RECT 0.000 44.920 0.600 45.520 ;
    END
  END Tile_X0Y1_W1BEG[2]
  PIN Tile_X0Y1_W1BEG[3]
    DIRECTION OUTPUT ;
    USE SIGNAL ;
    ANTENNADIFFAREA 0.445500 ;
    PORT
      LAYER met3 ;
        RECT 0.000 46.280 0.600 46.880 ;
    END
  END Tile_X0Y1_W1BEG[3]
  PIN Tile_X0Y1_W2BEG[0]
    DIRECTION OUTPUT ;
    USE SIGNAL ;
    ANTENNADIFFAREA 0.445500 ;
    PORT
      LAYER met3 ;
        RECT 0.000 47.640 0.600 48.240 ;
    END
  END Tile_X0Y1_W2BEG[0]
  PIN Tile_X0Y1_W2BEG[1]
    DIRECTION OUTPUT ;
    USE SIGNAL ;
    ANTENNADIFFAREA 0.445500 ;
    PORT
      LAYER met3 ;
        RECT 0.000 49.000 0.600 49.600 ;
    END
  END Tile_X0Y1_W2BEG[1]
  PIN Tile_X0Y1_W2BEG[2]
    DIRECTION OUTPUT ;
    USE SIGNAL ;
    ANTENNADIFFAREA 0.445500 ;
    PORT
      LAYER met3 ;
        RECT 0.000 50.360 0.600 50.960 ;
    END
  END Tile_X0Y1_W2BEG[2]
  PIN Tile_X0Y1_W2BEG[3]
    DIRECTION OUTPUT ;
    USE SIGNAL ;
    ANTENNADIFFAREA 0.445500 ;
    PORT
      LAYER met3 ;
        RECT 0.000 51.720 0.600 52.320 ;
    END
  END Tile_X0Y1_W2BEG[3]
  PIN Tile_X0Y1_W2BEG[4]
    DIRECTION OUTPUT ;
    USE SIGNAL ;
    ANTENNADIFFAREA 0.445500 ;
    PORT
      LAYER met3 ;
        RECT 0.000 53.080 0.600 53.680 ;
    END
  END Tile_X0Y1_W2BEG[4]
  PIN Tile_X0Y1_W2BEG[5]
    DIRECTION OUTPUT ;
    USE SIGNAL ;
    ANTENNADIFFAREA 0.445500 ;
    PORT
      LAYER met3 ;
        RECT 0.000 54.440 0.600 55.040 ;
    END
  END Tile_X0Y1_W2BEG[5]
  PIN Tile_X0Y1_W2BEG[6]
    DIRECTION OUTPUT ;
    USE SIGNAL ;
    ANTENNADIFFAREA 0.445500 ;
    PORT
      LAYER met3 ;
        RECT 0.000 55.800 0.600 56.400 ;
    END
  END Tile_X0Y1_W2BEG[6]
  PIN Tile_X0Y1_W2BEG[7]
    DIRECTION OUTPUT ;
    USE SIGNAL ;
    ANTENNADIFFAREA 0.445500 ;
    PORT
      LAYER met3 ;
        RECT 0.000 57.160 0.600 57.760 ;
    END
  END Tile_X0Y1_W2BEG[7]
  PIN Tile_X0Y1_W2BEGb[0]
    DIRECTION OUTPUT ;
    USE SIGNAL ;
    ANTENNADIFFAREA 0.445500 ;
    PORT
      LAYER met3 ;
        RECT 0.000 58.520 0.600 59.120 ;
    END
  END Tile_X0Y1_W2BEGb[0]
  PIN Tile_X0Y1_W2BEGb[1]
    DIRECTION OUTPUT ;
    USE SIGNAL ;
    ANTENNADIFFAREA 0.445500 ;
    PORT
      LAYER met3 ;
        RECT 0.000 59.880 0.600 60.480 ;
    END
  END Tile_X0Y1_W2BEGb[1]
  PIN Tile_X0Y1_W2BEGb[2]
    DIRECTION OUTPUT ;
    USE SIGNAL ;
    ANTENNADIFFAREA 0.445500 ;
    PORT
      LAYER met3 ;
        RECT 0.000 61.240 0.600 61.840 ;
    END
  END Tile_X0Y1_W2BEGb[2]
  PIN Tile_X0Y1_W2BEGb[3]
    DIRECTION OUTPUT ;
    USE SIGNAL ;
    ANTENNADIFFAREA 0.445500 ;
    PORT
      LAYER met3 ;
        RECT 0.000 62.600 0.600 63.200 ;
    END
  END Tile_X0Y1_W2BEGb[3]
  PIN Tile_X0Y1_W2BEGb[4]
    DIRECTION OUTPUT ;
    USE SIGNAL ;
    ANTENNADIFFAREA 0.445500 ;
    PORT
      LAYER met3 ;
        RECT 0.000 63.960 0.600 64.560 ;
    END
  END Tile_X0Y1_W2BEGb[4]
  PIN Tile_X0Y1_W2BEGb[5]
    DIRECTION OUTPUT ;
    USE SIGNAL ;
    ANTENNADIFFAREA 0.445500 ;
    PORT
      LAYER met3 ;
        RECT 0.000 65.320 0.600 65.920 ;
    END
  END Tile_X0Y1_W2BEGb[5]
  PIN Tile_X0Y1_W2BEGb[6]
    DIRECTION OUTPUT ;
    USE SIGNAL ;
    ANTENNADIFFAREA 0.445500 ;
    PORT
      LAYER met3 ;
        RECT 0.000 66.680 0.600 67.280 ;
    END
  END Tile_X0Y1_W2BEGb[6]
  PIN Tile_X0Y1_W2BEGb[7]
    DIRECTION OUTPUT ;
    USE SIGNAL ;
    ANTENNADIFFAREA 0.445500 ;
    PORT
      LAYER met3 ;
        RECT 0.000 68.040 0.600 68.640 ;
    END
  END Tile_X0Y1_W2BEGb[7]
  PIN Tile_X0Y1_W6BEG[0]
    DIRECTION OUTPUT ;
    USE SIGNAL ;
    ANTENNADIFFAREA 0.445500 ;
    PORT
      LAYER met3 ;
        RECT 0.000 91.160 0.600 91.760 ;
    END
  END Tile_X0Y1_W6BEG[0]
  PIN Tile_X0Y1_W6BEG[10]
    DIRECTION OUTPUT ;
    USE SIGNAL ;
    ANTENNADIFFAREA 0.445500 ;
    PORT
      LAYER met3 ;
        RECT 0.000 104.760 0.600 105.360 ;
    END
  END Tile_X0Y1_W6BEG[10]
  PIN Tile_X0Y1_W6BEG[11]
    DIRECTION OUTPUT ;
    USE SIGNAL ;
    ANTENNADIFFAREA 0.445500 ;
    PORT
      LAYER met3 ;
        RECT 0.000 106.120 0.600 106.720 ;
    END
  END Tile_X0Y1_W6BEG[11]
  PIN Tile_X0Y1_W6BEG[1]
    DIRECTION OUTPUT ;
    USE SIGNAL ;
    ANTENNADIFFAREA 0.445500 ;
    PORT
      LAYER met3 ;
        RECT 0.000 92.520 0.600 93.120 ;
    END
  END Tile_X0Y1_W6BEG[1]
  PIN Tile_X0Y1_W6BEG[2]
    DIRECTION OUTPUT ;
    USE SIGNAL ;
    ANTENNADIFFAREA 0.445500 ;
    PORT
      LAYER met3 ;
        RECT 0.000 93.880 0.600 94.480 ;
    END
  END Tile_X0Y1_W6BEG[2]
  PIN Tile_X0Y1_W6BEG[3]
    DIRECTION OUTPUT ;
    USE SIGNAL ;
    ANTENNADIFFAREA 0.445500 ;
    PORT
      LAYER met3 ;
        RECT 0.000 95.240 0.600 95.840 ;
    END
  END Tile_X0Y1_W6BEG[3]
  PIN Tile_X0Y1_W6BEG[4]
    DIRECTION OUTPUT ;
    USE SIGNAL ;
    ANTENNADIFFAREA 0.445500 ;
    PORT
      LAYER met3 ;
        RECT 0.000 96.600 0.600 97.200 ;
    END
  END Tile_X0Y1_W6BEG[4]
  PIN Tile_X0Y1_W6BEG[5]
    DIRECTION OUTPUT ;
    USE SIGNAL ;
    ANTENNADIFFAREA 0.445500 ;
    PORT
      LAYER met3 ;
        RECT 0.000 97.960 0.600 98.560 ;
    END
  END Tile_X0Y1_W6BEG[5]
  PIN Tile_X0Y1_W6BEG[6]
    DIRECTION OUTPUT ;
    USE SIGNAL ;
    ANTENNADIFFAREA 0.445500 ;
    PORT
      LAYER met3 ;
        RECT 0.000 99.320 0.600 99.920 ;
    END
  END Tile_X0Y1_W6BEG[6]
  PIN Tile_X0Y1_W6BEG[7]
    DIRECTION OUTPUT ;
    USE SIGNAL ;
    ANTENNADIFFAREA 0.445500 ;
    PORT
      LAYER met3 ;
        RECT 0.000 100.680 0.600 101.280 ;
    END
  END Tile_X0Y1_W6BEG[7]
  PIN Tile_X0Y1_W6BEG[8]
    DIRECTION OUTPUT ;
    USE SIGNAL ;
    ANTENNADIFFAREA 0.445500 ;
    PORT
      LAYER met3 ;
        RECT 0.000 102.040 0.600 102.640 ;
    END
  END Tile_X0Y1_W6BEG[8]
  PIN Tile_X0Y1_W6BEG[9]
    DIRECTION OUTPUT ;
    USE SIGNAL ;
    ANTENNADIFFAREA 0.445500 ;
    PORT
      LAYER met3 ;
        RECT 0.000 103.400 0.600 104.000 ;
    END
  END Tile_X0Y1_W6BEG[9]
  PIN Tile_X0Y1_WW4BEG[0]
    DIRECTION OUTPUT ;
    USE SIGNAL ;
    ANTENNADIFFAREA 0.445500 ;
    PORT
      LAYER met3 ;
        RECT 0.000 69.400 0.600 70.000 ;
    END
  END Tile_X0Y1_WW4BEG[0]
  PIN Tile_X0Y1_WW4BEG[10]
    DIRECTION OUTPUT ;
    USE SIGNAL ;
    ANTENNADIFFAREA 0.445500 ;
    PORT
      LAYER met3 ;
        RECT 0.000 83.000 0.600 83.600 ;
    END
  END Tile_X0Y1_WW4BEG[10]
  PIN Tile_X0Y1_WW4BEG[11]
    DIRECTION OUTPUT ;
    USE SIGNAL ;
    ANTENNADIFFAREA 0.445500 ;
    PORT
      LAYER met3 ;
        RECT 0.000 84.360 0.600 84.960 ;
    END
  END Tile_X0Y1_WW4BEG[11]
  PIN Tile_X0Y1_WW4BEG[12]
    DIRECTION OUTPUT ;
    USE SIGNAL ;
    ANTENNADIFFAREA 0.445500 ;
    PORT
      LAYER met3 ;
        RECT 0.000 85.720 0.600 86.320 ;
    END
  END Tile_X0Y1_WW4BEG[12]
  PIN Tile_X0Y1_WW4BEG[13]
    DIRECTION OUTPUT ;
    USE SIGNAL ;
    ANTENNADIFFAREA 0.445500 ;
    PORT
      LAYER met3 ;
        RECT 0.000 87.080 0.600 87.680 ;
    END
  END Tile_X0Y1_WW4BEG[13]
  PIN Tile_X0Y1_WW4BEG[14]
    DIRECTION OUTPUT ;
    USE SIGNAL ;
    ANTENNADIFFAREA 0.445500 ;
    PORT
      LAYER met3 ;
        RECT 0.000 88.440 0.600 89.040 ;
    END
  END Tile_X0Y1_WW4BEG[14]
  PIN Tile_X0Y1_WW4BEG[15]
    DIRECTION OUTPUT ;
    USE SIGNAL ;
    ANTENNADIFFAREA 0.445500 ;
    PORT
      LAYER met3 ;
        RECT 0.000 89.800 0.600 90.400 ;
    END
  END Tile_X0Y1_WW4BEG[15]
  PIN Tile_X0Y1_WW4BEG[1]
    DIRECTION OUTPUT ;
    USE SIGNAL ;
    ANTENNADIFFAREA 0.445500 ;
    PORT
      LAYER met3 ;
        RECT 0.000 70.760 0.600 71.360 ;
    END
  END Tile_X0Y1_WW4BEG[1]
  PIN Tile_X0Y1_WW4BEG[2]
    DIRECTION OUTPUT ;
    USE SIGNAL ;
    ANTENNADIFFAREA 0.445500 ;
    PORT
      LAYER met3 ;
        RECT 0.000 72.120 0.600 72.720 ;
    END
  END Tile_X0Y1_WW4BEG[2]
  PIN Tile_X0Y1_WW4BEG[3]
    DIRECTION OUTPUT ;
    USE SIGNAL ;
    ANTENNADIFFAREA 0.445500 ;
    PORT
      LAYER met3 ;
        RECT 0.000 73.480 0.600 74.080 ;
    END
  END Tile_X0Y1_WW4BEG[3]
  PIN Tile_X0Y1_WW4BEG[4]
    DIRECTION OUTPUT ;
    USE SIGNAL ;
    ANTENNADIFFAREA 0.445500 ;
    PORT
      LAYER met3 ;
        RECT 0.000 74.840 0.600 75.440 ;
    END
  END Tile_X0Y1_WW4BEG[4]
  PIN Tile_X0Y1_WW4BEG[5]
    DIRECTION OUTPUT ;
    USE SIGNAL ;
    ANTENNADIFFAREA 0.445500 ;
    PORT
      LAYER met3 ;
        RECT 0.000 76.200 0.600 76.800 ;
    END
  END Tile_X0Y1_WW4BEG[5]
  PIN Tile_X0Y1_WW4BEG[6]
    DIRECTION OUTPUT ;
    USE SIGNAL ;
    ANTENNADIFFAREA 0.445500 ;
    PORT
      LAYER met3 ;
        RECT 0.000 77.560 0.600 78.160 ;
    END
  END Tile_X0Y1_WW4BEG[6]
  PIN Tile_X0Y1_WW4BEG[7]
    DIRECTION OUTPUT ;
    USE SIGNAL ;
    ANTENNADIFFAREA 0.445500 ;
    PORT
      LAYER met3 ;
        RECT 0.000 78.920 0.600 79.520 ;
    END
  END Tile_X0Y1_WW4BEG[7]
  PIN Tile_X0Y1_WW4BEG[8]
    DIRECTION OUTPUT ;
    USE SIGNAL ;
    ANTENNADIFFAREA 0.445500 ;
    PORT
      LAYER met3 ;
        RECT 0.000 80.280 0.600 80.880 ;
    END
  END Tile_X0Y1_WW4BEG[8]
  PIN Tile_X0Y1_WW4BEG[9]
    DIRECTION OUTPUT ;
    USE SIGNAL ;
    ANTENNADIFFAREA 0.445500 ;
    PORT
      LAYER met3 ;
        RECT 0.000 81.640 0.600 82.240 ;
    END
  END Tile_X0Y1_WW4BEG[9]
  PIN VGND
    DIRECTION INOUT ;
    USE GROUND ;
    PORT
      LAYER met4 ;
        RECT 15.020 0.000 16.620 519.520 ;
    END
    PORT
      LAYER met4 ;
        RECT 45.020 0.000 46.620 519.520 ;
    END
    PORT
      LAYER met4 ;
        RECT 75.020 0.000 76.620 519.520 ;
    END
    PORT
      LAYER met4 ;
        RECT 105.020 0.000 106.620 519.520 ;
    END
  END VGND
  PIN VPWR
    DIRECTION INOUT ;
    USE POWER ;
    PORT
      LAYER met4 ;
        RECT 9.720 0.000 11.320 519.520 ;
    END
    PORT
      LAYER met4 ;
        RECT 39.720 0.000 41.320 519.520 ;
    END
    PORT
      LAYER met4 ;
        RECT 69.720 0.000 71.320 519.520 ;
    END
    PORT
      LAYER met4 ;
        RECT 99.720 0.000 101.320 519.520 ;
    END
  END VPWR
  PIN WEB_A_SRAM
    DIRECTION OUTPUT ;
    USE SIGNAL ;
    ANTENNADIFFAREA 0.445500 ;
    PORT
      LAYER met3 ;
        RECT 119.460 189.080 120.060 189.680 ;
    END
  END WEB_A_SRAM
  PIN WMASK_A_SRAM0
    DIRECTION OUTPUT ;
    USE SIGNAL ;
    ANTENNADIFFAREA 0.445500 ;
    PORT
      LAYER met3 ;
        RECT 119.460 191.800 120.060 192.400 ;
    END
  END WMASK_A_SRAM0
  PIN WMASK_A_SRAM1
    DIRECTION OUTPUT ;
    USE SIGNAL ;
    ANTENNADIFFAREA 0.445500 ;
    PORT
      LAYER met3 ;
        RECT 119.460 194.520 120.060 195.120 ;
    END
  END WMASK_A_SRAM1
  PIN WMASK_A_SRAM2
    DIRECTION OUTPUT ;
    USE SIGNAL ;
    ANTENNADIFFAREA 0.445500 ;
    PORT
      LAYER met3 ;
        RECT 119.460 197.240 120.060 197.840 ;
    END
  END WMASK_A_SRAM2
  PIN WMASK_A_SRAM3
    DIRECTION OUTPUT ;
    USE SIGNAL ;
    ANTENNADIFFAREA 0.445500 ;
    PORT
      LAYER met3 ;
        RECT 119.460 199.960 120.060 200.560 ;
    END
  END WMASK_A_SRAM3
  OBS
      LAYER nwell ;
        RECT 5.330 10.795 114.730 508.830 ;
      LAYER li1 ;
        RECT 5.520 10.795 114.540 508.725 ;
      LAYER met1 ;
        RECT 0.070 0.040 119.990 516.760 ;
      LAYER met2 ;
        RECT 0.100 518.960 17.290 519.450 ;
        RECT 18.130 518.960 18.210 519.450 ;
        RECT 19.050 518.960 19.130 519.450 ;
        RECT 19.970 518.960 20.050 519.450 ;
        RECT 20.890 518.960 20.970 519.450 ;
        RECT 21.810 518.960 21.890 519.450 ;
        RECT 22.730 518.960 22.810 519.450 ;
        RECT 23.650 518.960 23.730 519.450 ;
        RECT 24.570 518.960 24.650 519.450 ;
        RECT 25.490 518.960 25.570 519.450 ;
        RECT 26.410 518.960 26.490 519.450 ;
        RECT 27.330 518.960 27.410 519.450 ;
        RECT 28.250 518.960 28.330 519.450 ;
        RECT 29.170 518.960 29.250 519.450 ;
        RECT 30.090 518.960 30.170 519.450 ;
        RECT 31.010 518.960 31.090 519.450 ;
        RECT 31.930 518.960 32.010 519.450 ;
        RECT 32.850 518.960 32.930 519.450 ;
        RECT 33.770 518.960 33.850 519.450 ;
        RECT 34.690 518.960 34.770 519.450 ;
        RECT 35.610 518.960 35.690 519.450 ;
        RECT 36.530 518.960 36.610 519.450 ;
        RECT 37.450 518.960 37.530 519.450 ;
        RECT 38.370 518.960 38.450 519.450 ;
        RECT 39.290 518.960 39.370 519.450 ;
        RECT 40.210 518.960 40.290 519.450 ;
        RECT 41.130 518.960 41.210 519.450 ;
        RECT 42.050 518.960 42.130 519.450 ;
        RECT 42.970 518.960 43.050 519.450 ;
        RECT 43.890 518.960 43.970 519.450 ;
        RECT 44.810 518.960 44.890 519.450 ;
        RECT 45.730 518.960 45.810 519.450 ;
        RECT 46.650 518.960 46.730 519.450 ;
        RECT 47.570 518.960 47.650 519.450 ;
        RECT 48.490 518.960 48.570 519.450 ;
        RECT 49.410 518.960 49.490 519.450 ;
        RECT 50.330 518.960 50.410 519.450 ;
        RECT 51.250 518.960 51.330 519.450 ;
        RECT 52.170 518.960 52.250 519.450 ;
        RECT 53.090 518.960 53.170 519.450 ;
        RECT 54.010 518.960 54.090 519.450 ;
        RECT 54.930 518.960 55.010 519.450 ;
        RECT 55.850 518.960 55.930 519.450 ;
        RECT 56.770 518.960 56.850 519.450 ;
        RECT 57.690 518.960 57.770 519.450 ;
        RECT 58.610 518.960 58.690 519.450 ;
        RECT 59.530 518.960 59.610 519.450 ;
        RECT 60.450 518.960 60.530 519.450 ;
        RECT 61.370 518.960 61.450 519.450 ;
        RECT 62.290 518.960 62.370 519.450 ;
        RECT 63.210 518.960 63.290 519.450 ;
        RECT 64.130 518.960 64.210 519.450 ;
        RECT 65.050 518.960 65.130 519.450 ;
        RECT 65.970 518.960 66.050 519.450 ;
        RECT 66.890 518.960 66.970 519.450 ;
        RECT 67.810 518.960 67.890 519.450 ;
        RECT 68.730 518.960 68.810 519.450 ;
        RECT 69.650 518.960 69.730 519.450 ;
        RECT 70.570 518.960 70.650 519.450 ;
        RECT 71.490 518.960 71.570 519.450 ;
        RECT 72.410 518.960 72.490 519.450 ;
        RECT 73.330 518.960 73.410 519.450 ;
        RECT 74.250 518.960 74.330 519.450 ;
        RECT 75.170 518.960 75.250 519.450 ;
        RECT 76.090 518.960 76.170 519.450 ;
        RECT 77.010 518.960 77.090 519.450 ;
        RECT 77.930 518.960 78.010 519.450 ;
        RECT 78.850 518.960 78.930 519.450 ;
        RECT 79.770 518.960 79.850 519.450 ;
        RECT 80.690 518.960 80.770 519.450 ;
        RECT 81.610 518.960 81.690 519.450 ;
        RECT 82.530 518.960 82.610 519.450 ;
        RECT 83.450 518.960 83.530 519.450 ;
        RECT 84.370 518.960 84.450 519.450 ;
        RECT 85.290 518.960 85.370 519.450 ;
        RECT 86.210 518.960 86.290 519.450 ;
        RECT 87.130 518.960 87.210 519.450 ;
        RECT 88.050 518.960 88.130 519.450 ;
        RECT 88.970 518.960 89.050 519.450 ;
        RECT 89.890 518.960 89.970 519.450 ;
        RECT 90.810 518.960 90.890 519.450 ;
        RECT 91.730 518.960 91.810 519.450 ;
        RECT 92.650 518.960 92.730 519.450 ;
        RECT 93.570 518.960 93.650 519.450 ;
        RECT 94.490 518.960 94.570 519.450 ;
        RECT 95.410 518.960 95.490 519.450 ;
        RECT 96.330 518.960 96.410 519.450 ;
        RECT 97.250 518.960 97.330 519.450 ;
        RECT 98.170 518.960 98.250 519.450 ;
        RECT 99.090 518.960 99.170 519.450 ;
        RECT 100.010 518.960 100.090 519.450 ;
        RECT 100.930 518.960 101.010 519.450 ;
        RECT 101.850 518.960 101.930 519.450 ;
        RECT 102.770 518.960 119.970 519.450 ;
        RECT 0.100 0.560 119.970 518.960 ;
        RECT 0.100 0.010 17.290 0.560 ;
        RECT 18.130 0.010 18.210 0.560 ;
        RECT 19.050 0.010 19.130 0.560 ;
        RECT 19.970 0.010 20.050 0.560 ;
        RECT 20.890 0.010 20.970 0.560 ;
        RECT 21.810 0.010 21.890 0.560 ;
        RECT 22.730 0.010 22.810 0.560 ;
        RECT 23.650 0.010 23.730 0.560 ;
        RECT 24.570 0.010 24.650 0.560 ;
        RECT 25.490 0.010 25.570 0.560 ;
        RECT 26.410 0.010 26.490 0.560 ;
        RECT 27.330 0.010 27.410 0.560 ;
        RECT 28.250 0.010 28.330 0.560 ;
        RECT 29.170 0.010 29.250 0.560 ;
        RECT 30.090 0.010 30.170 0.560 ;
        RECT 31.010 0.010 31.090 0.560 ;
        RECT 31.930 0.010 32.010 0.560 ;
        RECT 32.850 0.010 32.930 0.560 ;
        RECT 33.770 0.010 33.850 0.560 ;
        RECT 34.690 0.010 34.770 0.560 ;
        RECT 35.610 0.010 35.690 0.560 ;
        RECT 36.530 0.010 36.610 0.560 ;
        RECT 37.450 0.010 37.530 0.560 ;
        RECT 38.370 0.010 38.450 0.560 ;
        RECT 39.290 0.010 39.370 0.560 ;
        RECT 40.210 0.010 40.290 0.560 ;
        RECT 41.130 0.010 41.210 0.560 ;
        RECT 42.050 0.010 42.130 0.560 ;
        RECT 42.970 0.010 43.050 0.560 ;
        RECT 43.890 0.010 43.970 0.560 ;
        RECT 44.810 0.010 44.890 0.560 ;
        RECT 45.730 0.010 45.810 0.560 ;
        RECT 46.650 0.010 46.730 0.560 ;
        RECT 47.570 0.010 47.650 0.560 ;
        RECT 48.490 0.010 48.570 0.560 ;
        RECT 49.410 0.010 49.490 0.560 ;
        RECT 50.330 0.010 50.410 0.560 ;
        RECT 51.250 0.010 51.330 0.560 ;
        RECT 52.170 0.010 52.250 0.560 ;
        RECT 53.090 0.010 53.170 0.560 ;
        RECT 54.010 0.010 54.090 0.560 ;
        RECT 54.930 0.010 55.010 0.560 ;
        RECT 55.850 0.010 55.930 0.560 ;
        RECT 56.770 0.010 56.850 0.560 ;
        RECT 57.690 0.010 57.770 0.560 ;
        RECT 58.610 0.010 58.690 0.560 ;
        RECT 59.530 0.010 59.610 0.560 ;
        RECT 60.450 0.010 60.530 0.560 ;
        RECT 61.370 0.010 61.450 0.560 ;
        RECT 62.290 0.010 62.370 0.560 ;
        RECT 63.210 0.010 63.290 0.560 ;
        RECT 64.130 0.010 64.210 0.560 ;
        RECT 65.050 0.010 65.130 0.560 ;
        RECT 65.970 0.010 66.050 0.560 ;
        RECT 66.890 0.010 66.970 0.560 ;
        RECT 67.810 0.010 67.890 0.560 ;
        RECT 68.730 0.010 68.810 0.560 ;
        RECT 69.650 0.010 69.730 0.560 ;
        RECT 70.570 0.010 70.650 0.560 ;
        RECT 71.490 0.010 71.570 0.560 ;
        RECT 72.410 0.010 72.490 0.560 ;
        RECT 73.330 0.010 73.410 0.560 ;
        RECT 74.250 0.010 74.330 0.560 ;
        RECT 75.170 0.010 75.250 0.560 ;
        RECT 76.090 0.010 76.170 0.560 ;
        RECT 77.010 0.010 77.090 0.560 ;
        RECT 77.930 0.010 78.010 0.560 ;
        RECT 78.850 0.010 78.930 0.560 ;
        RECT 79.770 0.010 79.850 0.560 ;
        RECT 80.690 0.010 80.770 0.560 ;
        RECT 81.610 0.010 81.690 0.560 ;
        RECT 82.530 0.010 82.610 0.560 ;
        RECT 83.450 0.010 83.530 0.560 ;
        RECT 84.370 0.010 84.450 0.560 ;
        RECT 85.290 0.010 85.370 0.560 ;
        RECT 86.210 0.010 86.290 0.560 ;
        RECT 87.130 0.010 87.210 0.560 ;
        RECT 88.050 0.010 88.130 0.560 ;
        RECT 88.970 0.010 89.050 0.560 ;
        RECT 89.890 0.010 89.970 0.560 ;
        RECT 90.810 0.010 90.890 0.560 ;
        RECT 91.730 0.010 91.810 0.560 ;
        RECT 92.650 0.010 92.730 0.560 ;
        RECT 93.570 0.010 93.650 0.560 ;
        RECT 94.490 0.010 94.570 0.560 ;
        RECT 95.410 0.010 95.490 0.560 ;
        RECT 96.330 0.010 96.410 0.560 ;
        RECT 97.250 0.010 97.330 0.560 ;
        RECT 98.170 0.010 98.250 0.560 ;
        RECT 99.090 0.010 99.170 0.560 ;
        RECT 100.010 0.010 100.090 0.560 ;
        RECT 100.930 0.010 101.010 0.560 ;
        RECT 101.850 0.010 101.930 0.560 ;
        RECT 102.770 0.010 119.970 0.560 ;
      LAYER met3 ;
        RECT 0.600 509.640 119.060 510.505 ;
        RECT 0.600 508.320 119.995 509.640 ;
        RECT 0.600 506.920 119.060 508.320 ;
        RECT 0.600 505.600 119.995 506.920 ;
        RECT 0.600 504.200 119.060 505.600 ;
        RECT 0.600 502.880 119.995 504.200 ;
        RECT 0.600 501.480 119.060 502.880 ;
        RECT 0.600 500.160 119.995 501.480 ;
        RECT 0.600 498.760 119.060 500.160 ;
        RECT 0.600 497.440 119.995 498.760 ;
        RECT 0.600 496.040 119.060 497.440 ;
        RECT 0.600 494.720 119.995 496.040 ;
        RECT 0.600 493.320 119.060 494.720 ;
        RECT 0.600 492.000 119.995 493.320 ;
        RECT 0.600 490.600 119.060 492.000 ;
        RECT 0.600 489.280 119.995 490.600 ;
        RECT 0.600 487.880 119.060 489.280 ;
        RECT 0.600 486.560 119.995 487.880 ;
        RECT 0.600 485.160 119.060 486.560 ;
        RECT 0.600 483.840 119.995 485.160 ;
        RECT 0.600 482.440 119.060 483.840 ;
        RECT 0.600 481.120 119.995 482.440 ;
        RECT 0.600 479.720 119.060 481.120 ;
        RECT 0.600 478.400 119.995 479.720 ;
        RECT 0.600 477.000 119.060 478.400 ;
        RECT 0.600 475.680 119.995 477.000 ;
        RECT 1.000 474.280 119.060 475.680 ;
        RECT 1.000 472.960 119.995 474.280 ;
        RECT 1.000 471.560 119.060 472.960 ;
        RECT 1.000 470.240 119.995 471.560 ;
        RECT 1.000 468.840 119.060 470.240 ;
        RECT 1.000 467.520 119.995 468.840 ;
        RECT 1.000 466.120 119.060 467.520 ;
        RECT 1.000 464.800 119.995 466.120 ;
        RECT 1.000 463.400 119.060 464.800 ;
        RECT 1.000 462.080 119.995 463.400 ;
        RECT 1.000 460.680 119.060 462.080 ;
        RECT 1.000 459.360 119.995 460.680 ;
        RECT 1.000 457.960 119.060 459.360 ;
        RECT 1.000 456.640 119.995 457.960 ;
        RECT 1.000 455.240 119.060 456.640 ;
        RECT 1.000 453.920 119.995 455.240 ;
        RECT 1.000 452.520 119.060 453.920 ;
        RECT 1.000 451.200 119.995 452.520 ;
        RECT 1.000 449.800 119.060 451.200 ;
        RECT 1.000 448.480 119.995 449.800 ;
        RECT 1.000 447.080 119.060 448.480 ;
        RECT 1.000 445.760 119.995 447.080 ;
        RECT 1.000 444.360 119.060 445.760 ;
        RECT 1.000 443.040 119.995 444.360 ;
        RECT 1.000 441.640 119.060 443.040 ;
        RECT 1.000 440.320 119.995 441.640 ;
        RECT 1.000 438.920 119.060 440.320 ;
        RECT 1.000 437.600 119.995 438.920 ;
        RECT 1.000 436.200 119.060 437.600 ;
        RECT 1.000 434.880 119.995 436.200 ;
        RECT 1.000 433.480 119.060 434.880 ;
        RECT 1.000 432.160 119.995 433.480 ;
        RECT 1.000 430.760 119.060 432.160 ;
        RECT 1.000 429.440 119.995 430.760 ;
        RECT 1.000 428.040 119.060 429.440 ;
        RECT 1.000 426.720 119.995 428.040 ;
        RECT 1.000 425.320 119.060 426.720 ;
        RECT 1.000 424.000 119.995 425.320 ;
        RECT 1.000 422.600 119.060 424.000 ;
        RECT 1.000 421.280 119.995 422.600 ;
        RECT 1.000 419.880 119.060 421.280 ;
        RECT 1.000 418.560 119.995 419.880 ;
        RECT 1.000 417.160 119.060 418.560 ;
        RECT 1.000 415.840 119.995 417.160 ;
        RECT 1.000 414.440 119.060 415.840 ;
        RECT 1.000 413.120 119.995 414.440 ;
        RECT 1.000 411.720 119.060 413.120 ;
        RECT 1.000 410.400 119.995 411.720 ;
        RECT 1.000 409.000 119.060 410.400 ;
        RECT 1.000 407.680 119.995 409.000 ;
        RECT 1.000 406.280 119.060 407.680 ;
        RECT 1.000 404.960 119.995 406.280 ;
        RECT 1.000 403.560 119.060 404.960 ;
        RECT 1.000 402.240 119.995 403.560 ;
        RECT 1.000 400.840 119.060 402.240 ;
        RECT 1.000 399.520 119.995 400.840 ;
        RECT 1.000 398.120 119.060 399.520 ;
        RECT 1.000 396.800 119.995 398.120 ;
        RECT 1.000 395.400 119.060 396.800 ;
        RECT 1.000 394.080 119.995 395.400 ;
        RECT 1.000 392.680 119.060 394.080 ;
        RECT 1.000 391.360 119.995 392.680 ;
        RECT 1.000 389.960 119.060 391.360 ;
        RECT 1.000 388.640 119.995 389.960 ;
        RECT 1.000 387.240 119.060 388.640 ;
        RECT 1.000 385.920 119.995 387.240 ;
        RECT 1.000 384.520 119.060 385.920 ;
        RECT 1.000 383.200 119.995 384.520 ;
        RECT 1.000 381.800 119.060 383.200 ;
        RECT 1.000 380.480 119.995 381.800 ;
        RECT 1.000 379.080 119.060 380.480 ;
        RECT 1.000 377.760 119.995 379.080 ;
        RECT 1.000 376.360 119.060 377.760 ;
        RECT 1.000 375.040 119.995 376.360 ;
        RECT 1.000 373.640 119.060 375.040 ;
        RECT 1.000 372.320 119.995 373.640 ;
        RECT 1.000 370.920 119.060 372.320 ;
        RECT 1.000 369.600 119.995 370.920 ;
        RECT 1.000 368.200 119.060 369.600 ;
        RECT 1.000 366.880 119.995 368.200 ;
        RECT 1.000 365.480 119.060 366.880 ;
        RECT 1.000 364.160 119.995 365.480 ;
        RECT 1.000 362.760 119.060 364.160 ;
        RECT 1.000 361.440 119.995 362.760 ;
        RECT 1.000 360.040 119.060 361.440 ;
        RECT 1.000 358.720 119.995 360.040 ;
        RECT 1.000 357.320 119.060 358.720 ;
        RECT 1.000 356.000 119.995 357.320 ;
        RECT 1.000 354.600 119.060 356.000 ;
        RECT 1.000 353.280 119.995 354.600 ;
        RECT 1.000 351.880 119.060 353.280 ;
        RECT 1.000 350.560 119.995 351.880 ;
        RECT 1.000 349.160 119.060 350.560 ;
        RECT 1.000 347.840 119.995 349.160 ;
        RECT 1.000 346.440 119.060 347.840 ;
        RECT 1.000 345.120 119.995 346.440 ;
        RECT 1.000 343.720 119.060 345.120 ;
        RECT 1.000 342.400 119.995 343.720 ;
        RECT 1.000 341.000 119.060 342.400 ;
        RECT 1.000 339.680 119.995 341.000 ;
        RECT 1.000 338.280 119.060 339.680 ;
        RECT 1.000 336.960 119.995 338.280 ;
        RECT 1.000 335.560 119.060 336.960 ;
        RECT 1.000 334.240 119.995 335.560 ;
        RECT 1.000 332.840 119.060 334.240 ;
        RECT 1.000 331.520 119.995 332.840 ;
        RECT 1.000 330.120 119.060 331.520 ;
        RECT 1.000 328.800 119.995 330.120 ;
        RECT 1.000 327.400 119.060 328.800 ;
        RECT 1.000 326.080 119.995 327.400 ;
        RECT 1.000 324.680 119.060 326.080 ;
        RECT 1.000 323.360 119.995 324.680 ;
        RECT 1.000 321.960 119.060 323.360 ;
        RECT 1.000 320.640 119.995 321.960 ;
        RECT 1.000 319.240 119.060 320.640 ;
        RECT 1.000 317.920 119.995 319.240 ;
        RECT 1.000 316.520 119.060 317.920 ;
        RECT 1.000 315.200 119.995 316.520 ;
        RECT 1.000 313.800 119.060 315.200 ;
        RECT 1.000 312.480 119.995 313.800 ;
        RECT 1.000 311.080 119.060 312.480 ;
        RECT 1.000 309.760 119.995 311.080 ;
        RECT 1.000 308.360 119.060 309.760 ;
        RECT 1.000 307.040 119.995 308.360 ;
        RECT 1.000 305.640 119.060 307.040 ;
        RECT 1.000 304.320 119.995 305.640 ;
        RECT 1.000 302.920 119.060 304.320 ;
        RECT 1.000 301.600 119.995 302.920 ;
        RECT 1.000 301.560 119.060 301.600 ;
        RECT 0.600 300.200 119.060 301.560 ;
        RECT 0.600 298.880 119.995 300.200 ;
        RECT 0.600 297.480 119.060 298.880 ;
        RECT 0.600 296.160 119.995 297.480 ;
        RECT 0.600 294.760 119.060 296.160 ;
        RECT 0.600 293.440 119.995 294.760 ;
        RECT 0.600 292.040 119.060 293.440 ;
        RECT 0.600 290.720 119.995 292.040 ;
        RECT 0.600 289.320 119.060 290.720 ;
        RECT 0.600 288.000 119.995 289.320 ;
        RECT 0.600 286.600 119.060 288.000 ;
        RECT 0.600 285.280 119.995 286.600 ;
        RECT 0.600 283.880 119.060 285.280 ;
        RECT 0.600 282.560 119.995 283.880 ;
        RECT 0.600 281.160 119.060 282.560 ;
        RECT 0.600 279.840 119.995 281.160 ;
        RECT 0.600 278.440 119.060 279.840 ;
        RECT 0.600 277.120 119.995 278.440 ;
        RECT 0.600 275.720 119.060 277.120 ;
        RECT 0.600 274.400 119.995 275.720 ;
        RECT 0.600 273.000 119.060 274.400 ;
        RECT 0.600 271.680 119.995 273.000 ;
        RECT 0.600 270.280 119.060 271.680 ;
        RECT 0.600 268.960 119.995 270.280 ;
        RECT 0.600 267.560 119.060 268.960 ;
        RECT 0.600 266.240 119.995 267.560 ;
        RECT 0.600 264.840 119.060 266.240 ;
        RECT 0.600 263.520 119.995 264.840 ;
        RECT 0.600 262.120 119.060 263.520 ;
        RECT 0.600 260.800 119.995 262.120 ;
        RECT 0.600 259.400 119.060 260.800 ;
        RECT 0.600 258.080 119.995 259.400 ;
        RECT 0.600 256.680 119.060 258.080 ;
        RECT 0.600 255.360 119.995 256.680 ;
        RECT 0.600 253.960 119.060 255.360 ;
        RECT 0.600 252.640 119.995 253.960 ;
        RECT 0.600 251.240 119.060 252.640 ;
        RECT 0.600 249.920 119.995 251.240 ;
        RECT 0.600 248.520 119.060 249.920 ;
        RECT 0.600 247.200 119.995 248.520 ;
        RECT 0.600 245.800 119.060 247.200 ;
        RECT 0.600 244.480 119.995 245.800 ;
        RECT 0.600 243.080 119.060 244.480 ;
        RECT 0.600 241.760 119.995 243.080 ;
        RECT 0.600 240.360 119.060 241.760 ;
        RECT 0.600 239.040 119.995 240.360 ;
        RECT 0.600 237.640 119.060 239.040 ;
        RECT 0.600 236.320 119.995 237.640 ;
        RECT 0.600 234.920 119.060 236.320 ;
        RECT 0.600 233.600 119.995 234.920 ;
        RECT 0.600 232.200 119.060 233.600 ;
        RECT 0.600 230.880 119.995 232.200 ;
        RECT 0.600 229.480 119.060 230.880 ;
        RECT 0.600 228.160 119.995 229.480 ;
        RECT 0.600 226.760 119.060 228.160 ;
        RECT 0.600 225.440 119.995 226.760 ;
        RECT 0.600 224.040 119.060 225.440 ;
        RECT 0.600 222.720 119.995 224.040 ;
        RECT 0.600 221.320 119.060 222.720 ;
        RECT 0.600 220.000 119.995 221.320 ;
        RECT 0.600 218.600 119.060 220.000 ;
        RECT 0.600 217.280 119.995 218.600 ;
        RECT 0.600 215.920 119.060 217.280 ;
        RECT 1.000 215.880 119.060 215.920 ;
        RECT 1.000 214.560 119.995 215.880 ;
        RECT 1.000 213.160 119.060 214.560 ;
        RECT 1.000 211.840 119.995 213.160 ;
        RECT 1.000 210.440 119.060 211.840 ;
        RECT 1.000 209.120 119.995 210.440 ;
        RECT 1.000 207.720 119.060 209.120 ;
        RECT 1.000 206.400 119.995 207.720 ;
        RECT 1.000 205.000 119.060 206.400 ;
        RECT 1.000 203.680 119.995 205.000 ;
        RECT 1.000 202.280 119.060 203.680 ;
        RECT 1.000 200.960 119.995 202.280 ;
        RECT 1.000 199.560 119.060 200.960 ;
        RECT 1.000 198.240 119.995 199.560 ;
        RECT 1.000 196.840 119.060 198.240 ;
        RECT 1.000 195.520 119.995 196.840 ;
        RECT 1.000 194.120 119.060 195.520 ;
        RECT 1.000 192.800 119.995 194.120 ;
        RECT 1.000 191.400 119.060 192.800 ;
        RECT 1.000 190.080 119.995 191.400 ;
        RECT 1.000 188.680 119.060 190.080 ;
        RECT 1.000 187.360 119.995 188.680 ;
        RECT 1.000 185.960 119.060 187.360 ;
        RECT 1.000 184.640 119.995 185.960 ;
        RECT 1.000 183.240 119.060 184.640 ;
        RECT 1.000 181.920 119.995 183.240 ;
        RECT 1.000 180.520 119.060 181.920 ;
        RECT 1.000 179.200 119.995 180.520 ;
        RECT 1.000 177.800 119.060 179.200 ;
        RECT 1.000 176.480 119.995 177.800 ;
        RECT 1.000 175.080 119.060 176.480 ;
        RECT 1.000 173.760 119.995 175.080 ;
        RECT 1.000 172.360 119.060 173.760 ;
        RECT 1.000 171.040 119.995 172.360 ;
        RECT 1.000 169.640 119.060 171.040 ;
        RECT 1.000 168.320 119.995 169.640 ;
        RECT 1.000 166.920 119.060 168.320 ;
        RECT 1.000 165.600 119.995 166.920 ;
        RECT 1.000 164.200 119.060 165.600 ;
        RECT 1.000 162.880 119.995 164.200 ;
        RECT 1.000 161.480 119.060 162.880 ;
        RECT 1.000 160.160 119.995 161.480 ;
        RECT 1.000 158.760 119.060 160.160 ;
        RECT 1.000 157.440 119.995 158.760 ;
        RECT 1.000 156.040 119.060 157.440 ;
        RECT 1.000 154.720 119.995 156.040 ;
        RECT 1.000 153.320 119.060 154.720 ;
        RECT 1.000 152.000 119.995 153.320 ;
        RECT 1.000 150.600 119.060 152.000 ;
        RECT 1.000 149.280 119.995 150.600 ;
        RECT 1.000 147.880 119.060 149.280 ;
        RECT 1.000 146.560 119.995 147.880 ;
        RECT 1.000 145.160 119.060 146.560 ;
        RECT 1.000 143.840 119.995 145.160 ;
        RECT 1.000 142.440 119.060 143.840 ;
        RECT 1.000 141.120 119.995 142.440 ;
        RECT 1.000 139.720 119.060 141.120 ;
        RECT 1.000 138.400 119.995 139.720 ;
        RECT 1.000 137.000 119.060 138.400 ;
        RECT 1.000 135.680 119.995 137.000 ;
        RECT 1.000 134.280 119.060 135.680 ;
        RECT 1.000 132.960 119.995 134.280 ;
        RECT 1.000 131.560 119.060 132.960 ;
        RECT 1.000 130.240 119.995 131.560 ;
        RECT 1.000 128.840 119.060 130.240 ;
        RECT 1.000 127.520 119.995 128.840 ;
        RECT 1.000 126.120 119.060 127.520 ;
        RECT 1.000 124.800 119.995 126.120 ;
        RECT 1.000 123.400 119.060 124.800 ;
        RECT 1.000 122.080 119.995 123.400 ;
        RECT 1.000 120.680 119.060 122.080 ;
        RECT 1.000 119.360 119.995 120.680 ;
        RECT 1.000 117.960 119.060 119.360 ;
        RECT 1.000 116.640 119.995 117.960 ;
        RECT 1.000 115.240 119.060 116.640 ;
        RECT 1.000 113.920 119.995 115.240 ;
        RECT 1.000 112.520 119.060 113.920 ;
        RECT 1.000 111.200 119.995 112.520 ;
        RECT 1.000 109.800 119.060 111.200 ;
        RECT 1.000 108.480 119.995 109.800 ;
        RECT 1.000 107.080 119.060 108.480 ;
        RECT 1.000 105.760 119.995 107.080 ;
        RECT 1.000 104.360 119.060 105.760 ;
        RECT 1.000 103.040 119.995 104.360 ;
        RECT 1.000 101.640 119.060 103.040 ;
        RECT 1.000 100.320 119.995 101.640 ;
        RECT 1.000 98.920 119.060 100.320 ;
        RECT 1.000 97.600 119.995 98.920 ;
        RECT 1.000 96.200 119.060 97.600 ;
        RECT 1.000 94.880 119.995 96.200 ;
        RECT 1.000 93.480 119.060 94.880 ;
        RECT 1.000 92.160 119.995 93.480 ;
        RECT 1.000 90.760 119.060 92.160 ;
        RECT 1.000 89.440 119.995 90.760 ;
        RECT 1.000 88.040 119.060 89.440 ;
        RECT 1.000 86.720 119.995 88.040 ;
        RECT 1.000 85.320 119.060 86.720 ;
        RECT 1.000 84.000 119.995 85.320 ;
        RECT 1.000 82.600 119.060 84.000 ;
        RECT 1.000 81.280 119.995 82.600 ;
        RECT 1.000 79.880 119.060 81.280 ;
        RECT 1.000 78.560 119.995 79.880 ;
        RECT 1.000 77.160 119.060 78.560 ;
        RECT 1.000 75.840 119.995 77.160 ;
        RECT 1.000 74.440 119.060 75.840 ;
        RECT 1.000 73.120 119.995 74.440 ;
        RECT 1.000 71.720 119.060 73.120 ;
        RECT 1.000 70.400 119.995 71.720 ;
        RECT 1.000 69.000 119.060 70.400 ;
        RECT 1.000 67.680 119.995 69.000 ;
        RECT 1.000 66.280 119.060 67.680 ;
        RECT 1.000 64.960 119.995 66.280 ;
        RECT 1.000 63.560 119.060 64.960 ;
        RECT 1.000 62.240 119.995 63.560 ;
        RECT 1.000 60.840 119.060 62.240 ;
        RECT 1.000 59.520 119.995 60.840 ;
        RECT 1.000 58.120 119.060 59.520 ;
        RECT 1.000 56.800 119.995 58.120 ;
        RECT 1.000 55.400 119.060 56.800 ;
        RECT 1.000 54.080 119.995 55.400 ;
        RECT 1.000 52.680 119.060 54.080 ;
        RECT 1.000 51.360 119.995 52.680 ;
        RECT 1.000 49.960 119.060 51.360 ;
        RECT 1.000 48.640 119.995 49.960 ;
        RECT 1.000 47.240 119.060 48.640 ;
        RECT 1.000 45.920 119.995 47.240 ;
        RECT 1.000 44.520 119.060 45.920 ;
        RECT 1.000 43.200 119.995 44.520 ;
        RECT 1.000 41.800 119.060 43.200 ;
        RECT 0.600 40.480 119.995 41.800 ;
        RECT 0.600 39.080 119.060 40.480 ;
        RECT 0.600 37.760 119.995 39.080 ;
        RECT 0.600 36.360 119.060 37.760 ;
        RECT 0.600 35.040 119.995 36.360 ;
        RECT 0.600 33.640 119.060 35.040 ;
        RECT 0.600 32.320 119.995 33.640 ;
        RECT 0.600 30.920 119.060 32.320 ;
        RECT 0.600 29.600 119.995 30.920 ;
        RECT 0.600 28.200 119.060 29.600 ;
        RECT 0.600 26.880 119.995 28.200 ;
        RECT 0.600 25.480 119.060 26.880 ;
        RECT 0.600 24.160 119.995 25.480 ;
        RECT 0.600 22.760 119.060 24.160 ;
        RECT 0.600 21.440 119.995 22.760 ;
        RECT 0.600 20.040 119.060 21.440 ;
        RECT 0.600 18.720 119.995 20.040 ;
        RECT 0.600 17.320 119.060 18.720 ;
        RECT 0.600 16.000 119.995 17.320 ;
        RECT 0.600 14.600 119.060 16.000 ;
        RECT 0.600 13.280 119.995 14.600 ;
        RECT 0.600 11.880 119.060 13.280 ;
        RECT 0.600 10.560 119.995 11.880 ;
        RECT 0.600 9.160 119.060 10.560 ;
        RECT 0.600 7.840 119.995 9.160 ;
        RECT 0.600 6.440 119.060 7.840 ;
        RECT 0.600 0.175 119.995 6.440 ;
      LAYER met4 ;
        RECT 0.310 0.175 9.320 505.745 ;
        RECT 11.720 0.175 14.620 505.745 ;
        RECT 17.020 0.175 39.320 505.745 ;
        RECT 41.720 0.175 44.620 505.745 ;
        RECT 47.020 0.175 69.320 505.745 ;
        RECT 71.720 0.175 74.620 505.745 ;
        RECT 77.020 0.175 99.320 505.745 ;
        RECT 101.720 0.175 104.620 505.745 ;
        RECT 107.020 0.175 119.305 505.745 ;
  END
END OpenRAM
END LIBRARY

